VERSION 5.8 ;
BUSBITCHARS "[]" ;
DIVIDERCHAR "/" ;
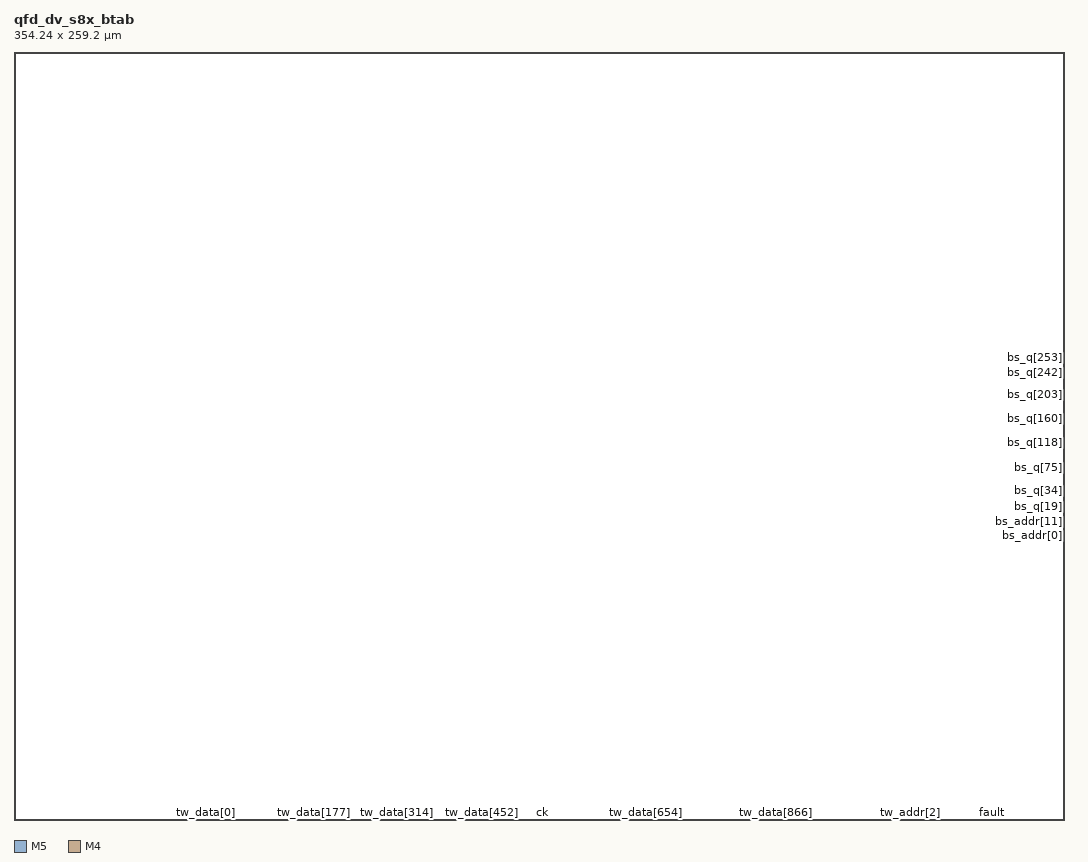
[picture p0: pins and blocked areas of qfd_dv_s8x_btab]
MACRO qfd_dv_s8x_btab
 CLASS BLOCK ;
 ORIGIN 0 0 ;
 SIZE 354.24 BY 259.2 ;
 SYMMETRY X Y ;
 PIN tw_data[0]
  DIRECTION INPUT ;
  USE SIGNAL ;
  PORT
   LAYER M5 ;
   RECT 64.800000 0.000000 64.824000 0.084000 ;
  END
 END tw_data[0]
 PIN tw_data[1]
  DIRECTION INPUT ;
  USE SIGNAL ;
  PORT
   LAYER M5 ;
   RECT 64.992000 0.000000 65.016000 0.084000 ;
  END
 END tw_data[1]
 PIN tw_data[2]
  DIRECTION INPUT ;
  USE SIGNAL ;
  PORT
   LAYER M5 ;
   RECT 65.184000 0.000000 65.208000 0.084000 ;
  END
 END tw_data[2]
 PIN tw_data[3]
  DIRECTION INPUT ;
  USE SIGNAL ;
  PORT
   LAYER M5 ;
   RECT 65.376000 0.000000 65.400000 0.084000 ;
  END
 END tw_data[3]
 PIN tw_data[4]
  DIRECTION INPUT ;
  USE SIGNAL ;
  PORT
   LAYER M5 ;
   RECT 65.568000 0.000000 65.592000 0.084000 ;
  END
 END tw_data[4]
 PIN tw_data[5]
  DIRECTION INPUT ;
  USE SIGNAL ;
  PORT
   LAYER M5 ;
   RECT 65.760000 0.000000 65.784000 0.084000 ;
  END
 END tw_data[5]
 PIN tw_data[6]
  DIRECTION INPUT ;
  USE SIGNAL ;
  PORT
   LAYER M5 ;
   RECT 65.952000 0.000000 65.976000 0.084000 ;
  END
 END tw_data[6]
 PIN tw_data[7]
  DIRECTION INPUT ;
  USE SIGNAL ;
  PORT
   LAYER M5 ;
   RECT 66.144000 0.000000 66.168000 0.084000 ;
  END
 END tw_data[7]
 PIN tw_data[8]
  DIRECTION INPUT ;
  USE SIGNAL ;
  PORT
   LAYER M5 ;
   RECT 66.336000 0.000000 66.360000 0.084000 ;
  END
 END tw_data[8]
 PIN tw_data[9]
  DIRECTION INPUT ;
  USE SIGNAL ;
  PORT
   LAYER M5 ;
   RECT 66.528000 0.000000 66.552000 0.084000 ;
  END
 END tw_data[9]
 PIN tw_data[10]
  DIRECTION INPUT ;
  USE SIGNAL ;
  PORT
   LAYER M5 ;
   RECT 66.720000 0.000000 66.744000 0.084000 ;
  END
 END tw_data[10]
 PIN tw_data[11]
  DIRECTION INPUT ;
  USE SIGNAL ;
  PORT
   LAYER M5 ;
   RECT 67.152000 0.000000 67.176000 0.084000 ;
  END
 END tw_data[11]
 PIN tw_data[12]
  DIRECTION INPUT ;
  USE SIGNAL ;
  PORT
   LAYER M5 ;
   RECT 67.344000 0.000000 67.368000 0.084000 ;
  END
 END tw_data[12]
 PIN tw_data[13]
  DIRECTION INPUT ;
  USE SIGNAL ;
  PORT
   LAYER M5 ;
   RECT 67.536000 0.000000 67.560000 0.084000 ;
  END
 END tw_data[13]
 PIN tw_data[14]
  DIRECTION INPUT ;
  USE SIGNAL ;
  PORT
   LAYER M5 ;
   RECT 67.728000 0.000000 67.752000 0.084000 ;
  END
 END tw_data[14]
 PIN tw_data[15]
  DIRECTION INPUT ;
  USE SIGNAL ;
  PORT
   LAYER M5 ;
   RECT 67.920000 0.000000 67.944000 0.084000 ;
  END
 END tw_data[15]
 PIN tw_data[16]
  DIRECTION INPUT ;
  USE SIGNAL ;
  PORT
   LAYER M5 ;
   RECT 68.112000 0.000000 68.136000 0.084000 ;
  END
 END tw_data[16]
 PIN tw_data[17]
  DIRECTION INPUT ;
  USE SIGNAL ;
  PORT
   LAYER M5 ;
   RECT 68.304000 0.000000 68.328000 0.084000 ;
  END
 END tw_data[17]
 PIN tw_data[18]
  DIRECTION INPUT ;
  USE SIGNAL ;
  PORT
   LAYER M5 ;
   RECT 68.496000 0.000000 68.520000 0.084000 ;
  END
 END tw_data[18]
 PIN tw_data[19]
  DIRECTION INPUT ;
  USE SIGNAL ;
  PORT
   LAYER M5 ;
   RECT 68.688000 0.000000 68.712000 0.084000 ;
  END
 END tw_data[19]
 PIN tw_data[20]
  DIRECTION INPUT ;
  USE SIGNAL ;
  PORT
   LAYER M5 ;
   RECT 68.880000 0.000000 68.904000 0.084000 ;
  END
 END tw_data[20]
 PIN tw_data[21]
  DIRECTION INPUT ;
  USE SIGNAL ;
  PORT
   LAYER M5 ;
   RECT 69.072000 0.000000 69.096000 0.084000 ;
  END
 END tw_data[21]
 PIN tw_data[22]
  DIRECTION INPUT ;
  USE SIGNAL ;
  PORT
   LAYER M5 ;
   RECT 69.264000 0.000000 69.288000 0.084000 ;
  END
 END tw_data[22]
 PIN tw_data[23]
  DIRECTION INPUT ;
  USE SIGNAL ;
  PORT
   LAYER M5 ;
   RECT 69.456000 0.000000 69.480000 0.084000 ;
  END
 END tw_data[23]
 PIN tw_data[24]
  DIRECTION INPUT ;
  USE SIGNAL ;
  PORT
   LAYER M5 ;
   RECT 69.648000 0.000000 69.672000 0.084000 ;
  END
 END tw_data[24]
 PIN tw_data[25]
  DIRECTION INPUT ;
  USE SIGNAL ;
  PORT
   LAYER M5 ;
   RECT 69.840000 0.000000 69.864000 0.084000 ;
  END
 END tw_data[25]
 PIN tw_data[26]
  DIRECTION INPUT ;
  USE SIGNAL ;
  PORT
   LAYER M5 ;
   RECT 70.032000 0.000000 70.056000 0.084000 ;
  END
 END tw_data[26]
 PIN tw_data[27]
  DIRECTION INPUT ;
  USE SIGNAL ;
  PORT
   LAYER M5 ;
   RECT 70.224000 0.000000 70.248000 0.084000 ;
  END
 END tw_data[27]
 PIN tw_data[28]
  DIRECTION INPUT ;
  USE SIGNAL ;
  PORT
   LAYER M5 ;
   RECT 70.416000 0.000000 70.440000 0.084000 ;
  END
 END tw_data[28]
 PIN tw_data[29]
  DIRECTION INPUT ;
  USE SIGNAL ;
  PORT
   LAYER M5 ;
   RECT 70.608000 0.000000 70.632000 0.084000 ;
  END
 END tw_data[29]
 PIN tw_data[30]
  DIRECTION INPUT ;
  USE SIGNAL ;
  PORT
   LAYER M5 ;
   RECT 70.800000 0.000000 70.824000 0.084000 ;
  END
 END tw_data[30]
 PIN tw_data[31]
  DIRECTION INPUT ;
  USE SIGNAL ;
  PORT
   LAYER M5 ;
   RECT 70.992000 0.000000 71.016000 0.084000 ;
  END
 END tw_data[31]
 PIN tw_data[32]
  DIRECTION INPUT ;
  USE SIGNAL ;
  PORT
   LAYER M5 ;
   RECT 71.472000 0.000000 71.496000 0.084000 ;
  END
 END tw_data[32]
 PIN tw_data[33]
  DIRECTION INPUT ;
  USE SIGNAL ;
  PORT
   LAYER M5 ;
   RECT 71.664000 0.000000 71.688000 0.084000 ;
  END
 END tw_data[33]
 PIN tw_data[34]
  DIRECTION INPUT ;
  USE SIGNAL ;
  PORT
   LAYER M5 ;
   RECT 71.856000 0.000000 71.880000 0.084000 ;
  END
 END tw_data[34]
 PIN tw_data[35]
  DIRECTION INPUT ;
  USE SIGNAL ;
  PORT
   LAYER M5 ;
   RECT 72.048000 0.000000 72.072000 0.084000 ;
  END
 END tw_data[35]
 PIN tw_data[36]
  DIRECTION INPUT ;
  USE SIGNAL ;
  PORT
   LAYER M5 ;
   RECT 72.240000 0.000000 72.264000 0.084000 ;
  END
 END tw_data[36]
 PIN tw_data[37]
  DIRECTION INPUT ;
  USE SIGNAL ;
  PORT
   LAYER M5 ;
   RECT 72.432000 0.000000 72.456000 0.084000 ;
  END
 END tw_data[37]
 PIN tw_data[38]
  DIRECTION INPUT ;
  USE SIGNAL ;
  PORT
   LAYER M5 ;
   RECT 72.624000 0.000000 72.648000 0.084000 ;
  END
 END tw_data[38]
 PIN tw_data[39]
  DIRECTION INPUT ;
  USE SIGNAL ;
  PORT
   LAYER M5 ;
   RECT 72.816000 0.000000 72.840000 0.084000 ;
  END
 END tw_data[39]
 PIN tw_data[40]
  DIRECTION INPUT ;
  USE SIGNAL ;
  PORT
   LAYER M5 ;
   RECT 73.008000 0.000000 73.032000 0.084000 ;
  END
 END tw_data[40]
 PIN tw_data[41]
  DIRECTION INPUT ;
  USE SIGNAL ;
  PORT
   LAYER M5 ;
   RECT 73.200000 0.000000 73.224000 0.084000 ;
  END
 END tw_data[41]
 PIN tw_data[42]
  DIRECTION INPUT ;
  USE SIGNAL ;
  PORT
   LAYER M5 ;
   RECT 73.392000 0.000000 73.416000 0.084000 ;
  END
 END tw_data[42]
 PIN tw_data[43]
  DIRECTION INPUT ;
  USE SIGNAL ;
  PORT
   LAYER M5 ;
   RECT 73.584000 0.000000 73.608000 0.084000 ;
  END
 END tw_data[43]
 PIN tw_data[44]
  DIRECTION INPUT ;
  USE SIGNAL ;
  PORT
   LAYER M5 ;
   RECT 73.776000 0.000000 73.800000 0.084000 ;
  END
 END tw_data[44]
 PIN tw_data[45]
  DIRECTION INPUT ;
  USE SIGNAL ;
  PORT
   LAYER M5 ;
   RECT 73.968000 0.000000 73.992000 0.084000 ;
  END
 END tw_data[45]
 PIN tw_data[46]
  DIRECTION INPUT ;
  USE SIGNAL ;
  PORT
   LAYER M5 ;
   RECT 74.160000 0.000000 74.184000 0.084000 ;
  END
 END tw_data[46]
 PIN tw_data[47]
  DIRECTION INPUT ;
  USE SIGNAL ;
  PORT
   LAYER M5 ;
   RECT 74.352000 0.000000 74.376000 0.084000 ;
  END
 END tw_data[47]
 PIN tw_data[48]
  DIRECTION INPUT ;
  USE SIGNAL ;
  PORT
   LAYER M5 ;
   RECT 74.544000 0.000000 74.568000 0.084000 ;
  END
 END tw_data[48]
 PIN tw_data[49]
  DIRECTION INPUT ;
  USE SIGNAL ;
  PORT
   LAYER M5 ;
   RECT 74.736000 0.000000 74.760000 0.084000 ;
  END
 END tw_data[49]
 PIN tw_data[50]
  DIRECTION INPUT ;
  USE SIGNAL ;
  PORT
   LAYER M5 ;
   RECT 74.928000 0.000000 74.952000 0.084000 ;
  END
 END tw_data[50]
 PIN tw_data[51]
  DIRECTION INPUT ;
  USE SIGNAL ;
  PORT
   LAYER M5 ;
   RECT 75.120000 0.000000 75.144000 0.084000 ;
  END
 END tw_data[51]
 PIN tw_data[52]
  DIRECTION INPUT ;
  USE SIGNAL ;
  PORT
   LAYER M5 ;
   RECT 75.312000 0.000000 75.336000 0.084000 ;
  END
 END tw_data[52]
 PIN tw_data[53]
  DIRECTION INPUT ;
  USE SIGNAL ;
  PORT
   LAYER M5 ;
   RECT 75.792000 0.000000 75.816000 0.084000 ;
  END
 END tw_data[53]
 PIN tw_data[54]
  DIRECTION INPUT ;
  USE SIGNAL ;
  PORT
   LAYER M5 ;
   RECT 75.984000 0.000000 76.008000 0.084000 ;
  END
 END tw_data[54]
 PIN tw_data[55]
  DIRECTION INPUT ;
  USE SIGNAL ;
  PORT
   LAYER M5 ;
   RECT 76.176000 0.000000 76.200000 0.084000 ;
  END
 END tw_data[55]
 PIN tw_data[56]
  DIRECTION INPUT ;
  USE SIGNAL ;
  PORT
   LAYER M5 ;
   RECT 76.368000 0.000000 76.392000 0.084000 ;
  END
 END tw_data[56]
 PIN tw_data[57]
  DIRECTION INPUT ;
  USE SIGNAL ;
  PORT
   LAYER M5 ;
   RECT 76.560000 0.000000 76.584000 0.084000 ;
  END
 END tw_data[57]
 PIN tw_data[58]
  DIRECTION INPUT ;
  USE SIGNAL ;
  PORT
   LAYER M5 ;
   RECT 76.752000 0.000000 76.776000 0.084000 ;
  END
 END tw_data[58]
 PIN tw_data[59]
  DIRECTION INPUT ;
  USE SIGNAL ;
  PORT
   LAYER M5 ;
   RECT 76.944000 0.000000 76.968000 0.084000 ;
  END
 END tw_data[59]
 PIN tw_data[60]
  DIRECTION INPUT ;
  USE SIGNAL ;
  PORT
   LAYER M5 ;
   RECT 77.136000 0.000000 77.160000 0.084000 ;
  END
 END tw_data[60]
 PIN tw_data[61]
  DIRECTION INPUT ;
  USE SIGNAL ;
  PORT
   LAYER M5 ;
   RECT 77.328000 0.000000 77.352000 0.084000 ;
  END
 END tw_data[61]
 PIN tw_data[62]
  DIRECTION INPUT ;
  USE SIGNAL ;
  PORT
   LAYER M5 ;
   RECT 77.520000 0.000000 77.544000 0.084000 ;
  END
 END tw_data[62]
 PIN tw_data[63]
  DIRECTION INPUT ;
  USE SIGNAL ;
  PORT
   LAYER M5 ;
   RECT 77.712000 0.000000 77.736000 0.084000 ;
  END
 END tw_data[63]
 PIN tw_data[64]
  DIRECTION INPUT ;
  USE SIGNAL ;
  PORT
   LAYER M5 ;
   RECT 77.904000 0.000000 77.928000 0.084000 ;
  END
 END tw_data[64]
 PIN tw_data[65]
  DIRECTION INPUT ;
  USE SIGNAL ;
  PORT
   LAYER M5 ;
   RECT 78.096000 0.000000 78.120000 0.084000 ;
  END
 END tw_data[65]
 PIN tw_data[66]
  DIRECTION INPUT ;
  USE SIGNAL ;
  PORT
   LAYER M5 ;
   RECT 78.288000 0.000000 78.312000 0.084000 ;
  END
 END tw_data[66]
 PIN tw_data[67]
  DIRECTION INPUT ;
  USE SIGNAL ;
  PORT
   LAYER M5 ;
   RECT 78.480000 0.000000 78.504000 0.084000 ;
  END
 END tw_data[67]
 PIN tw_data[68]
  DIRECTION INPUT ;
  USE SIGNAL ;
  PORT
   LAYER M5 ;
   RECT 78.672000 0.000000 78.696000 0.084000 ;
  END
 END tw_data[68]
 PIN tw_data[69]
  DIRECTION INPUT ;
  USE SIGNAL ;
  PORT
   LAYER M5 ;
   RECT 78.864000 0.000000 78.888000 0.084000 ;
  END
 END tw_data[69]
 PIN tw_data[70]
  DIRECTION INPUT ;
  USE SIGNAL ;
  PORT
   LAYER M5 ;
   RECT 79.056000 0.000000 79.080000 0.084000 ;
  END
 END tw_data[70]
 PIN tw_data[71]
  DIRECTION INPUT ;
  USE SIGNAL ;
  PORT
   LAYER M5 ;
   RECT 79.248000 0.000000 79.272000 0.084000 ;
  END
 END tw_data[71]
 PIN tw_data[72]
  DIRECTION INPUT ;
  USE SIGNAL ;
  PORT
   LAYER M5 ;
   RECT 79.440000 0.000000 79.464000 0.084000 ;
  END
 END tw_data[72]
 PIN tw_data[73]
  DIRECTION INPUT ;
  USE SIGNAL ;
  PORT
   LAYER M5 ;
   RECT 79.632000 0.000000 79.656000 0.084000 ;
  END
 END tw_data[73]
 PIN tw_data[74]
  DIRECTION INPUT ;
  USE SIGNAL ;
  PORT
   LAYER M5 ;
   RECT 80.112000 0.000000 80.136000 0.084000 ;
  END
 END tw_data[74]
 PIN tw_data[75]
  DIRECTION INPUT ;
  USE SIGNAL ;
  PORT
   LAYER M5 ;
   RECT 80.304000 0.000000 80.328000 0.084000 ;
  END
 END tw_data[75]
 PIN tw_data[76]
  DIRECTION INPUT ;
  USE SIGNAL ;
  PORT
   LAYER M5 ;
   RECT 80.496000 0.000000 80.520000 0.084000 ;
  END
 END tw_data[76]
 PIN tw_data[77]
  DIRECTION INPUT ;
  USE SIGNAL ;
  PORT
   LAYER M5 ;
   RECT 80.688000 0.000000 80.712000 0.084000 ;
  END
 END tw_data[77]
 PIN tw_data[78]
  DIRECTION INPUT ;
  USE SIGNAL ;
  PORT
   LAYER M5 ;
   RECT 80.880000 0.000000 80.904000 0.084000 ;
  END
 END tw_data[78]
 PIN tw_data[79]
  DIRECTION INPUT ;
  USE SIGNAL ;
  PORT
   LAYER M5 ;
   RECT 81.072000 0.000000 81.096000 0.084000 ;
  END
 END tw_data[79]
 PIN tw_data[80]
  DIRECTION INPUT ;
  USE SIGNAL ;
  PORT
   LAYER M5 ;
   RECT 81.264000 0.000000 81.288000 0.084000 ;
  END
 END tw_data[80]
 PIN tw_data[81]
  DIRECTION INPUT ;
  USE SIGNAL ;
  PORT
   LAYER M5 ;
   RECT 81.456000 0.000000 81.480000 0.084000 ;
  END
 END tw_data[81]
 PIN tw_data[82]
  DIRECTION INPUT ;
  USE SIGNAL ;
  PORT
   LAYER M5 ;
   RECT 81.648000 0.000000 81.672000 0.084000 ;
  END
 END tw_data[82]
 PIN tw_data[83]
  DIRECTION INPUT ;
  USE SIGNAL ;
  PORT
   LAYER M5 ;
   RECT 81.840000 0.000000 81.864000 0.084000 ;
  END
 END tw_data[83]
 PIN tw_data[84]
  DIRECTION INPUT ;
  USE SIGNAL ;
  PORT
   LAYER M5 ;
   RECT 82.032000 0.000000 82.056000 0.084000 ;
  END
 END tw_data[84]
 PIN tw_data[85]
  DIRECTION INPUT ;
  USE SIGNAL ;
  PORT
   LAYER M5 ;
   RECT 82.224000 0.000000 82.248000 0.084000 ;
  END
 END tw_data[85]
 PIN tw_data[86]
  DIRECTION INPUT ;
  USE SIGNAL ;
  PORT
   LAYER M5 ;
   RECT 82.416000 0.000000 82.440000 0.084000 ;
  END
 END tw_data[86]
 PIN tw_data[87]
  DIRECTION INPUT ;
  USE SIGNAL ;
  PORT
   LAYER M5 ;
   RECT 82.608000 0.000000 82.632000 0.084000 ;
  END
 END tw_data[87]
 PIN tw_data[88]
  DIRECTION INPUT ;
  USE SIGNAL ;
  PORT
   LAYER M5 ;
   RECT 82.800000 0.000000 82.824000 0.084000 ;
  END
 END tw_data[88]
 PIN tw_data[89]
  DIRECTION INPUT ;
  USE SIGNAL ;
  PORT
   LAYER M5 ;
   RECT 82.992000 0.000000 83.016000 0.084000 ;
  END
 END tw_data[89]
 PIN tw_data[90]
  DIRECTION INPUT ;
  USE SIGNAL ;
  PORT
   LAYER M5 ;
   RECT 83.184000 0.000000 83.208000 0.084000 ;
  END
 END tw_data[90]
 PIN tw_data[91]
  DIRECTION INPUT ;
  USE SIGNAL ;
  PORT
   LAYER M5 ;
   RECT 83.376000 0.000000 83.400000 0.084000 ;
  END
 END tw_data[91]
 PIN tw_data[92]
  DIRECTION INPUT ;
  USE SIGNAL ;
  PORT
   LAYER M5 ;
   RECT 83.568000 0.000000 83.592000 0.084000 ;
  END
 END tw_data[92]
 PIN tw_data[93]
  DIRECTION INPUT ;
  USE SIGNAL ;
  PORT
   LAYER M5 ;
   RECT 83.760000 0.000000 83.784000 0.084000 ;
  END
 END tw_data[93]
 PIN tw_data[94]
  DIRECTION INPUT ;
  USE SIGNAL ;
  PORT
   LAYER M5 ;
   RECT 83.952000 0.000000 83.976000 0.084000 ;
  END
 END tw_data[94]
 PIN tw_data[95]
  DIRECTION INPUT ;
  USE SIGNAL ;
  PORT
   LAYER M5 ;
   RECT 84.432000 0.000000 84.456000 0.084000 ;
  END
 END tw_data[95]
 PIN tw_data[96]
  DIRECTION INPUT ;
  USE SIGNAL ;
  PORT
   LAYER M5 ;
   RECT 84.624000 0.000000 84.648000 0.084000 ;
  END
 END tw_data[96]
 PIN tw_data[97]
  DIRECTION INPUT ;
  USE SIGNAL ;
  PORT
   LAYER M5 ;
   RECT 84.816000 0.000000 84.840000 0.084000 ;
  END
 END tw_data[97]
 PIN tw_data[98]
  DIRECTION INPUT ;
  USE SIGNAL ;
  PORT
   LAYER M5 ;
   RECT 85.008000 0.000000 85.032000 0.084000 ;
  END
 END tw_data[98]
 PIN tw_data[99]
  DIRECTION INPUT ;
  USE SIGNAL ;
  PORT
   LAYER M5 ;
   RECT 85.200000 0.000000 85.224000 0.084000 ;
  END
 END tw_data[99]
 PIN tw_data[100]
  DIRECTION INPUT ;
  USE SIGNAL ;
  PORT
   LAYER M5 ;
   RECT 85.392000 0.000000 85.416000 0.084000 ;
  END
 END tw_data[100]
 PIN tw_data[101]
  DIRECTION INPUT ;
  USE SIGNAL ;
  PORT
   LAYER M5 ;
   RECT 85.584000 0.000000 85.608000 0.084000 ;
  END
 END tw_data[101]
 PIN tw_data[102]
  DIRECTION INPUT ;
  USE SIGNAL ;
  PORT
   LAYER M5 ;
   RECT 85.776000 0.000000 85.800000 0.084000 ;
  END
 END tw_data[102]
 PIN tw_data[103]
  DIRECTION INPUT ;
  USE SIGNAL ;
  PORT
   LAYER M5 ;
   RECT 85.968000 0.000000 85.992000 0.084000 ;
  END
 END tw_data[103]
 PIN tw_data[104]
  DIRECTION INPUT ;
  USE SIGNAL ;
  PORT
   LAYER M5 ;
   RECT 86.160000 0.000000 86.184000 0.084000 ;
  END
 END tw_data[104]
 PIN tw_data[105]
  DIRECTION INPUT ;
  USE SIGNAL ;
  PORT
   LAYER M5 ;
   RECT 86.352000 0.000000 86.376000 0.084000 ;
  END
 END tw_data[105]
 PIN tw_data[106]
  DIRECTION INPUT ;
  USE SIGNAL ;
  PORT
   LAYER M5 ;
   RECT 86.544000 0.000000 86.568000 0.084000 ;
  END
 END tw_data[106]
 PIN tw_data[107]
  DIRECTION INPUT ;
  USE SIGNAL ;
  PORT
   LAYER M5 ;
   RECT 86.736000 0.000000 86.760000 0.084000 ;
  END
 END tw_data[107]
 PIN tw_data[108]
  DIRECTION INPUT ;
  USE SIGNAL ;
  PORT
   LAYER M5 ;
   RECT 86.928000 0.000000 86.952000 0.084000 ;
  END
 END tw_data[108]
 PIN tw_data[109]
  DIRECTION INPUT ;
  USE SIGNAL ;
  PORT
   LAYER M5 ;
   RECT 87.120000 0.000000 87.144000 0.084000 ;
  END
 END tw_data[109]
 PIN tw_data[110]
  DIRECTION INPUT ;
  USE SIGNAL ;
  PORT
   LAYER M5 ;
   RECT 87.312000 0.000000 87.336000 0.084000 ;
  END
 END tw_data[110]
 PIN tw_data[111]
  DIRECTION INPUT ;
  USE SIGNAL ;
  PORT
   LAYER M5 ;
   RECT 87.504000 0.000000 87.528000 0.084000 ;
  END
 END tw_data[111]
 PIN tw_data[112]
  DIRECTION INPUT ;
  USE SIGNAL ;
  PORT
   LAYER M5 ;
   RECT 87.696000 0.000000 87.720000 0.084000 ;
  END
 END tw_data[112]
 PIN tw_data[113]
  DIRECTION INPUT ;
  USE SIGNAL ;
  PORT
   LAYER M5 ;
   RECT 87.888000 0.000000 87.912000 0.084000 ;
  END
 END tw_data[113]
 PIN tw_data[114]
  DIRECTION INPUT ;
  USE SIGNAL ;
  PORT
   LAYER M5 ;
   RECT 88.080000 0.000000 88.104000 0.084000 ;
  END
 END tw_data[114]
 PIN tw_data[115]
  DIRECTION INPUT ;
  USE SIGNAL ;
  PORT
   LAYER M5 ;
   RECT 88.272000 0.000000 88.296000 0.084000 ;
  END
 END tw_data[115]
 PIN tw_data[116]
  DIRECTION INPUT ;
  USE SIGNAL ;
  PORT
   LAYER M5 ;
   RECT 88.752000 0.000000 88.776000 0.084000 ;
  END
 END tw_data[116]
 PIN tw_data[117]
  DIRECTION INPUT ;
  USE SIGNAL ;
  PORT
   LAYER M5 ;
   RECT 88.944000 0.000000 88.968000 0.084000 ;
  END
 END tw_data[117]
 PIN tw_data[118]
  DIRECTION INPUT ;
  USE SIGNAL ;
  PORT
   LAYER M5 ;
   RECT 89.136000 0.000000 89.160000 0.084000 ;
  END
 END tw_data[118]
 PIN tw_data[119]
  DIRECTION INPUT ;
  USE SIGNAL ;
  PORT
   LAYER M5 ;
   RECT 89.328000 0.000000 89.352000 0.084000 ;
  END
 END tw_data[119]
 PIN tw_data[120]
  DIRECTION INPUT ;
  USE SIGNAL ;
  PORT
   LAYER M5 ;
   RECT 89.520000 0.000000 89.544000 0.084000 ;
  END
 END tw_data[120]
 PIN tw_data[121]
  DIRECTION INPUT ;
  USE SIGNAL ;
  PORT
   LAYER M5 ;
   RECT 89.712000 0.000000 89.736000 0.084000 ;
  END
 END tw_data[121]
 PIN tw_data[122]
  DIRECTION INPUT ;
  USE SIGNAL ;
  PORT
   LAYER M5 ;
   RECT 89.904000 0.000000 89.928000 0.084000 ;
  END
 END tw_data[122]
 PIN tw_data[123]
  DIRECTION INPUT ;
  USE SIGNAL ;
  PORT
   LAYER M5 ;
   RECT 90.096000 0.000000 90.120000 0.084000 ;
  END
 END tw_data[123]
 PIN tw_data[124]
  DIRECTION INPUT ;
  USE SIGNAL ;
  PORT
   LAYER M5 ;
   RECT 90.288000 0.000000 90.312000 0.084000 ;
  END
 END tw_data[124]
 PIN tw_data[125]
  DIRECTION INPUT ;
  USE SIGNAL ;
  PORT
   LAYER M5 ;
   RECT 90.480000 0.000000 90.504000 0.084000 ;
  END
 END tw_data[125]
 PIN tw_data[126]
  DIRECTION INPUT ;
  USE SIGNAL ;
  PORT
   LAYER M5 ;
   RECT 90.672000 0.000000 90.696000 0.084000 ;
  END
 END tw_data[126]
 PIN tw_data[127]
  DIRECTION INPUT ;
  USE SIGNAL ;
  PORT
   LAYER M5 ;
   RECT 90.864000 0.000000 90.888000 0.084000 ;
  END
 END tw_data[127]
 PIN tw_data[128]
  DIRECTION INPUT ;
  USE SIGNAL ;
  PORT
   LAYER M5 ;
   RECT 91.056000 0.000000 91.080000 0.084000 ;
  END
 END tw_data[128]
 PIN tw_data[129]
  DIRECTION INPUT ;
  USE SIGNAL ;
  PORT
   LAYER M5 ;
   RECT 91.248000 0.000000 91.272000 0.084000 ;
  END
 END tw_data[129]
 PIN tw_data[130]
  DIRECTION INPUT ;
  USE SIGNAL ;
  PORT
   LAYER M5 ;
   RECT 91.440000 0.000000 91.464000 0.084000 ;
  END
 END tw_data[130]
 PIN tw_data[131]
  DIRECTION INPUT ;
  USE SIGNAL ;
  PORT
   LAYER M5 ;
   RECT 91.632000 0.000000 91.656000 0.084000 ;
  END
 END tw_data[131]
 PIN tw_data[132]
  DIRECTION INPUT ;
  USE SIGNAL ;
  PORT
   LAYER M5 ;
   RECT 91.824000 0.000000 91.848000 0.084000 ;
  END
 END tw_data[132]
 PIN tw_data[133]
  DIRECTION INPUT ;
  USE SIGNAL ;
  PORT
   LAYER M5 ;
   RECT 92.016000 0.000000 92.040000 0.084000 ;
  END
 END tw_data[133]
 PIN tw_data[134]
  DIRECTION INPUT ;
  USE SIGNAL ;
  PORT
   LAYER M5 ;
   RECT 92.208000 0.000000 92.232000 0.084000 ;
  END
 END tw_data[134]
 PIN tw_data[135]
  DIRECTION INPUT ;
  USE SIGNAL ;
  PORT
   LAYER M5 ;
   RECT 92.400000 0.000000 92.424000 0.084000 ;
  END
 END tw_data[135]
 PIN tw_data[136]
  DIRECTION INPUT ;
  USE SIGNAL ;
  PORT
   LAYER M5 ;
   RECT 92.592000 0.000000 92.616000 0.084000 ;
  END
 END tw_data[136]
 PIN tw_data[137]
  DIRECTION INPUT ;
  USE SIGNAL ;
  PORT
   LAYER M5 ;
   RECT 93.072000 0.000000 93.096000 0.084000 ;
  END
 END tw_data[137]
 PIN tw_data[138]
  DIRECTION INPUT ;
  USE SIGNAL ;
  PORT
   LAYER M5 ;
   RECT 93.264000 0.000000 93.288000 0.084000 ;
  END
 END tw_data[138]
 PIN tw_data[139]
  DIRECTION INPUT ;
  USE SIGNAL ;
  PORT
   LAYER M5 ;
   RECT 93.456000 0.000000 93.480000 0.084000 ;
  END
 END tw_data[139]
 PIN tw_data[140]
  DIRECTION INPUT ;
  USE SIGNAL ;
  PORT
   LAYER M5 ;
   RECT 93.648000 0.000000 93.672000 0.084000 ;
  END
 END tw_data[140]
 PIN tw_data[141]
  DIRECTION INPUT ;
  USE SIGNAL ;
  PORT
   LAYER M5 ;
   RECT 93.840000 0.000000 93.864000 0.084000 ;
  END
 END tw_data[141]
 PIN tw_data[142]
  DIRECTION INPUT ;
  USE SIGNAL ;
  PORT
   LAYER M5 ;
   RECT 94.032000 0.000000 94.056000 0.084000 ;
  END
 END tw_data[142]
 PIN tw_data[143]
  DIRECTION INPUT ;
  USE SIGNAL ;
  PORT
   LAYER M5 ;
   RECT 94.224000 0.000000 94.248000 0.084000 ;
  END
 END tw_data[143]
 PIN tw_data[144]
  DIRECTION INPUT ;
  USE SIGNAL ;
  PORT
   LAYER M5 ;
   RECT 94.416000 0.000000 94.440000 0.084000 ;
  END
 END tw_data[144]
 PIN tw_data[145]
  DIRECTION INPUT ;
  USE SIGNAL ;
  PORT
   LAYER M5 ;
   RECT 94.608000 0.000000 94.632000 0.084000 ;
  END
 END tw_data[145]
 PIN tw_data[146]
  DIRECTION INPUT ;
  USE SIGNAL ;
  PORT
   LAYER M5 ;
   RECT 94.800000 0.000000 94.824000 0.084000 ;
  END
 END tw_data[146]
 PIN tw_data[147]
  DIRECTION INPUT ;
  USE SIGNAL ;
  PORT
   LAYER M5 ;
   RECT 94.992000 0.000000 95.016000 0.084000 ;
  END
 END tw_data[147]
 PIN tw_data[148]
  DIRECTION INPUT ;
  USE SIGNAL ;
  PORT
   LAYER M5 ;
   RECT 95.184000 0.000000 95.208000 0.084000 ;
  END
 END tw_data[148]
 PIN tw_data[149]
  DIRECTION INPUT ;
  USE SIGNAL ;
  PORT
   LAYER M5 ;
   RECT 95.376000 0.000000 95.400000 0.084000 ;
  END
 END tw_data[149]
 PIN tw_data[150]
  DIRECTION INPUT ;
  USE SIGNAL ;
  PORT
   LAYER M5 ;
   RECT 95.568000 0.000000 95.592000 0.084000 ;
  END
 END tw_data[150]
 PIN tw_data[151]
  DIRECTION INPUT ;
  USE SIGNAL ;
  PORT
   LAYER M5 ;
   RECT 95.760000 0.000000 95.784000 0.084000 ;
  END
 END tw_data[151]
 PIN tw_data[152]
  DIRECTION INPUT ;
  USE SIGNAL ;
  PORT
   LAYER M5 ;
   RECT 95.952000 0.000000 95.976000 0.084000 ;
  END
 END tw_data[152]
 PIN tw_data[153]
  DIRECTION INPUT ;
  USE SIGNAL ;
  PORT
   LAYER M5 ;
   RECT 96.144000 0.000000 96.168000 0.084000 ;
  END
 END tw_data[153]
 PIN tw_data[154]
  DIRECTION INPUT ;
  USE SIGNAL ;
  PORT
   LAYER M5 ;
   RECT 96.336000 0.000000 96.360000 0.084000 ;
  END
 END tw_data[154]
 PIN tw_data[155]
  DIRECTION INPUT ;
  USE SIGNAL ;
  PORT
   LAYER M5 ;
   RECT 96.528000 0.000000 96.552000 0.084000 ;
  END
 END tw_data[155]
 PIN tw_data[156]
  DIRECTION INPUT ;
  USE SIGNAL ;
  PORT
   LAYER M5 ;
   RECT 96.720000 0.000000 96.744000 0.084000 ;
  END
 END tw_data[156]
 PIN tw_data[157]
  DIRECTION INPUT ;
  USE SIGNAL ;
  PORT
   LAYER M5 ;
   RECT 96.912000 0.000000 96.936000 0.084000 ;
  END
 END tw_data[157]
 PIN tw_data[158]
  DIRECTION INPUT ;
  USE SIGNAL ;
  PORT
   LAYER M5 ;
   RECT 97.392000 0.000000 97.416000 0.084000 ;
  END
 END tw_data[158]
 PIN tw_data[159]
  DIRECTION INPUT ;
  USE SIGNAL ;
  PORT
   LAYER M5 ;
   RECT 97.584000 0.000000 97.608000 0.084000 ;
  END
 END tw_data[159]
 PIN tw_data[160]
  DIRECTION INPUT ;
  USE SIGNAL ;
  PORT
   LAYER M5 ;
   RECT 97.776000 0.000000 97.800000 0.084000 ;
  END
 END tw_data[160]
 PIN tw_data[161]
  DIRECTION INPUT ;
  USE SIGNAL ;
  PORT
   LAYER M5 ;
   RECT 97.968000 0.000000 97.992000 0.084000 ;
  END
 END tw_data[161]
 PIN tw_data[162]
  DIRECTION INPUT ;
  USE SIGNAL ;
  PORT
   LAYER M5 ;
   RECT 98.160000 0.000000 98.184000 0.084000 ;
  END
 END tw_data[162]
 PIN tw_data[163]
  DIRECTION INPUT ;
  USE SIGNAL ;
  PORT
   LAYER M5 ;
   RECT 98.352000 0.000000 98.376000 0.084000 ;
  END
 END tw_data[163]
 PIN tw_data[164]
  DIRECTION INPUT ;
  USE SIGNAL ;
  PORT
   LAYER M5 ;
   RECT 98.544000 0.000000 98.568000 0.084000 ;
  END
 END tw_data[164]
 PIN tw_data[165]
  DIRECTION INPUT ;
  USE SIGNAL ;
  PORT
   LAYER M5 ;
   RECT 98.736000 0.000000 98.760000 0.084000 ;
  END
 END tw_data[165]
 PIN tw_data[166]
  DIRECTION INPUT ;
  USE SIGNAL ;
  PORT
   LAYER M5 ;
   RECT 98.928000 0.000000 98.952000 0.084000 ;
  END
 END tw_data[166]
 PIN tw_data[167]
  DIRECTION INPUT ;
  USE SIGNAL ;
  PORT
   LAYER M5 ;
   RECT 99.120000 0.000000 99.144000 0.084000 ;
  END
 END tw_data[167]
 PIN tw_data[168]
  DIRECTION INPUT ;
  USE SIGNAL ;
  PORT
   LAYER M5 ;
   RECT 99.312000 0.000000 99.336000 0.084000 ;
  END
 END tw_data[168]
 PIN tw_data[169]
  DIRECTION INPUT ;
  USE SIGNAL ;
  PORT
   LAYER M5 ;
   RECT 99.504000 0.000000 99.528000 0.084000 ;
  END
 END tw_data[169]
 PIN tw_data[170]
  DIRECTION INPUT ;
  USE SIGNAL ;
  PORT
   LAYER M5 ;
   RECT 99.696000 0.000000 99.720000 0.084000 ;
  END
 END tw_data[170]
 PIN tw_data[171]
  DIRECTION INPUT ;
  USE SIGNAL ;
  PORT
   LAYER M5 ;
   RECT 99.888000 0.000000 99.912000 0.084000 ;
  END
 END tw_data[171]
 PIN tw_data[172]
  DIRECTION INPUT ;
  USE SIGNAL ;
  PORT
   LAYER M5 ;
   RECT 100.080000 0.000000 100.104000 0.084000 ;
  END
 END tw_data[172]
 PIN tw_data[173]
  DIRECTION INPUT ;
  USE SIGNAL ;
  PORT
   LAYER M5 ;
   RECT 100.272000 0.000000 100.296000 0.084000 ;
  END
 END tw_data[173]
 PIN tw_data[174]
  DIRECTION INPUT ;
  USE SIGNAL ;
  PORT
   LAYER M5 ;
   RECT 100.464000 0.000000 100.488000 0.084000 ;
  END
 END tw_data[174]
 PIN tw_data[175]
  DIRECTION INPUT ;
  USE SIGNAL ;
  PORT
   LAYER M5 ;
   RECT 100.656000 0.000000 100.680000 0.084000 ;
  END
 END tw_data[175]
 PIN tw_data[176]
  DIRECTION INPUT ;
  USE SIGNAL ;
  PORT
   LAYER M5 ;
   RECT 100.848000 0.000000 100.872000 0.084000 ;
  END
 END tw_data[176]
 PIN tw_data[177]
  DIRECTION INPUT ;
  USE SIGNAL ;
  PORT
   LAYER M5 ;
   RECT 101.040000 0.000000 101.064000 0.084000 ;
  END
 END tw_data[177]
 PIN tw_data[178]
  DIRECTION INPUT ;
  USE SIGNAL ;
  PORT
   LAYER M5 ;
   RECT 101.232000 0.000000 101.256000 0.084000 ;
  END
 END tw_data[178]
 PIN tw_data[179]
  DIRECTION INPUT ;
  USE SIGNAL ;
  PORT
   LAYER M5 ;
   RECT 101.712000 0.000000 101.736000 0.084000 ;
  END
 END tw_data[179]
 PIN tw_data[180]
  DIRECTION INPUT ;
  USE SIGNAL ;
  PORT
   LAYER M5 ;
   RECT 101.904000 0.000000 101.928000 0.084000 ;
  END
 END tw_data[180]
 PIN tw_data[181]
  DIRECTION INPUT ;
  USE SIGNAL ;
  PORT
   LAYER M5 ;
   RECT 102.096000 0.000000 102.120000 0.084000 ;
  END
 END tw_data[181]
 PIN tw_data[182]
  DIRECTION INPUT ;
  USE SIGNAL ;
  PORT
   LAYER M5 ;
   RECT 102.288000 0.000000 102.312000 0.084000 ;
  END
 END tw_data[182]
 PIN tw_data[183]
  DIRECTION INPUT ;
  USE SIGNAL ;
  PORT
   LAYER M5 ;
   RECT 102.480000 0.000000 102.504000 0.084000 ;
  END
 END tw_data[183]
 PIN tw_data[184]
  DIRECTION INPUT ;
  USE SIGNAL ;
  PORT
   LAYER M5 ;
   RECT 102.672000 0.000000 102.696000 0.084000 ;
  END
 END tw_data[184]
 PIN tw_data[185]
  DIRECTION INPUT ;
  USE SIGNAL ;
  PORT
   LAYER M5 ;
   RECT 102.864000 0.000000 102.888000 0.084000 ;
  END
 END tw_data[185]
 PIN tw_data[186]
  DIRECTION INPUT ;
  USE SIGNAL ;
  PORT
   LAYER M5 ;
   RECT 103.056000 0.000000 103.080000 0.084000 ;
  END
 END tw_data[186]
 PIN tw_data[187]
  DIRECTION INPUT ;
  USE SIGNAL ;
  PORT
   LAYER M5 ;
   RECT 103.248000 0.000000 103.272000 0.084000 ;
  END
 END tw_data[187]
 PIN tw_data[188]
  DIRECTION INPUT ;
  USE SIGNAL ;
  PORT
   LAYER M5 ;
   RECT 103.440000 0.000000 103.464000 0.084000 ;
  END
 END tw_data[188]
 PIN tw_data[189]
  DIRECTION INPUT ;
  USE SIGNAL ;
  PORT
   LAYER M5 ;
   RECT 103.632000 0.000000 103.656000 0.084000 ;
  END
 END tw_data[189]
 PIN tw_data[190]
  DIRECTION INPUT ;
  USE SIGNAL ;
  PORT
   LAYER M5 ;
   RECT 103.824000 0.000000 103.848000 0.084000 ;
  END
 END tw_data[190]
 PIN tw_data[191]
  DIRECTION INPUT ;
  USE SIGNAL ;
  PORT
   LAYER M5 ;
   RECT 104.016000 0.000000 104.040000 0.084000 ;
  END
 END tw_data[191]
 PIN tw_data[192]
  DIRECTION INPUT ;
  USE SIGNAL ;
  PORT
   LAYER M5 ;
   RECT 104.208000 0.000000 104.232000 0.084000 ;
  END
 END tw_data[192]
 PIN tw_data[193]
  DIRECTION INPUT ;
  USE SIGNAL ;
  PORT
   LAYER M5 ;
   RECT 104.400000 0.000000 104.424000 0.084000 ;
  END
 END tw_data[193]
 PIN tw_data[194]
  DIRECTION INPUT ;
  USE SIGNAL ;
  PORT
   LAYER M5 ;
   RECT 104.592000 0.000000 104.616000 0.084000 ;
  END
 END tw_data[194]
 PIN tw_data[195]
  DIRECTION INPUT ;
  USE SIGNAL ;
  PORT
   LAYER M5 ;
   RECT 104.784000 0.000000 104.808000 0.084000 ;
  END
 END tw_data[195]
 PIN tw_data[196]
  DIRECTION INPUT ;
  USE SIGNAL ;
  PORT
   LAYER M5 ;
   RECT 104.976000 0.000000 105.000000 0.084000 ;
  END
 END tw_data[196]
 PIN tw_data[197]
  DIRECTION INPUT ;
  USE SIGNAL ;
  PORT
   LAYER M5 ;
   RECT 105.168000 0.000000 105.192000 0.084000 ;
  END
 END tw_data[197]
 PIN tw_data[198]
  DIRECTION INPUT ;
  USE SIGNAL ;
  PORT
   LAYER M5 ;
   RECT 105.360000 0.000000 105.384000 0.084000 ;
  END
 END tw_data[198]
 PIN tw_data[199]
  DIRECTION INPUT ;
  USE SIGNAL ;
  PORT
   LAYER M5 ;
   RECT 105.552000 0.000000 105.576000 0.084000 ;
  END
 END tw_data[199]
 PIN tw_data[200]
  DIRECTION INPUT ;
  USE SIGNAL ;
  PORT
   LAYER M5 ;
   RECT 106.032000 0.000000 106.056000 0.084000 ;
  END
 END tw_data[200]
 PIN tw_data[201]
  DIRECTION INPUT ;
  USE SIGNAL ;
  PORT
   LAYER M5 ;
   RECT 106.224000 0.000000 106.248000 0.084000 ;
  END
 END tw_data[201]
 PIN tw_data[202]
  DIRECTION INPUT ;
  USE SIGNAL ;
  PORT
   LAYER M5 ;
   RECT 106.416000 0.000000 106.440000 0.084000 ;
  END
 END tw_data[202]
 PIN tw_data[203]
  DIRECTION INPUT ;
  USE SIGNAL ;
  PORT
   LAYER M5 ;
   RECT 106.608000 0.000000 106.632000 0.084000 ;
  END
 END tw_data[203]
 PIN tw_data[204]
  DIRECTION INPUT ;
  USE SIGNAL ;
  PORT
   LAYER M5 ;
   RECT 106.800000 0.000000 106.824000 0.084000 ;
  END
 END tw_data[204]
 PIN tw_data[205]
  DIRECTION INPUT ;
  USE SIGNAL ;
  PORT
   LAYER M5 ;
   RECT 106.992000 0.000000 107.016000 0.084000 ;
  END
 END tw_data[205]
 PIN tw_data[206]
  DIRECTION INPUT ;
  USE SIGNAL ;
  PORT
   LAYER M5 ;
   RECT 107.184000 0.000000 107.208000 0.084000 ;
  END
 END tw_data[206]
 PIN tw_data[207]
  DIRECTION INPUT ;
  USE SIGNAL ;
  PORT
   LAYER M5 ;
   RECT 107.376000 0.000000 107.400000 0.084000 ;
  END
 END tw_data[207]
 PIN tw_data[208]
  DIRECTION INPUT ;
  USE SIGNAL ;
  PORT
   LAYER M5 ;
   RECT 107.568000 0.000000 107.592000 0.084000 ;
  END
 END tw_data[208]
 PIN tw_data[209]
  DIRECTION INPUT ;
  USE SIGNAL ;
  PORT
   LAYER M5 ;
   RECT 107.760000 0.000000 107.784000 0.084000 ;
  END
 END tw_data[209]
 PIN tw_data[210]
  DIRECTION INPUT ;
  USE SIGNAL ;
  PORT
   LAYER M5 ;
   RECT 107.952000 0.000000 107.976000 0.084000 ;
  END
 END tw_data[210]
 PIN tw_data[211]
  DIRECTION INPUT ;
  USE SIGNAL ;
  PORT
   LAYER M5 ;
   RECT 108.144000 0.000000 108.168000 0.084000 ;
  END
 END tw_data[211]
 PIN tw_data[212]
  DIRECTION INPUT ;
  USE SIGNAL ;
  PORT
   LAYER M5 ;
   RECT 108.336000 0.000000 108.360000 0.084000 ;
  END
 END tw_data[212]
 PIN tw_data[213]
  DIRECTION INPUT ;
  USE SIGNAL ;
  PORT
   LAYER M5 ;
   RECT 108.528000 0.000000 108.552000 0.084000 ;
  END
 END tw_data[213]
 PIN tw_data[214]
  DIRECTION INPUT ;
  USE SIGNAL ;
  PORT
   LAYER M5 ;
   RECT 108.720000 0.000000 108.744000 0.084000 ;
  END
 END tw_data[214]
 PIN tw_data[215]
  DIRECTION INPUT ;
  USE SIGNAL ;
  PORT
   LAYER M5 ;
   RECT 108.912000 0.000000 108.936000 0.084000 ;
  END
 END tw_data[215]
 PIN tw_data[216]
  DIRECTION INPUT ;
  USE SIGNAL ;
  PORT
   LAYER M5 ;
   RECT 109.104000 0.000000 109.128000 0.084000 ;
  END
 END tw_data[216]
 PIN tw_data[217]
  DIRECTION INPUT ;
  USE SIGNAL ;
  PORT
   LAYER M5 ;
   RECT 109.296000 0.000000 109.320000 0.084000 ;
  END
 END tw_data[217]
 PIN tw_data[218]
  DIRECTION INPUT ;
  USE SIGNAL ;
  PORT
   LAYER M5 ;
   RECT 109.488000 0.000000 109.512000 0.084000 ;
  END
 END tw_data[218]
 PIN tw_data[219]
  DIRECTION INPUT ;
  USE SIGNAL ;
  PORT
   LAYER M5 ;
   RECT 109.680000 0.000000 109.704000 0.084000 ;
  END
 END tw_data[219]
 PIN tw_data[220]
  DIRECTION INPUT ;
  USE SIGNAL ;
  PORT
   LAYER M5 ;
   RECT 109.872000 0.000000 109.896000 0.084000 ;
  END
 END tw_data[220]
 PIN tw_data[221]
  DIRECTION INPUT ;
  USE SIGNAL ;
  PORT
   LAYER M5 ;
   RECT 110.352000 0.000000 110.376000 0.084000 ;
  END
 END tw_data[221]
 PIN tw_data[222]
  DIRECTION INPUT ;
  USE SIGNAL ;
  PORT
   LAYER M5 ;
   RECT 110.544000 0.000000 110.568000 0.084000 ;
  END
 END tw_data[222]
 PIN tw_data[223]
  DIRECTION INPUT ;
  USE SIGNAL ;
  PORT
   LAYER M5 ;
   RECT 110.736000 0.000000 110.760000 0.084000 ;
  END
 END tw_data[223]
 PIN tw_data[224]
  DIRECTION INPUT ;
  USE SIGNAL ;
  PORT
   LAYER M5 ;
   RECT 110.928000 0.000000 110.952000 0.084000 ;
  END
 END tw_data[224]
 PIN tw_data[225]
  DIRECTION INPUT ;
  USE SIGNAL ;
  PORT
   LAYER M5 ;
   RECT 111.120000 0.000000 111.144000 0.084000 ;
  END
 END tw_data[225]
 PIN tw_data[226]
  DIRECTION INPUT ;
  USE SIGNAL ;
  PORT
   LAYER M5 ;
   RECT 111.312000 0.000000 111.336000 0.084000 ;
  END
 END tw_data[226]
 PIN tw_data[227]
  DIRECTION INPUT ;
  USE SIGNAL ;
  PORT
   LAYER M5 ;
   RECT 111.504000 0.000000 111.528000 0.084000 ;
  END
 END tw_data[227]
 PIN tw_data[228]
  DIRECTION INPUT ;
  USE SIGNAL ;
  PORT
   LAYER M5 ;
   RECT 111.696000 0.000000 111.720000 0.084000 ;
  END
 END tw_data[228]
 PIN tw_data[229]
  DIRECTION INPUT ;
  USE SIGNAL ;
  PORT
   LAYER M5 ;
   RECT 111.888000 0.000000 111.912000 0.084000 ;
  END
 END tw_data[229]
 PIN tw_data[230]
  DIRECTION INPUT ;
  USE SIGNAL ;
  PORT
   LAYER M5 ;
   RECT 112.080000 0.000000 112.104000 0.084000 ;
  END
 END tw_data[230]
 PIN tw_data[231]
  DIRECTION INPUT ;
  USE SIGNAL ;
  PORT
   LAYER M5 ;
   RECT 112.272000 0.000000 112.296000 0.084000 ;
  END
 END tw_data[231]
 PIN tw_data[232]
  DIRECTION INPUT ;
  USE SIGNAL ;
  PORT
   LAYER M5 ;
   RECT 112.464000 0.000000 112.488000 0.084000 ;
  END
 END tw_data[232]
 PIN tw_data[233]
  DIRECTION INPUT ;
  USE SIGNAL ;
  PORT
   LAYER M5 ;
   RECT 112.656000 0.000000 112.680000 0.084000 ;
  END
 END tw_data[233]
 PIN tw_data[234]
  DIRECTION INPUT ;
  USE SIGNAL ;
  PORT
   LAYER M5 ;
   RECT 112.848000 0.000000 112.872000 0.084000 ;
  END
 END tw_data[234]
 PIN tw_data[235]
  DIRECTION INPUT ;
  USE SIGNAL ;
  PORT
   LAYER M5 ;
   RECT 113.040000 0.000000 113.064000 0.084000 ;
  END
 END tw_data[235]
 PIN tw_data[236]
  DIRECTION INPUT ;
  USE SIGNAL ;
  PORT
   LAYER M5 ;
   RECT 113.232000 0.000000 113.256000 0.084000 ;
  END
 END tw_data[236]
 PIN tw_data[237]
  DIRECTION INPUT ;
  USE SIGNAL ;
  PORT
   LAYER M5 ;
   RECT 113.424000 0.000000 113.448000 0.084000 ;
  END
 END tw_data[237]
 PIN tw_data[238]
  DIRECTION INPUT ;
  USE SIGNAL ;
  PORT
   LAYER M5 ;
   RECT 113.616000 0.000000 113.640000 0.084000 ;
  END
 END tw_data[238]
 PIN tw_data[239]
  DIRECTION INPUT ;
  USE SIGNAL ;
  PORT
   LAYER M5 ;
   RECT 113.808000 0.000000 113.832000 0.084000 ;
  END
 END tw_data[239]
 PIN tw_data[240]
  DIRECTION INPUT ;
  USE SIGNAL ;
  PORT
   LAYER M5 ;
   RECT 114.000000 0.000000 114.024000 0.084000 ;
  END
 END tw_data[240]
 PIN tw_data[241]
  DIRECTION INPUT ;
  USE SIGNAL ;
  PORT
   LAYER M5 ;
   RECT 114.192000 0.000000 114.216000 0.084000 ;
  END
 END tw_data[241]
 PIN tw_data[242]
  DIRECTION INPUT ;
  USE SIGNAL ;
  PORT
   LAYER M5 ;
   RECT 114.672000 0.000000 114.696000 0.084000 ;
  END
 END tw_data[242]
 PIN tw_data[243]
  DIRECTION INPUT ;
  USE SIGNAL ;
  PORT
   LAYER M5 ;
   RECT 114.864000 0.000000 114.888000 0.084000 ;
  END
 END tw_data[243]
 PIN tw_data[244]
  DIRECTION INPUT ;
  USE SIGNAL ;
  PORT
   LAYER M5 ;
   RECT 115.056000 0.000000 115.080000 0.084000 ;
  END
 END tw_data[244]
 PIN tw_data[245]
  DIRECTION INPUT ;
  USE SIGNAL ;
  PORT
   LAYER M5 ;
   RECT 115.248000 0.000000 115.272000 0.084000 ;
  END
 END tw_data[245]
 PIN tw_data[246]
  DIRECTION INPUT ;
  USE SIGNAL ;
  PORT
   LAYER M5 ;
   RECT 115.440000 0.000000 115.464000 0.084000 ;
  END
 END tw_data[246]
 PIN tw_data[247]
  DIRECTION INPUT ;
  USE SIGNAL ;
  PORT
   LAYER M5 ;
   RECT 115.632000 0.000000 115.656000 0.084000 ;
  END
 END tw_data[247]
 PIN tw_data[248]
  DIRECTION INPUT ;
  USE SIGNAL ;
  PORT
   LAYER M5 ;
   RECT 115.824000 0.000000 115.848000 0.084000 ;
  END
 END tw_data[248]
 PIN tw_data[249]
  DIRECTION INPUT ;
  USE SIGNAL ;
  PORT
   LAYER M5 ;
   RECT 116.016000 0.000000 116.040000 0.084000 ;
  END
 END tw_data[249]
 PIN tw_data[250]
  DIRECTION INPUT ;
  USE SIGNAL ;
  PORT
   LAYER M5 ;
   RECT 116.208000 0.000000 116.232000 0.084000 ;
  END
 END tw_data[250]
 PIN tw_data[251]
  DIRECTION INPUT ;
  USE SIGNAL ;
  PORT
   LAYER M5 ;
   RECT 116.400000 0.000000 116.424000 0.084000 ;
  END
 END tw_data[251]
 PIN tw_data[252]
  DIRECTION INPUT ;
  USE SIGNAL ;
  PORT
   LAYER M5 ;
   RECT 116.592000 0.000000 116.616000 0.084000 ;
  END
 END tw_data[252]
 PIN tw_data[253]
  DIRECTION INPUT ;
  USE SIGNAL ;
  PORT
   LAYER M5 ;
   RECT 116.784000 0.000000 116.808000 0.084000 ;
  END
 END tw_data[253]
 PIN tw_data[254]
  DIRECTION INPUT ;
  USE SIGNAL ;
  PORT
   LAYER M5 ;
   RECT 116.976000 0.000000 117.000000 0.084000 ;
  END
 END tw_data[254]
 PIN tw_data[255]
  DIRECTION INPUT ;
  USE SIGNAL ;
  PORT
   LAYER M5 ;
   RECT 117.168000 0.000000 117.192000 0.084000 ;
  END
 END tw_data[255]
 PIN tw_data[256]
  DIRECTION INPUT ;
  USE SIGNAL ;
  PORT
   LAYER M5 ;
   RECT 117.360000 0.000000 117.384000 0.084000 ;
  END
 END tw_data[256]
 PIN tw_data[257]
  DIRECTION INPUT ;
  USE SIGNAL ;
  PORT
   LAYER M5 ;
   RECT 117.552000 0.000000 117.576000 0.084000 ;
  END
 END tw_data[257]
 PIN tw_data[258]
  DIRECTION INPUT ;
  USE SIGNAL ;
  PORT
   LAYER M5 ;
   RECT 117.744000 0.000000 117.768000 0.084000 ;
  END
 END tw_data[258]
 PIN tw_data[259]
  DIRECTION INPUT ;
  USE SIGNAL ;
  PORT
   LAYER M5 ;
   RECT 117.936000 0.000000 117.960000 0.084000 ;
  END
 END tw_data[259]
 PIN tw_data[260]
  DIRECTION INPUT ;
  USE SIGNAL ;
  PORT
   LAYER M5 ;
   RECT 118.128000 0.000000 118.152000 0.084000 ;
  END
 END tw_data[260]
 PIN tw_data[261]
  DIRECTION INPUT ;
  USE SIGNAL ;
  PORT
   LAYER M5 ;
   RECT 118.320000 0.000000 118.344000 0.084000 ;
  END
 END tw_data[261]
 PIN tw_data[262]
  DIRECTION INPUT ;
  USE SIGNAL ;
  PORT
   LAYER M5 ;
   RECT 118.512000 0.000000 118.536000 0.084000 ;
  END
 END tw_data[262]
 PIN tw_data[263]
  DIRECTION INPUT ;
  USE SIGNAL ;
  PORT
   LAYER M5 ;
   RECT 118.992000 0.000000 119.016000 0.084000 ;
  END
 END tw_data[263]
 PIN tw_data[264]
  DIRECTION INPUT ;
  USE SIGNAL ;
  PORT
   LAYER M5 ;
   RECT 119.184000 0.000000 119.208000 0.084000 ;
  END
 END tw_data[264]
 PIN tw_data[265]
  DIRECTION INPUT ;
  USE SIGNAL ;
  PORT
   LAYER M5 ;
   RECT 119.376000 0.000000 119.400000 0.084000 ;
  END
 END tw_data[265]
 PIN tw_data[266]
  DIRECTION INPUT ;
  USE SIGNAL ;
  PORT
   LAYER M5 ;
   RECT 119.568000 0.000000 119.592000 0.084000 ;
  END
 END tw_data[266]
 PIN tw_data[267]
  DIRECTION INPUT ;
  USE SIGNAL ;
  PORT
   LAYER M5 ;
   RECT 119.760000 0.000000 119.784000 0.084000 ;
  END
 END tw_data[267]
 PIN tw_data[268]
  DIRECTION INPUT ;
  USE SIGNAL ;
  PORT
   LAYER M5 ;
   RECT 119.952000 0.000000 119.976000 0.084000 ;
  END
 END tw_data[268]
 PIN tw_data[269]
  DIRECTION INPUT ;
  USE SIGNAL ;
  PORT
   LAYER M5 ;
   RECT 120.144000 0.000000 120.168000 0.084000 ;
  END
 END tw_data[269]
 PIN tw_data[270]
  DIRECTION INPUT ;
  USE SIGNAL ;
  PORT
   LAYER M5 ;
   RECT 120.336000 0.000000 120.360000 0.084000 ;
  END
 END tw_data[270]
 PIN tw_data[271]
  DIRECTION INPUT ;
  USE SIGNAL ;
  PORT
   LAYER M5 ;
   RECT 120.528000 0.000000 120.552000 0.084000 ;
  END
 END tw_data[271]
 PIN tw_data[272]
  DIRECTION INPUT ;
  USE SIGNAL ;
  PORT
   LAYER M5 ;
   RECT 120.720000 0.000000 120.744000 0.084000 ;
  END
 END tw_data[272]
 PIN tw_data[273]
  DIRECTION INPUT ;
  USE SIGNAL ;
  PORT
   LAYER M5 ;
   RECT 120.912000 0.000000 120.936000 0.084000 ;
  END
 END tw_data[273]
 PIN tw_data[274]
  DIRECTION INPUT ;
  USE SIGNAL ;
  PORT
   LAYER M5 ;
   RECT 121.104000 0.000000 121.128000 0.084000 ;
  END
 END tw_data[274]
 PIN tw_data[275]
  DIRECTION INPUT ;
  USE SIGNAL ;
  PORT
   LAYER M5 ;
   RECT 121.296000 0.000000 121.320000 0.084000 ;
  END
 END tw_data[275]
 PIN tw_data[276]
  DIRECTION INPUT ;
  USE SIGNAL ;
  PORT
   LAYER M5 ;
   RECT 121.488000 0.000000 121.512000 0.084000 ;
  END
 END tw_data[276]
 PIN tw_data[277]
  DIRECTION INPUT ;
  USE SIGNAL ;
  PORT
   LAYER M5 ;
   RECT 121.680000 0.000000 121.704000 0.084000 ;
  END
 END tw_data[277]
 PIN tw_data[278]
  DIRECTION INPUT ;
  USE SIGNAL ;
  PORT
   LAYER M5 ;
   RECT 121.872000 0.000000 121.896000 0.084000 ;
  END
 END tw_data[278]
 PIN tw_data[279]
  DIRECTION INPUT ;
  USE SIGNAL ;
  PORT
   LAYER M5 ;
   RECT 122.064000 0.000000 122.088000 0.084000 ;
  END
 END tw_data[279]
 PIN tw_data[280]
  DIRECTION INPUT ;
  USE SIGNAL ;
  PORT
   LAYER M5 ;
   RECT 122.256000 0.000000 122.280000 0.084000 ;
  END
 END tw_data[280]
 PIN tw_data[281]
  DIRECTION INPUT ;
  USE SIGNAL ;
  PORT
   LAYER M5 ;
   RECT 122.448000 0.000000 122.472000 0.084000 ;
  END
 END tw_data[281]
 PIN tw_data[282]
  DIRECTION INPUT ;
  USE SIGNAL ;
  PORT
   LAYER M5 ;
   RECT 122.640000 0.000000 122.664000 0.084000 ;
  END
 END tw_data[282]
 PIN tw_data[283]
  DIRECTION INPUT ;
  USE SIGNAL ;
  PORT
   LAYER M5 ;
   RECT 122.832000 0.000000 122.856000 0.084000 ;
  END
 END tw_data[283]
 PIN tw_data[284]
  DIRECTION INPUT ;
  USE SIGNAL ;
  PORT
   LAYER M5 ;
   RECT 123.312000 0.000000 123.336000 0.084000 ;
  END
 END tw_data[284]
 PIN tw_data[285]
  DIRECTION INPUT ;
  USE SIGNAL ;
  PORT
   LAYER M5 ;
   RECT 123.504000 0.000000 123.528000 0.084000 ;
  END
 END tw_data[285]
 PIN tw_data[286]
  DIRECTION INPUT ;
  USE SIGNAL ;
  PORT
   LAYER M5 ;
   RECT 123.696000 0.000000 123.720000 0.084000 ;
  END
 END tw_data[286]
 PIN tw_data[287]
  DIRECTION INPUT ;
  USE SIGNAL ;
  PORT
   LAYER M5 ;
   RECT 123.888000 0.000000 123.912000 0.084000 ;
  END
 END tw_data[287]
 PIN tw_data[288]
  DIRECTION INPUT ;
  USE SIGNAL ;
  PORT
   LAYER M5 ;
   RECT 124.080000 0.000000 124.104000 0.084000 ;
  END
 END tw_data[288]
 PIN tw_data[289]
  DIRECTION INPUT ;
  USE SIGNAL ;
  PORT
   LAYER M5 ;
   RECT 124.272000 0.000000 124.296000 0.084000 ;
  END
 END tw_data[289]
 PIN tw_data[290]
  DIRECTION INPUT ;
  USE SIGNAL ;
  PORT
   LAYER M5 ;
   RECT 124.464000 0.000000 124.488000 0.084000 ;
  END
 END tw_data[290]
 PIN tw_data[291]
  DIRECTION INPUT ;
  USE SIGNAL ;
  PORT
   LAYER M5 ;
   RECT 124.656000 0.000000 124.680000 0.084000 ;
  END
 END tw_data[291]
 PIN tw_data[292]
  DIRECTION INPUT ;
  USE SIGNAL ;
  PORT
   LAYER M5 ;
   RECT 124.848000 0.000000 124.872000 0.084000 ;
  END
 END tw_data[292]
 PIN tw_data[293]
  DIRECTION INPUT ;
  USE SIGNAL ;
  PORT
   LAYER M5 ;
   RECT 125.040000 0.000000 125.064000 0.084000 ;
  END
 END tw_data[293]
 PIN tw_data[294]
  DIRECTION INPUT ;
  USE SIGNAL ;
  PORT
   LAYER M5 ;
   RECT 125.232000 0.000000 125.256000 0.084000 ;
  END
 END tw_data[294]
 PIN tw_data[295]
  DIRECTION INPUT ;
  USE SIGNAL ;
  PORT
   LAYER M5 ;
   RECT 125.424000 0.000000 125.448000 0.084000 ;
  END
 END tw_data[295]
 PIN tw_data[296]
  DIRECTION INPUT ;
  USE SIGNAL ;
  PORT
   LAYER M5 ;
   RECT 125.616000 0.000000 125.640000 0.084000 ;
  END
 END tw_data[296]
 PIN tw_data[297]
  DIRECTION INPUT ;
  USE SIGNAL ;
  PORT
   LAYER M5 ;
   RECT 125.808000 0.000000 125.832000 0.084000 ;
  END
 END tw_data[297]
 PIN tw_data[298]
  DIRECTION INPUT ;
  USE SIGNAL ;
  PORT
   LAYER M5 ;
   RECT 126.000000 0.000000 126.024000 0.084000 ;
  END
 END tw_data[298]
 PIN tw_data[299]
  DIRECTION INPUT ;
  USE SIGNAL ;
  PORT
   LAYER M5 ;
   RECT 126.192000 0.000000 126.216000 0.084000 ;
  END
 END tw_data[299]
 PIN tw_data[300]
  DIRECTION INPUT ;
  USE SIGNAL ;
  PORT
   LAYER M5 ;
   RECT 126.384000 0.000000 126.408000 0.084000 ;
  END
 END tw_data[300]
 PIN tw_data[301]
  DIRECTION INPUT ;
  USE SIGNAL ;
  PORT
   LAYER M5 ;
   RECT 126.576000 0.000000 126.600000 0.084000 ;
  END
 END tw_data[301]
 PIN tw_data[302]
  DIRECTION INPUT ;
  USE SIGNAL ;
  PORT
   LAYER M5 ;
   RECT 126.768000 0.000000 126.792000 0.084000 ;
  END
 END tw_data[302]
 PIN tw_data[303]
  DIRECTION INPUT ;
  USE SIGNAL ;
  PORT
   LAYER M5 ;
   RECT 126.960000 0.000000 126.984000 0.084000 ;
  END
 END tw_data[303]
 PIN tw_data[304]
  DIRECTION INPUT ;
  USE SIGNAL ;
  PORT
   LAYER M5 ;
   RECT 127.152000 0.000000 127.176000 0.084000 ;
  END
 END tw_data[304]
 PIN tw_data[305]
  DIRECTION INPUT ;
  USE SIGNAL ;
  PORT
   LAYER M5 ;
   RECT 127.632000 0.000000 127.656000 0.084000 ;
  END
 END tw_data[305]
 PIN tw_data[306]
  DIRECTION INPUT ;
  USE SIGNAL ;
  PORT
   LAYER M5 ;
   RECT 127.824000 0.000000 127.848000 0.084000 ;
  END
 END tw_data[306]
 PIN tw_data[307]
  DIRECTION INPUT ;
  USE SIGNAL ;
  PORT
   LAYER M5 ;
   RECT 128.016000 0.000000 128.040000 0.084000 ;
  END
 END tw_data[307]
 PIN tw_data[308]
  DIRECTION INPUT ;
  USE SIGNAL ;
  PORT
   LAYER M5 ;
   RECT 128.208000 0.000000 128.232000 0.084000 ;
  END
 END tw_data[308]
 PIN tw_data[309]
  DIRECTION INPUT ;
  USE SIGNAL ;
  PORT
   LAYER M5 ;
   RECT 128.400000 0.000000 128.424000 0.084000 ;
  END
 END tw_data[309]
 PIN tw_data[310]
  DIRECTION INPUT ;
  USE SIGNAL ;
  PORT
   LAYER M5 ;
   RECT 128.592000 0.000000 128.616000 0.084000 ;
  END
 END tw_data[310]
 PIN tw_data[311]
  DIRECTION INPUT ;
  USE SIGNAL ;
  PORT
   LAYER M5 ;
   RECT 128.784000 0.000000 128.808000 0.084000 ;
  END
 END tw_data[311]
 PIN tw_data[312]
  DIRECTION INPUT ;
  USE SIGNAL ;
  PORT
   LAYER M5 ;
   RECT 128.976000 0.000000 129.000000 0.084000 ;
  END
 END tw_data[312]
 PIN tw_data[313]
  DIRECTION INPUT ;
  USE SIGNAL ;
  PORT
   LAYER M5 ;
   RECT 129.168000 0.000000 129.192000 0.084000 ;
  END
 END tw_data[313]
 PIN tw_data[314]
  DIRECTION INPUT ;
  USE SIGNAL ;
  PORT
   LAYER M5 ;
   RECT 129.360000 0.000000 129.384000 0.084000 ;
  END
 END tw_data[314]
 PIN tw_data[315]
  DIRECTION INPUT ;
  USE SIGNAL ;
  PORT
   LAYER M5 ;
   RECT 129.552000 0.000000 129.576000 0.084000 ;
  END
 END tw_data[315]
 PIN tw_data[316]
  DIRECTION INPUT ;
  USE SIGNAL ;
  PORT
   LAYER M5 ;
   RECT 129.744000 0.000000 129.768000 0.084000 ;
  END
 END tw_data[316]
 PIN tw_data[317]
  DIRECTION INPUT ;
  USE SIGNAL ;
  PORT
   LAYER M5 ;
   RECT 129.936000 0.000000 129.960000 0.084000 ;
  END
 END tw_data[317]
 PIN tw_data[318]
  DIRECTION INPUT ;
  USE SIGNAL ;
  PORT
   LAYER M5 ;
   RECT 130.128000 0.000000 130.152000 0.084000 ;
  END
 END tw_data[318]
 PIN tw_data[319]
  DIRECTION INPUT ;
  USE SIGNAL ;
  PORT
   LAYER M5 ;
   RECT 130.320000 0.000000 130.344000 0.084000 ;
  END
 END tw_data[319]
 PIN tw_data[320]
  DIRECTION INPUT ;
  USE SIGNAL ;
  PORT
   LAYER M5 ;
   RECT 130.512000 0.000000 130.536000 0.084000 ;
  END
 END tw_data[320]
 PIN tw_data[321]
  DIRECTION INPUT ;
  USE SIGNAL ;
  PORT
   LAYER M5 ;
   RECT 130.704000 0.000000 130.728000 0.084000 ;
  END
 END tw_data[321]
 PIN tw_data[322]
  DIRECTION INPUT ;
  USE SIGNAL ;
  PORT
   LAYER M5 ;
   RECT 130.896000 0.000000 130.920000 0.084000 ;
  END
 END tw_data[322]
 PIN tw_data[323]
  DIRECTION INPUT ;
  USE SIGNAL ;
  PORT
   LAYER M5 ;
   RECT 131.088000 0.000000 131.112000 0.084000 ;
  END
 END tw_data[323]
 PIN tw_data[324]
  DIRECTION INPUT ;
  USE SIGNAL ;
  PORT
   LAYER M5 ;
   RECT 131.280000 0.000000 131.304000 0.084000 ;
  END
 END tw_data[324]
 PIN tw_data[325]
  DIRECTION INPUT ;
  USE SIGNAL ;
  PORT
   LAYER M5 ;
   RECT 131.472000 0.000000 131.496000 0.084000 ;
  END
 END tw_data[325]
 PIN tw_data[326]
  DIRECTION INPUT ;
  USE SIGNAL ;
  PORT
   LAYER M5 ;
   RECT 131.952000 0.000000 131.976000 0.084000 ;
  END
 END tw_data[326]
 PIN tw_data[327]
  DIRECTION INPUT ;
  USE SIGNAL ;
  PORT
   LAYER M5 ;
   RECT 132.144000 0.000000 132.168000 0.084000 ;
  END
 END tw_data[327]
 PIN tw_data[328]
  DIRECTION INPUT ;
  USE SIGNAL ;
  PORT
   LAYER M5 ;
   RECT 132.336000 0.000000 132.360000 0.084000 ;
  END
 END tw_data[328]
 PIN tw_data[329]
  DIRECTION INPUT ;
  USE SIGNAL ;
  PORT
   LAYER M5 ;
   RECT 132.528000 0.000000 132.552000 0.084000 ;
  END
 END tw_data[329]
 PIN tw_data[330]
  DIRECTION INPUT ;
  USE SIGNAL ;
  PORT
   LAYER M5 ;
   RECT 132.720000 0.000000 132.744000 0.084000 ;
  END
 END tw_data[330]
 PIN tw_data[331]
  DIRECTION INPUT ;
  USE SIGNAL ;
  PORT
   LAYER M5 ;
   RECT 132.912000 0.000000 132.936000 0.084000 ;
  END
 END tw_data[331]
 PIN tw_data[332]
  DIRECTION INPUT ;
  USE SIGNAL ;
  PORT
   LAYER M5 ;
   RECT 133.104000 0.000000 133.128000 0.084000 ;
  END
 END tw_data[332]
 PIN tw_data[333]
  DIRECTION INPUT ;
  USE SIGNAL ;
  PORT
   LAYER M5 ;
   RECT 133.296000 0.000000 133.320000 0.084000 ;
  END
 END tw_data[333]
 PIN tw_data[334]
  DIRECTION INPUT ;
  USE SIGNAL ;
  PORT
   LAYER M5 ;
   RECT 133.488000 0.000000 133.512000 0.084000 ;
  END
 END tw_data[334]
 PIN tw_data[335]
  DIRECTION INPUT ;
  USE SIGNAL ;
  PORT
   LAYER M5 ;
   RECT 133.680000 0.000000 133.704000 0.084000 ;
  END
 END tw_data[335]
 PIN tw_data[336]
  DIRECTION INPUT ;
  USE SIGNAL ;
  PORT
   LAYER M5 ;
   RECT 133.872000 0.000000 133.896000 0.084000 ;
  END
 END tw_data[336]
 PIN tw_data[337]
  DIRECTION INPUT ;
  USE SIGNAL ;
  PORT
   LAYER M5 ;
   RECT 134.064000 0.000000 134.088000 0.084000 ;
  END
 END tw_data[337]
 PIN tw_data[338]
  DIRECTION INPUT ;
  USE SIGNAL ;
  PORT
   LAYER M5 ;
   RECT 134.256000 0.000000 134.280000 0.084000 ;
  END
 END tw_data[338]
 PIN tw_data[339]
  DIRECTION INPUT ;
  USE SIGNAL ;
  PORT
   LAYER M5 ;
   RECT 134.448000 0.000000 134.472000 0.084000 ;
  END
 END tw_data[339]
 PIN tw_data[340]
  DIRECTION INPUT ;
  USE SIGNAL ;
  PORT
   LAYER M5 ;
   RECT 134.640000 0.000000 134.664000 0.084000 ;
  END
 END tw_data[340]
 PIN tw_data[341]
  DIRECTION INPUT ;
  USE SIGNAL ;
  PORT
   LAYER M5 ;
   RECT 134.832000 0.000000 134.856000 0.084000 ;
  END
 END tw_data[341]
 PIN tw_data[342]
  DIRECTION INPUT ;
  USE SIGNAL ;
  PORT
   LAYER M5 ;
   RECT 135.024000 0.000000 135.048000 0.084000 ;
  END
 END tw_data[342]
 PIN tw_data[343]
  DIRECTION INPUT ;
  USE SIGNAL ;
  PORT
   LAYER M5 ;
   RECT 135.216000 0.000000 135.240000 0.084000 ;
  END
 END tw_data[343]
 PIN tw_data[344]
  DIRECTION INPUT ;
  USE SIGNAL ;
  PORT
   LAYER M5 ;
   RECT 135.408000 0.000000 135.432000 0.084000 ;
  END
 END tw_data[344]
 PIN tw_data[345]
  DIRECTION INPUT ;
  USE SIGNAL ;
  PORT
   LAYER M5 ;
   RECT 135.600000 0.000000 135.624000 0.084000 ;
  END
 END tw_data[345]
 PIN tw_data[346]
  DIRECTION INPUT ;
  USE SIGNAL ;
  PORT
   LAYER M5 ;
   RECT 135.792000 0.000000 135.816000 0.084000 ;
  END
 END tw_data[346]
 PIN tw_data[347]
  DIRECTION INPUT ;
  USE SIGNAL ;
  PORT
   LAYER M5 ;
   RECT 136.272000 0.000000 136.296000 0.084000 ;
  END
 END tw_data[347]
 PIN tw_data[348]
  DIRECTION INPUT ;
  USE SIGNAL ;
  PORT
   LAYER M5 ;
   RECT 136.464000 0.000000 136.488000 0.084000 ;
  END
 END tw_data[348]
 PIN tw_data[349]
  DIRECTION INPUT ;
  USE SIGNAL ;
  PORT
   LAYER M5 ;
   RECT 136.656000 0.000000 136.680000 0.084000 ;
  END
 END tw_data[349]
 PIN tw_data[350]
  DIRECTION INPUT ;
  USE SIGNAL ;
  PORT
   LAYER M5 ;
   RECT 136.848000 0.000000 136.872000 0.084000 ;
  END
 END tw_data[350]
 PIN tw_data[351]
  DIRECTION INPUT ;
  USE SIGNAL ;
  PORT
   LAYER M5 ;
   RECT 137.040000 0.000000 137.064000 0.084000 ;
  END
 END tw_data[351]
 PIN tw_data[352]
  DIRECTION INPUT ;
  USE SIGNAL ;
  PORT
   LAYER M5 ;
   RECT 137.232000 0.000000 137.256000 0.084000 ;
  END
 END tw_data[352]
 PIN tw_data[353]
  DIRECTION INPUT ;
  USE SIGNAL ;
  PORT
   LAYER M5 ;
   RECT 137.424000 0.000000 137.448000 0.084000 ;
  END
 END tw_data[353]
 PIN tw_data[354]
  DIRECTION INPUT ;
  USE SIGNAL ;
  PORT
   LAYER M5 ;
   RECT 137.616000 0.000000 137.640000 0.084000 ;
  END
 END tw_data[354]
 PIN tw_data[355]
  DIRECTION INPUT ;
  USE SIGNAL ;
  PORT
   LAYER M5 ;
   RECT 137.808000 0.000000 137.832000 0.084000 ;
  END
 END tw_data[355]
 PIN tw_data[356]
  DIRECTION INPUT ;
  USE SIGNAL ;
  PORT
   LAYER M5 ;
   RECT 138.000000 0.000000 138.024000 0.084000 ;
  END
 END tw_data[356]
 PIN tw_data[357]
  DIRECTION INPUT ;
  USE SIGNAL ;
  PORT
   LAYER M5 ;
   RECT 138.192000 0.000000 138.216000 0.084000 ;
  END
 END tw_data[357]
 PIN tw_data[358]
  DIRECTION INPUT ;
  USE SIGNAL ;
  PORT
   LAYER M5 ;
   RECT 138.384000 0.000000 138.408000 0.084000 ;
  END
 END tw_data[358]
 PIN tw_data[359]
  DIRECTION INPUT ;
  USE SIGNAL ;
  PORT
   LAYER M5 ;
   RECT 138.576000 0.000000 138.600000 0.084000 ;
  END
 END tw_data[359]
 PIN tw_data[360]
  DIRECTION INPUT ;
  USE SIGNAL ;
  PORT
   LAYER M5 ;
   RECT 138.768000 0.000000 138.792000 0.084000 ;
  END
 END tw_data[360]
 PIN tw_data[361]
  DIRECTION INPUT ;
  USE SIGNAL ;
  PORT
   LAYER M5 ;
   RECT 138.960000 0.000000 138.984000 0.084000 ;
  END
 END tw_data[361]
 PIN tw_data[362]
  DIRECTION INPUT ;
  USE SIGNAL ;
  PORT
   LAYER M5 ;
   RECT 139.152000 0.000000 139.176000 0.084000 ;
  END
 END tw_data[362]
 PIN tw_data[363]
  DIRECTION INPUT ;
  USE SIGNAL ;
  PORT
   LAYER M5 ;
   RECT 139.344000 0.000000 139.368000 0.084000 ;
  END
 END tw_data[363]
 PIN tw_data[364]
  DIRECTION INPUT ;
  USE SIGNAL ;
  PORT
   LAYER M5 ;
   RECT 139.536000 0.000000 139.560000 0.084000 ;
  END
 END tw_data[364]
 PIN tw_data[365]
  DIRECTION INPUT ;
  USE SIGNAL ;
  PORT
   LAYER M5 ;
   RECT 139.728000 0.000000 139.752000 0.084000 ;
  END
 END tw_data[365]
 PIN tw_data[366]
  DIRECTION INPUT ;
  USE SIGNAL ;
  PORT
   LAYER M5 ;
   RECT 139.920000 0.000000 139.944000 0.084000 ;
  END
 END tw_data[366]
 PIN tw_data[367]
  DIRECTION INPUT ;
  USE SIGNAL ;
  PORT
   LAYER M5 ;
   RECT 140.112000 0.000000 140.136000 0.084000 ;
  END
 END tw_data[367]
 PIN tw_data[368]
  DIRECTION INPUT ;
  USE SIGNAL ;
  PORT
   LAYER M5 ;
   RECT 140.592000 0.000000 140.616000 0.084000 ;
  END
 END tw_data[368]
 PIN tw_data[369]
  DIRECTION INPUT ;
  USE SIGNAL ;
  PORT
   LAYER M5 ;
   RECT 140.784000 0.000000 140.808000 0.084000 ;
  END
 END tw_data[369]
 PIN tw_data[370]
  DIRECTION INPUT ;
  USE SIGNAL ;
  PORT
   LAYER M5 ;
   RECT 140.976000 0.000000 141.000000 0.084000 ;
  END
 END tw_data[370]
 PIN tw_data[371]
  DIRECTION INPUT ;
  USE SIGNAL ;
  PORT
   LAYER M5 ;
   RECT 141.168000 0.000000 141.192000 0.084000 ;
  END
 END tw_data[371]
 PIN tw_data[372]
  DIRECTION INPUT ;
  USE SIGNAL ;
  PORT
   LAYER M5 ;
   RECT 141.360000 0.000000 141.384000 0.084000 ;
  END
 END tw_data[372]
 PIN tw_data[373]
  DIRECTION INPUT ;
  USE SIGNAL ;
  PORT
   LAYER M5 ;
   RECT 141.552000 0.000000 141.576000 0.084000 ;
  END
 END tw_data[373]
 PIN tw_data[374]
  DIRECTION INPUT ;
  USE SIGNAL ;
  PORT
   LAYER M5 ;
   RECT 141.744000 0.000000 141.768000 0.084000 ;
  END
 END tw_data[374]
 PIN tw_data[375]
  DIRECTION INPUT ;
  USE SIGNAL ;
  PORT
   LAYER M5 ;
   RECT 141.936000 0.000000 141.960000 0.084000 ;
  END
 END tw_data[375]
 PIN tw_data[376]
  DIRECTION INPUT ;
  USE SIGNAL ;
  PORT
   LAYER M5 ;
   RECT 142.128000 0.000000 142.152000 0.084000 ;
  END
 END tw_data[376]
 PIN tw_data[377]
  DIRECTION INPUT ;
  USE SIGNAL ;
  PORT
   LAYER M5 ;
   RECT 142.320000 0.000000 142.344000 0.084000 ;
  END
 END tw_data[377]
 PIN tw_data[378]
  DIRECTION INPUT ;
  USE SIGNAL ;
  PORT
   LAYER M5 ;
   RECT 142.512000 0.000000 142.536000 0.084000 ;
  END
 END tw_data[378]
 PIN tw_data[379]
  DIRECTION INPUT ;
  USE SIGNAL ;
  PORT
   LAYER M5 ;
   RECT 142.704000 0.000000 142.728000 0.084000 ;
  END
 END tw_data[379]
 PIN tw_data[380]
  DIRECTION INPUT ;
  USE SIGNAL ;
  PORT
   LAYER M5 ;
   RECT 142.896000 0.000000 142.920000 0.084000 ;
  END
 END tw_data[380]
 PIN tw_data[381]
  DIRECTION INPUT ;
  USE SIGNAL ;
  PORT
   LAYER M5 ;
   RECT 143.088000 0.000000 143.112000 0.084000 ;
  END
 END tw_data[381]
 PIN tw_data[382]
  DIRECTION INPUT ;
  USE SIGNAL ;
  PORT
   LAYER M5 ;
   RECT 143.280000 0.000000 143.304000 0.084000 ;
  END
 END tw_data[382]
 PIN tw_data[383]
  DIRECTION INPUT ;
  USE SIGNAL ;
  PORT
   LAYER M5 ;
   RECT 143.472000 0.000000 143.496000 0.084000 ;
  END
 END tw_data[383]
 PIN tw_data[384]
  DIRECTION INPUT ;
  USE SIGNAL ;
  PORT
   LAYER M5 ;
   RECT 143.664000 0.000000 143.688000 0.084000 ;
  END
 END tw_data[384]
 PIN tw_data[385]
  DIRECTION INPUT ;
  USE SIGNAL ;
  PORT
   LAYER M5 ;
   RECT 143.856000 0.000000 143.880000 0.084000 ;
  END
 END tw_data[385]
 PIN tw_data[386]
  DIRECTION INPUT ;
  USE SIGNAL ;
  PORT
   LAYER M5 ;
   RECT 144.048000 0.000000 144.072000 0.084000 ;
  END
 END tw_data[386]
 PIN tw_data[387]
  DIRECTION INPUT ;
  USE SIGNAL ;
  PORT
   LAYER M5 ;
   RECT 144.240000 0.000000 144.264000 0.084000 ;
  END
 END tw_data[387]
 PIN tw_data[388]
  DIRECTION INPUT ;
  USE SIGNAL ;
  PORT
   LAYER M5 ;
   RECT 144.432000 0.000000 144.456000 0.084000 ;
  END
 END tw_data[388]
 PIN tw_data[389]
  DIRECTION INPUT ;
  USE SIGNAL ;
  PORT
   LAYER M5 ;
   RECT 144.912000 0.000000 144.936000 0.084000 ;
  END
 END tw_data[389]
 PIN tw_data[390]
  DIRECTION INPUT ;
  USE SIGNAL ;
  PORT
   LAYER M5 ;
   RECT 145.104000 0.000000 145.128000 0.084000 ;
  END
 END tw_data[390]
 PIN tw_data[391]
  DIRECTION INPUT ;
  USE SIGNAL ;
  PORT
   LAYER M5 ;
   RECT 145.296000 0.000000 145.320000 0.084000 ;
  END
 END tw_data[391]
 PIN tw_data[392]
  DIRECTION INPUT ;
  USE SIGNAL ;
  PORT
   LAYER M5 ;
   RECT 145.488000 0.000000 145.512000 0.084000 ;
  END
 END tw_data[392]
 PIN tw_data[393]
  DIRECTION INPUT ;
  USE SIGNAL ;
  PORT
   LAYER M5 ;
   RECT 145.680000 0.000000 145.704000 0.084000 ;
  END
 END tw_data[393]
 PIN tw_data[394]
  DIRECTION INPUT ;
  USE SIGNAL ;
  PORT
   LAYER M5 ;
   RECT 145.872000 0.000000 145.896000 0.084000 ;
  END
 END tw_data[394]
 PIN tw_data[395]
  DIRECTION INPUT ;
  USE SIGNAL ;
  PORT
   LAYER M5 ;
   RECT 146.064000 0.000000 146.088000 0.084000 ;
  END
 END tw_data[395]
 PIN tw_data[396]
  DIRECTION INPUT ;
  USE SIGNAL ;
  PORT
   LAYER M5 ;
   RECT 146.256000 0.000000 146.280000 0.084000 ;
  END
 END tw_data[396]
 PIN tw_data[397]
  DIRECTION INPUT ;
  USE SIGNAL ;
  PORT
   LAYER M5 ;
   RECT 146.448000 0.000000 146.472000 0.084000 ;
  END
 END tw_data[397]
 PIN tw_data[398]
  DIRECTION INPUT ;
  USE SIGNAL ;
  PORT
   LAYER M5 ;
   RECT 146.640000 0.000000 146.664000 0.084000 ;
  END
 END tw_data[398]
 PIN tw_data[399]
  DIRECTION INPUT ;
  USE SIGNAL ;
  PORT
   LAYER M5 ;
   RECT 146.832000 0.000000 146.856000 0.084000 ;
  END
 END tw_data[399]
 PIN tw_data[400]
  DIRECTION INPUT ;
  USE SIGNAL ;
  PORT
   LAYER M5 ;
   RECT 147.024000 0.000000 147.048000 0.084000 ;
  END
 END tw_data[400]
 PIN tw_data[401]
  DIRECTION INPUT ;
  USE SIGNAL ;
  PORT
   LAYER M5 ;
   RECT 147.216000 0.000000 147.240000 0.084000 ;
  END
 END tw_data[401]
 PIN tw_data[402]
  DIRECTION INPUT ;
  USE SIGNAL ;
  PORT
   LAYER M5 ;
   RECT 147.408000 0.000000 147.432000 0.084000 ;
  END
 END tw_data[402]
 PIN tw_data[403]
  DIRECTION INPUT ;
  USE SIGNAL ;
  PORT
   LAYER M5 ;
   RECT 147.600000 0.000000 147.624000 0.084000 ;
  END
 END tw_data[403]
 PIN tw_data[404]
  DIRECTION INPUT ;
  USE SIGNAL ;
  PORT
   LAYER M5 ;
   RECT 147.792000 0.000000 147.816000 0.084000 ;
  END
 END tw_data[404]
 PIN tw_data[405]
  DIRECTION INPUT ;
  USE SIGNAL ;
  PORT
   LAYER M5 ;
   RECT 147.984000 0.000000 148.008000 0.084000 ;
  END
 END tw_data[405]
 PIN tw_data[406]
  DIRECTION INPUT ;
  USE SIGNAL ;
  PORT
   LAYER M5 ;
   RECT 148.176000 0.000000 148.200000 0.084000 ;
  END
 END tw_data[406]
 PIN tw_data[407]
  DIRECTION INPUT ;
  USE SIGNAL ;
  PORT
   LAYER M5 ;
   RECT 148.368000 0.000000 148.392000 0.084000 ;
  END
 END tw_data[407]
 PIN tw_data[408]
  DIRECTION INPUT ;
  USE SIGNAL ;
  PORT
   LAYER M5 ;
   RECT 148.560000 0.000000 148.584000 0.084000 ;
  END
 END tw_data[408]
 PIN tw_data[409]
  DIRECTION INPUT ;
  USE SIGNAL ;
  PORT
   LAYER M5 ;
   RECT 148.752000 0.000000 148.776000 0.084000 ;
  END
 END tw_data[409]
 PIN tw_data[410]
  DIRECTION INPUT ;
  USE SIGNAL ;
  PORT
   LAYER M5 ;
   RECT 149.232000 0.000000 149.256000 0.084000 ;
  END
 END tw_data[410]
 PIN tw_data[411]
  DIRECTION INPUT ;
  USE SIGNAL ;
  PORT
   LAYER M5 ;
   RECT 149.424000 0.000000 149.448000 0.084000 ;
  END
 END tw_data[411]
 PIN tw_data[412]
  DIRECTION INPUT ;
  USE SIGNAL ;
  PORT
   LAYER M5 ;
   RECT 149.616000 0.000000 149.640000 0.084000 ;
  END
 END tw_data[412]
 PIN tw_data[413]
  DIRECTION INPUT ;
  USE SIGNAL ;
  PORT
   LAYER M5 ;
   RECT 149.808000 0.000000 149.832000 0.084000 ;
  END
 END tw_data[413]
 PIN tw_data[414]
  DIRECTION INPUT ;
  USE SIGNAL ;
  PORT
   LAYER M5 ;
   RECT 150.000000 0.000000 150.024000 0.084000 ;
  END
 END tw_data[414]
 PIN tw_data[415]
  DIRECTION INPUT ;
  USE SIGNAL ;
  PORT
   LAYER M5 ;
   RECT 150.192000 0.000000 150.216000 0.084000 ;
  END
 END tw_data[415]
 PIN tw_data[416]
  DIRECTION INPUT ;
  USE SIGNAL ;
  PORT
   LAYER M5 ;
   RECT 150.384000 0.000000 150.408000 0.084000 ;
  END
 END tw_data[416]
 PIN tw_data[417]
  DIRECTION INPUT ;
  USE SIGNAL ;
  PORT
   LAYER M5 ;
   RECT 150.576000 0.000000 150.600000 0.084000 ;
  END
 END tw_data[417]
 PIN tw_data[418]
  DIRECTION INPUT ;
  USE SIGNAL ;
  PORT
   LAYER M5 ;
   RECT 150.768000 0.000000 150.792000 0.084000 ;
  END
 END tw_data[418]
 PIN tw_data[419]
  DIRECTION INPUT ;
  USE SIGNAL ;
  PORT
   LAYER M5 ;
   RECT 150.960000 0.000000 150.984000 0.084000 ;
  END
 END tw_data[419]
 PIN tw_data[420]
  DIRECTION INPUT ;
  USE SIGNAL ;
  PORT
   LAYER M5 ;
   RECT 151.152000 0.000000 151.176000 0.084000 ;
  END
 END tw_data[420]
 PIN tw_data[421]
  DIRECTION INPUT ;
  USE SIGNAL ;
  PORT
   LAYER M5 ;
   RECT 151.344000 0.000000 151.368000 0.084000 ;
  END
 END tw_data[421]
 PIN tw_data[422]
  DIRECTION INPUT ;
  USE SIGNAL ;
  PORT
   LAYER M5 ;
   RECT 151.536000 0.000000 151.560000 0.084000 ;
  END
 END tw_data[422]
 PIN tw_data[423]
  DIRECTION INPUT ;
  USE SIGNAL ;
  PORT
   LAYER M5 ;
   RECT 151.728000 0.000000 151.752000 0.084000 ;
  END
 END tw_data[423]
 PIN tw_data[424]
  DIRECTION INPUT ;
  USE SIGNAL ;
  PORT
   LAYER M5 ;
   RECT 151.920000 0.000000 151.944000 0.084000 ;
  END
 END tw_data[424]
 PIN tw_data[425]
  DIRECTION INPUT ;
  USE SIGNAL ;
  PORT
   LAYER M5 ;
   RECT 152.112000 0.000000 152.136000 0.084000 ;
  END
 END tw_data[425]
 PIN tw_data[426]
  DIRECTION INPUT ;
  USE SIGNAL ;
  PORT
   LAYER M5 ;
   RECT 152.304000 0.000000 152.328000 0.084000 ;
  END
 END tw_data[426]
 PIN tw_data[427]
  DIRECTION INPUT ;
  USE SIGNAL ;
  PORT
   LAYER M5 ;
   RECT 152.496000 0.000000 152.520000 0.084000 ;
  END
 END tw_data[427]
 PIN tw_data[428]
  DIRECTION INPUT ;
  USE SIGNAL ;
  PORT
   LAYER M5 ;
   RECT 152.688000 0.000000 152.712000 0.084000 ;
  END
 END tw_data[428]
 PIN tw_data[429]
  DIRECTION INPUT ;
  USE SIGNAL ;
  PORT
   LAYER M5 ;
   RECT 152.880000 0.000000 152.904000 0.084000 ;
  END
 END tw_data[429]
 PIN tw_data[430]
  DIRECTION INPUT ;
  USE SIGNAL ;
  PORT
   LAYER M5 ;
   RECT 153.072000 0.000000 153.096000 0.084000 ;
  END
 END tw_data[430]
 PIN tw_data[431]
  DIRECTION INPUT ;
  USE SIGNAL ;
  PORT
   LAYER M5 ;
   RECT 153.552000 0.000000 153.576000 0.084000 ;
  END
 END tw_data[431]
 PIN tw_data[432]
  DIRECTION INPUT ;
  USE SIGNAL ;
  PORT
   LAYER M5 ;
   RECT 153.744000 0.000000 153.768000 0.084000 ;
  END
 END tw_data[432]
 PIN tw_data[433]
  DIRECTION INPUT ;
  USE SIGNAL ;
  PORT
   LAYER M5 ;
   RECT 153.936000 0.000000 153.960000 0.084000 ;
  END
 END tw_data[433]
 PIN tw_data[434]
  DIRECTION INPUT ;
  USE SIGNAL ;
  PORT
   LAYER M5 ;
   RECT 154.128000 0.000000 154.152000 0.084000 ;
  END
 END tw_data[434]
 PIN tw_data[435]
  DIRECTION INPUT ;
  USE SIGNAL ;
  PORT
   LAYER M5 ;
   RECT 154.320000 0.000000 154.344000 0.084000 ;
  END
 END tw_data[435]
 PIN tw_data[436]
  DIRECTION INPUT ;
  USE SIGNAL ;
  PORT
   LAYER M5 ;
   RECT 154.512000 0.000000 154.536000 0.084000 ;
  END
 END tw_data[436]
 PIN tw_data[437]
  DIRECTION INPUT ;
  USE SIGNAL ;
  PORT
   LAYER M5 ;
   RECT 154.704000 0.000000 154.728000 0.084000 ;
  END
 END tw_data[437]
 PIN tw_data[438]
  DIRECTION INPUT ;
  USE SIGNAL ;
  PORT
   LAYER M5 ;
   RECT 154.896000 0.000000 154.920000 0.084000 ;
  END
 END tw_data[438]
 PIN tw_data[439]
  DIRECTION INPUT ;
  USE SIGNAL ;
  PORT
   LAYER M5 ;
   RECT 155.088000 0.000000 155.112000 0.084000 ;
  END
 END tw_data[439]
 PIN tw_data[440]
  DIRECTION INPUT ;
  USE SIGNAL ;
  PORT
   LAYER M5 ;
   RECT 155.280000 0.000000 155.304000 0.084000 ;
  END
 END tw_data[440]
 PIN tw_data[441]
  DIRECTION INPUT ;
  USE SIGNAL ;
  PORT
   LAYER M5 ;
   RECT 155.472000 0.000000 155.496000 0.084000 ;
  END
 END tw_data[441]
 PIN tw_data[442]
  DIRECTION INPUT ;
  USE SIGNAL ;
  PORT
   LAYER M5 ;
   RECT 155.664000 0.000000 155.688000 0.084000 ;
  END
 END tw_data[442]
 PIN tw_data[443]
  DIRECTION INPUT ;
  USE SIGNAL ;
  PORT
   LAYER M5 ;
   RECT 155.856000 0.000000 155.880000 0.084000 ;
  END
 END tw_data[443]
 PIN tw_data[444]
  DIRECTION INPUT ;
  USE SIGNAL ;
  PORT
   LAYER M5 ;
   RECT 156.048000 0.000000 156.072000 0.084000 ;
  END
 END tw_data[444]
 PIN tw_data[445]
  DIRECTION INPUT ;
  USE SIGNAL ;
  PORT
   LAYER M5 ;
   RECT 156.240000 0.000000 156.264000 0.084000 ;
  END
 END tw_data[445]
 PIN tw_data[446]
  DIRECTION INPUT ;
  USE SIGNAL ;
  PORT
   LAYER M5 ;
   RECT 156.432000 0.000000 156.456000 0.084000 ;
  END
 END tw_data[446]
 PIN tw_data[447]
  DIRECTION INPUT ;
  USE SIGNAL ;
  PORT
   LAYER M5 ;
   RECT 156.624000 0.000000 156.648000 0.084000 ;
  END
 END tw_data[447]
 PIN tw_data[448]
  DIRECTION INPUT ;
  USE SIGNAL ;
  PORT
   LAYER M5 ;
   RECT 156.816000 0.000000 156.840000 0.084000 ;
  END
 END tw_data[448]
 PIN tw_data[449]
  DIRECTION INPUT ;
  USE SIGNAL ;
  PORT
   LAYER M5 ;
   RECT 157.008000 0.000000 157.032000 0.084000 ;
  END
 END tw_data[449]
 PIN tw_data[450]
  DIRECTION INPUT ;
  USE SIGNAL ;
  PORT
   LAYER M5 ;
   RECT 157.200000 0.000000 157.224000 0.084000 ;
  END
 END tw_data[450]
 PIN tw_data[451]
  DIRECTION INPUT ;
  USE SIGNAL ;
  PORT
   LAYER M5 ;
   RECT 157.392000 0.000000 157.416000 0.084000 ;
  END
 END tw_data[451]
 PIN tw_data[452]
  DIRECTION INPUT ;
  USE SIGNAL ;
  PORT
   LAYER M5 ;
   RECT 157.872000 0.000000 157.896000 0.084000 ;
  END
 END tw_data[452]
 PIN tw_data[453]
  DIRECTION INPUT ;
  USE SIGNAL ;
  PORT
   LAYER M5 ;
   RECT 158.064000 0.000000 158.088000 0.084000 ;
  END
 END tw_data[453]
 PIN tw_data[454]
  DIRECTION INPUT ;
  USE SIGNAL ;
  PORT
   LAYER M5 ;
   RECT 158.256000 0.000000 158.280000 0.084000 ;
  END
 END tw_data[454]
 PIN tw_data[455]
  DIRECTION INPUT ;
  USE SIGNAL ;
  PORT
   LAYER M5 ;
   RECT 158.448000 0.000000 158.472000 0.084000 ;
  END
 END tw_data[455]
 PIN tw_data[456]
  DIRECTION INPUT ;
  USE SIGNAL ;
  PORT
   LAYER M5 ;
   RECT 158.640000 0.000000 158.664000 0.084000 ;
  END
 END tw_data[456]
 PIN tw_data[457]
  DIRECTION INPUT ;
  USE SIGNAL ;
  PORT
   LAYER M5 ;
   RECT 158.832000 0.000000 158.856000 0.084000 ;
  END
 END tw_data[457]
 PIN tw_data[458]
  DIRECTION INPUT ;
  USE SIGNAL ;
  PORT
   LAYER M5 ;
   RECT 159.024000 0.000000 159.048000 0.084000 ;
  END
 END tw_data[458]
 PIN tw_data[459]
  DIRECTION INPUT ;
  USE SIGNAL ;
  PORT
   LAYER M5 ;
   RECT 159.216000 0.000000 159.240000 0.084000 ;
  END
 END tw_data[459]
 PIN tw_data[460]
  DIRECTION INPUT ;
  USE SIGNAL ;
  PORT
   LAYER M5 ;
   RECT 159.408000 0.000000 159.432000 0.084000 ;
  END
 END tw_data[460]
 PIN tw_data[461]
  DIRECTION INPUT ;
  USE SIGNAL ;
  PORT
   LAYER M5 ;
   RECT 159.600000 0.000000 159.624000 0.084000 ;
  END
 END tw_data[461]
 PIN tw_data[462]
  DIRECTION INPUT ;
  USE SIGNAL ;
  PORT
   LAYER M5 ;
   RECT 159.792000 0.000000 159.816000 0.084000 ;
  END
 END tw_data[462]
 PIN tw_data[463]
  DIRECTION INPUT ;
  USE SIGNAL ;
  PORT
   LAYER M5 ;
   RECT 159.984000 0.000000 160.008000 0.084000 ;
  END
 END tw_data[463]
 PIN tw_data[464]
  DIRECTION INPUT ;
  USE SIGNAL ;
  PORT
   LAYER M5 ;
   RECT 160.176000 0.000000 160.200000 0.084000 ;
  END
 END tw_data[464]
 PIN tw_data[465]
  DIRECTION INPUT ;
  USE SIGNAL ;
  PORT
   LAYER M5 ;
   RECT 160.368000 0.000000 160.392000 0.084000 ;
  END
 END tw_data[465]
 PIN tw_data[466]
  DIRECTION INPUT ;
  USE SIGNAL ;
  PORT
   LAYER M5 ;
   RECT 160.560000 0.000000 160.584000 0.084000 ;
  END
 END tw_data[466]
 PIN tw_data[467]
  DIRECTION INPUT ;
  USE SIGNAL ;
  PORT
   LAYER M5 ;
   RECT 160.752000 0.000000 160.776000 0.084000 ;
  END
 END tw_data[467]
 PIN tw_data[468]
  DIRECTION INPUT ;
  USE SIGNAL ;
  PORT
   LAYER M5 ;
   RECT 160.944000 0.000000 160.968000 0.084000 ;
  END
 END tw_data[468]
 PIN tw_data[469]
  DIRECTION INPUT ;
  USE SIGNAL ;
  PORT
   LAYER M5 ;
   RECT 161.136000 0.000000 161.160000 0.084000 ;
  END
 END tw_data[469]
 PIN tw_data[470]
  DIRECTION INPUT ;
  USE SIGNAL ;
  PORT
   LAYER M5 ;
   RECT 161.328000 0.000000 161.352000 0.084000 ;
  END
 END tw_data[470]
 PIN tw_data[471]
  DIRECTION INPUT ;
  USE SIGNAL ;
  PORT
   LAYER M5 ;
   RECT 161.520000 0.000000 161.544000 0.084000 ;
  END
 END tw_data[471]
 PIN tw_data[472]
  DIRECTION INPUT ;
  USE SIGNAL ;
  PORT
   LAYER M5 ;
   RECT 161.712000 0.000000 161.736000 0.084000 ;
  END
 END tw_data[472]
 PIN tw_data[473]
  DIRECTION INPUT ;
  USE SIGNAL ;
  PORT
   LAYER M5 ;
   RECT 162.192000 0.000000 162.216000 0.084000 ;
  END
 END tw_data[473]
 PIN tw_data[474]
  DIRECTION INPUT ;
  USE SIGNAL ;
  PORT
   LAYER M5 ;
   RECT 162.384000 0.000000 162.408000 0.084000 ;
  END
 END tw_data[474]
 PIN tw_data[475]
  DIRECTION INPUT ;
  USE SIGNAL ;
  PORT
   LAYER M5 ;
   RECT 162.576000 0.000000 162.600000 0.084000 ;
  END
 END tw_data[475]
 PIN tw_data[476]
  DIRECTION INPUT ;
  USE SIGNAL ;
  PORT
   LAYER M5 ;
   RECT 162.768000 0.000000 162.792000 0.084000 ;
  END
 END tw_data[476]
 PIN tw_data[477]
  DIRECTION INPUT ;
  USE SIGNAL ;
  PORT
   LAYER M5 ;
   RECT 162.960000 0.000000 162.984000 0.084000 ;
  END
 END tw_data[477]
 PIN tw_data[478]
  DIRECTION INPUT ;
  USE SIGNAL ;
  PORT
   LAYER M5 ;
   RECT 163.152000 0.000000 163.176000 0.084000 ;
  END
 END tw_data[478]
 PIN tw_data[479]
  DIRECTION INPUT ;
  USE SIGNAL ;
  PORT
   LAYER M5 ;
   RECT 163.344000 0.000000 163.368000 0.084000 ;
  END
 END tw_data[479]
 PIN tw_data[480]
  DIRECTION INPUT ;
  USE SIGNAL ;
  PORT
   LAYER M5 ;
   RECT 163.536000 0.000000 163.560000 0.084000 ;
  END
 END tw_data[480]
 PIN tw_data[481]
  DIRECTION INPUT ;
  USE SIGNAL ;
  PORT
   LAYER M5 ;
   RECT 163.728000 0.000000 163.752000 0.084000 ;
  END
 END tw_data[481]
 PIN tw_data[482]
  DIRECTION INPUT ;
  USE SIGNAL ;
  PORT
   LAYER M5 ;
   RECT 163.920000 0.000000 163.944000 0.084000 ;
  END
 END tw_data[482]
 PIN tw_data[483]
  DIRECTION INPUT ;
  USE SIGNAL ;
  PORT
   LAYER M5 ;
   RECT 164.112000 0.000000 164.136000 0.084000 ;
  END
 END tw_data[483]
 PIN tw_data[484]
  DIRECTION INPUT ;
  USE SIGNAL ;
  PORT
   LAYER M5 ;
   RECT 164.304000 0.000000 164.328000 0.084000 ;
  END
 END tw_data[484]
 PIN tw_data[485]
  DIRECTION INPUT ;
  USE SIGNAL ;
  PORT
   LAYER M5 ;
   RECT 164.496000 0.000000 164.520000 0.084000 ;
  END
 END tw_data[485]
 PIN tw_data[486]
  DIRECTION INPUT ;
  USE SIGNAL ;
  PORT
   LAYER M5 ;
   RECT 164.688000 0.000000 164.712000 0.084000 ;
  END
 END tw_data[486]
 PIN tw_data[487]
  DIRECTION INPUT ;
  USE SIGNAL ;
  PORT
   LAYER M5 ;
   RECT 164.880000 0.000000 164.904000 0.084000 ;
  END
 END tw_data[487]
 PIN tw_data[488]
  DIRECTION INPUT ;
  USE SIGNAL ;
  PORT
   LAYER M5 ;
   RECT 165.072000 0.000000 165.096000 0.084000 ;
  END
 END tw_data[488]
 PIN tw_data[489]
  DIRECTION INPUT ;
  USE SIGNAL ;
  PORT
   LAYER M5 ;
   RECT 165.264000 0.000000 165.288000 0.084000 ;
  END
 END tw_data[489]
 PIN tw_data[490]
  DIRECTION INPUT ;
  USE SIGNAL ;
  PORT
   LAYER M5 ;
   RECT 165.456000 0.000000 165.480000 0.084000 ;
  END
 END tw_data[490]
 PIN tw_data[491]
  DIRECTION INPUT ;
  USE SIGNAL ;
  PORT
   LAYER M5 ;
   RECT 165.648000 0.000000 165.672000 0.084000 ;
  END
 END tw_data[491]
 PIN tw_data[492]
  DIRECTION INPUT ;
  USE SIGNAL ;
  PORT
   LAYER M5 ;
   RECT 165.840000 0.000000 165.864000 0.084000 ;
  END
 END tw_data[492]
 PIN tw_data[493]
  DIRECTION INPUT ;
  USE SIGNAL ;
  PORT
   LAYER M5 ;
   RECT 166.032000 0.000000 166.056000 0.084000 ;
  END
 END tw_data[493]
 PIN tw_data[494]
  DIRECTION INPUT ;
  USE SIGNAL ;
  PORT
   LAYER M5 ;
   RECT 166.512000 0.000000 166.536000 0.084000 ;
  END
 END tw_data[494]
 PIN tw_data[495]
  DIRECTION INPUT ;
  USE SIGNAL ;
  PORT
   LAYER M5 ;
   RECT 166.704000 0.000000 166.728000 0.084000 ;
  END
 END tw_data[495]
 PIN tw_data[496]
  DIRECTION INPUT ;
  USE SIGNAL ;
  PORT
   LAYER M5 ;
   RECT 166.896000 0.000000 166.920000 0.084000 ;
  END
 END tw_data[496]
 PIN tw_data[497]
  DIRECTION INPUT ;
  USE SIGNAL ;
  PORT
   LAYER M5 ;
   RECT 167.088000 0.000000 167.112000 0.084000 ;
  END
 END tw_data[497]
 PIN tw_data[498]
  DIRECTION INPUT ;
  USE SIGNAL ;
  PORT
   LAYER M5 ;
   RECT 167.280000 0.000000 167.304000 0.084000 ;
  END
 END tw_data[498]
 PIN tw_data[499]
  DIRECTION INPUT ;
  USE SIGNAL ;
  PORT
   LAYER M5 ;
   RECT 167.472000 0.000000 167.496000 0.084000 ;
  END
 END tw_data[499]
 PIN tw_data[500]
  DIRECTION INPUT ;
  USE SIGNAL ;
  PORT
   LAYER M5 ;
   RECT 167.664000 0.000000 167.688000 0.084000 ;
  END
 END tw_data[500]
 PIN tw_data[501]
  DIRECTION INPUT ;
  USE SIGNAL ;
  PORT
   LAYER M5 ;
   RECT 167.856000 0.000000 167.880000 0.084000 ;
  END
 END tw_data[501]
 PIN tw_data[502]
  DIRECTION INPUT ;
  USE SIGNAL ;
  PORT
   LAYER M5 ;
   RECT 168.048000 0.000000 168.072000 0.084000 ;
  END
 END tw_data[502]
 PIN tw_data[503]
  DIRECTION INPUT ;
  USE SIGNAL ;
  PORT
   LAYER M5 ;
   RECT 168.240000 0.000000 168.264000 0.084000 ;
  END
 END tw_data[503]
 PIN tw_data[504]
  DIRECTION INPUT ;
  USE SIGNAL ;
  PORT
   LAYER M5 ;
   RECT 168.432000 0.000000 168.456000 0.084000 ;
  END
 END tw_data[504]
 PIN tw_data[505]
  DIRECTION INPUT ;
  USE SIGNAL ;
  PORT
   LAYER M5 ;
   RECT 168.624000 0.000000 168.648000 0.084000 ;
  END
 END tw_data[505]
 PIN tw_data[506]
  DIRECTION INPUT ;
  USE SIGNAL ;
  PORT
   LAYER M5 ;
   RECT 168.816000 0.000000 168.840000 0.084000 ;
  END
 END tw_data[506]
 PIN tw_data[507]
  DIRECTION INPUT ;
  USE SIGNAL ;
  PORT
   LAYER M5 ;
   RECT 169.008000 0.000000 169.032000 0.084000 ;
  END
 END tw_data[507]
 PIN tw_data[508]
  DIRECTION INPUT ;
  USE SIGNAL ;
  PORT
   LAYER M5 ;
   RECT 169.200000 0.000000 169.224000 0.084000 ;
  END
 END tw_data[508]
 PIN tw_data[509]
  DIRECTION INPUT ;
  USE SIGNAL ;
  PORT
   LAYER M5 ;
   RECT 169.392000 0.000000 169.416000 0.084000 ;
  END
 END tw_data[509]
 PIN tw_data[510]
  DIRECTION INPUT ;
  USE SIGNAL ;
  PORT
   LAYER M5 ;
   RECT 169.584000 0.000000 169.608000 0.084000 ;
  END
 END tw_data[510]
 PIN tw_data[511]
  DIRECTION INPUT ;
  USE SIGNAL ;
  PORT
   LAYER M5 ;
   RECT 169.776000 0.000000 169.800000 0.084000 ;
  END
 END tw_data[511]
 PIN tw_data[512]
  DIRECTION INPUT ;
  USE SIGNAL ;
  PORT
   LAYER M5 ;
   RECT 184.320000 0.000000 184.344000 0.084000 ;
  END
 END tw_data[512]
 PIN tw_data[513]
  DIRECTION INPUT ;
  USE SIGNAL ;
  PORT
   LAYER M5 ;
   RECT 184.512000 0.000000 184.536000 0.084000 ;
  END
 END tw_data[513]
 PIN tw_data[514]
  DIRECTION INPUT ;
  USE SIGNAL ;
  PORT
   LAYER M5 ;
   RECT 184.704000 0.000000 184.728000 0.084000 ;
  END
 END tw_data[514]
 PIN tw_data[515]
  DIRECTION INPUT ;
  USE SIGNAL ;
  PORT
   LAYER M5 ;
   RECT 184.896000 0.000000 184.920000 0.084000 ;
  END
 END tw_data[515]
 PIN tw_data[516]
  DIRECTION INPUT ;
  USE SIGNAL ;
  PORT
   LAYER M5 ;
   RECT 185.088000 0.000000 185.112000 0.084000 ;
  END
 END tw_data[516]
 PIN tw_data[517]
  DIRECTION INPUT ;
  USE SIGNAL ;
  PORT
   LAYER M5 ;
   RECT 185.280000 0.000000 185.304000 0.084000 ;
  END
 END tw_data[517]
 PIN tw_data[518]
  DIRECTION INPUT ;
  USE SIGNAL ;
  PORT
   LAYER M5 ;
   RECT 185.472000 0.000000 185.496000 0.084000 ;
  END
 END tw_data[518]
 PIN tw_data[519]
  DIRECTION INPUT ;
  USE SIGNAL ;
  PORT
   LAYER M5 ;
   RECT 185.664000 0.000000 185.688000 0.084000 ;
  END
 END tw_data[519]
 PIN tw_data[520]
  DIRECTION INPUT ;
  USE SIGNAL ;
  PORT
   LAYER M5 ;
   RECT 185.856000 0.000000 185.880000 0.084000 ;
  END
 END tw_data[520]
 PIN tw_data[521]
  DIRECTION INPUT ;
  USE SIGNAL ;
  PORT
   LAYER M5 ;
   RECT 186.048000 0.000000 186.072000 0.084000 ;
  END
 END tw_data[521]
 PIN tw_data[522]
  DIRECTION INPUT ;
  USE SIGNAL ;
  PORT
   LAYER M5 ;
   RECT 186.240000 0.000000 186.264000 0.084000 ;
  END
 END tw_data[522]
 PIN tw_data[523]
  DIRECTION INPUT ;
  USE SIGNAL ;
  PORT
   LAYER M5 ;
   RECT 186.432000 0.000000 186.456000 0.084000 ;
  END
 END tw_data[523]
 PIN tw_data[524]
  DIRECTION INPUT ;
  USE SIGNAL ;
  PORT
   LAYER M5 ;
   RECT 186.624000 0.000000 186.648000 0.084000 ;
  END
 END tw_data[524]
 PIN tw_data[525]
  DIRECTION INPUT ;
  USE SIGNAL ;
  PORT
   LAYER M5 ;
   RECT 186.816000 0.000000 186.840000 0.084000 ;
  END
 END tw_data[525]
 PIN tw_data[526]
  DIRECTION INPUT ;
  USE SIGNAL ;
  PORT
   LAYER M5 ;
   RECT 187.008000 0.000000 187.032000 0.084000 ;
  END
 END tw_data[526]
 PIN tw_data[527]
  DIRECTION INPUT ;
  USE SIGNAL ;
  PORT
   LAYER M5 ;
   RECT 187.200000 0.000000 187.224000 0.084000 ;
  END
 END tw_data[527]
 PIN tw_data[528]
  DIRECTION INPUT ;
  USE SIGNAL ;
  PORT
   LAYER M5 ;
   RECT 187.392000 0.000000 187.416000 0.084000 ;
  END
 END tw_data[528]
 PIN tw_data[529]
  DIRECTION INPUT ;
  USE SIGNAL ;
  PORT
   LAYER M5 ;
   RECT 187.584000 0.000000 187.608000 0.084000 ;
  END
 END tw_data[529]
 PIN tw_data[530]
  DIRECTION INPUT ;
  USE SIGNAL ;
  PORT
   LAYER M5 ;
   RECT 188.112000 0.000000 188.136000 0.084000 ;
  END
 END tw_data[530]
 PIN tw_data[531]
  DIRECTION INPUT ;
  USE SIGNAL ;
  PORT
   LAYER M5 ;
   RECT 188.304000 0.000000 188.328000 0.084000 ;
  END
 END tw_data[531]
 PIN tw_data[532]
  DIRECTION INPUT ;
  USE SIGNAL ;
  PORT
   LAYER M5 ;
   RECT 188.496000 0.000000 188.520000 0.084000 ;
  END
 END tw_data[532]
 PIN tw_data[533]
  DIRECTION INPUT ;
  USE SIGNAL ;
  PORT
   LAYER M5 ;
   RECT 188.688000 0.000000 188.712000 0.084000 ;
  END
 END tw_data[533]
 PIN tw_data[534]
  DIRECTION INPUT ;
  USE SIGNAL ;
  PORT
   LAYER M5 ;
   RECT 188.880000 0.000000 188.904000 0.084000 ;
  END
 END tw_data[534]
 PIN tw_data[535]
  DIRECTION INPUT ;
  USE SIGNAL ;
  PORT
   LAYER M5 ;
   RECT 189.072000 0.000000 189.096000 0.084000 ;
  END
 END tw_data[535]
 PIN tw_data[536]
  DIRECTION INPUT ;
  USE SIGNAL ;
  PORT
   LAYER M5 ;
   RECT 189.264000 0.000000 189.288000 0.084000 ;
  END
 END tw_data[536]
 PIN tw_data[537]
  DIRECTION INPUT ;
  USE SIGNAL ;
  PORT
   LAYER M5 ;
   RECT 189.456000 0.000000 189.480000 0.084000 ;
  END
 END tw_data[537]
 PIN tw_data[538]
  DIRECTION INPUT ;
  USE SIGNAL ;
  PORT
   LAYER M5 ;
   RECT 189.648000 0.000000 189.672000 0.084000 ;
  END
 END tw_data[538]
 PIN tw_data[539]
  DIRECTION INPUT ;
  USE SIGNAL ;
  PORT
   LAYER M5 ;
   RECT 189.840000 0.000000 189.864000 0.084000 ;
  END
 END tw_data[539]
 PIN tw_data[540]
  DIRECTION INPUT ;
  USE SIGNAL ;
  PORT
   LAYER M5 ;
   RECT 190.032000 0.000000 190.056000 0.084000 ;
  END
 END tw_data[540]
 PIN tw_data[541]
  DIRECTION INPUT ;
  USE SIGNAL ;
  PORT
   LAYER M5 ;
   RECT 190.224000 0.000000 190.248000 0.084000 ;
  END
 END tw_data[541]
 PIN tw_data[542]
  DIRECTION INPUT ;
  USE SIGNAL ;
  PORT
   LAYER M5 ;
   RECT 190.416000 0.000000 190.440000 0.084000 ;
  END
 END tw_data[542]
 PIN tw_data[543]
  DIRECTION INPUT ;
  USE SIGNAL ;
  PORT
   LAYER M5 ;
   RECT 190.608000 0.000000 190.632000 0.084000 ;
  END
 END tw_data[543]
 PIN tw_data[544]
  DIRECTION INPUT ;
  USE SIGNAL ;
  PORT
   LAYER M5 ;
   RECT 190.800000 0.000000 190.824000 0.084000 ;
  END
 END tw_data[544]
 PIN tw_data[545]
  DIRECTION INPUT ;
  USE SIGNAL ;
  PORT
   LAYER M5 ;
   RECT 190.992000 0.000000 191.016000 0.084000 ;
  END
 END tw_data[545]
 PIN tw_data[546]
  DIRECTION INPUT ;
  USE SIGNAL ;
  PORT
   LAYER M5 ;
   RECT 191.184000 0.000000 191.208000 0.084000 ;
  END
 END tw_data[546]
 PIN tw_data[547]
  DIRECTION INPUT ;
  USE SIGNAL ;
  PORT
   LAYER M5 ;
   RECT 191.376000 0.000000 191.400000 0.084000 ;
  END
 END tw_data[547]
 PIN tw_data[548]
  DIRECTION INPUT ;
  USE SIGNAL ;
  PORT
   LAYER M5 ;
   RECT 191.568000 0.000000 191.592000 0.084000 ;
  END
 END tw_data[548]
 PIN tw_data[549]
  DIRECTION INPUT ;
  USE SIGNAL ;
  PORT
   LAYER M5 ;
   RECT 191.760000 0.000000 191.784000 0.084000 ;
  END
 END tw_data[549]
 PIN tw_data[550]
  DIRECTION INPUT ;
  USE SIGNAL ;
  PORT
   LAYER M5 ;
   RECT 191.952000 0.000000 191.976000 0.084000 ;
  END
 END tw_data[550]
 PIN tw_data[551]
  DIRECTION INPUT ;
  USE SIGNAL ;
  PORT
   LAYER M5 ;
   RECT 192.432000 0.000000 192.456000 0.084000 ;
  END
 END tw_data[551]
 PIN tw_data[552]
  DIRECTION INPUT ;
  USE SIGNAL ;
  PORT
   LAYER M5 ;
   RECT 192.624000 0.000000 192.648000 0.084000 ;
  END
 END tw_data[552]
 PIN tw_data[553]
  DIRECTION INPUT ;
  USE SIGNAL ;
  PORT
   LAYER M5 ;
   RECT 192.816000 0.000000 192.840000 0.084000 ;
  END
 END tw_data[553]
 PIN tw_data[554]
  DIRECTION INPUT ;
  USE SIGNAL ;
  PORT
   LAYER M5 ;
   RECT 193.008000 0.000000 193.032000 0.084000 ;
  END
 END tw_data[554]
 PIN tw_data[555]
  DIRECTION INPUT ;
  USE SIGNAL ;
  PORT
   LAYER M5 ;
   RECT 193.200000 0.000000 193.224000 0.084000 ;
  END
 END tw_data[555]
 PIN tw_data[556]
  DIRECTION INPUT ;
  USE SIGNAL ;
  PORT
   LAYER M5 ;
   RECT 193.392000 0.000000 193.416000 0.084000 ;
  END
 END tw_data[556]
 PIN tw_data[557]
  DIRECTION INPUT ;
  USE SIGNAL ;
  PORT
   LAYER M5 ;
   RECT 193.584000 0.000000 193.608000 0.084000 ;
  END
 END tw_data[557]
 PIN tw_data[558]
  DIRECTION INPUT ;
  USE SIGNAL ;
  PORT
   LAYER M5 ;
   RECT 193.776000 0.000000 193.800000 0.084000 ;
  END
 END tw_data[558]
 PIN tw_data[559]
  DIRECTION INPUT ;
  USE SIGNAL ;
  PORT
   LAYER M5 ;
   RECT 193.968000 0.000000 193.992000 0.084000 ;
  END
 END tw_data[559]
 PIN tw_data[560]
  DIRECTION INPUT ;
  USE SIGNAL ;
  PORT
   LAYER M5 ;
   RECT 194.160000 0.000000 194.184000 0.084000 ;
  END
 END tw_data[560]
 PIN tw_data[561]
  DIRECTION INPUT ;
  USE SIGNAL ;
  PORT
   LAYER M5 ;
   RECT 194.352000 0.000000 194.376000 0.084000 ;
  END
 END tw_data[561]
 PIN tw_data[562]
  DIRECTION INPUT ;
  USE SIGNAL ;
  PORT
   LAYER M5 ;
   RECT 194.544000 0.000000 194.568000 0.084000 ;
  END
 END tw_data[562]
 PIN tw_data[563]
  DIRECTION INPUT ;
  USE SIGNAL ;
  PORT
   LAYER M5 ;
   RECT 194.736000 0.000000 194.760000 0.084000 ;
  END
 END tw_data[563]
 PIN tw_data[564]
  DIRECTION INPUT ;
  USE SIGNAL ;
  PORT
   LAYER M5 ;
   RECT 194.928000 0.000000 194.952000 0.084000 ;
  END
 END tw_data[564]
 PIN tw_data[565]
  DIRECTION INPUT ;
  USE SIGNAL ;
  PORT
   LAYER M5 ;
   RECT 195.120000 0.000000 195.144000 0.084000 ;
  END
 END tw_data[565]
 PIN tw_data[566]
  DIRECTION INPUT ;
  USE SIGNAL ;
  PORT
   LAYER M5 ;
   RECT 195.312000 0.000000 195.336000 0.084000 ;
  END
 END tw_data[566]
 PIN tw_data[567]
  DIRECTION INPUT ;
  USE SIGNAL ;
  PORT
   LAYER M5 ;
   RECT 195.504000 0.000000 195.528000 0.084000 ;
  END
 END tw_data[567]
 PIN tw_data[568]
  DIRECTION INPUT ;
  USE SIGNAL ;
  PORT
   LAYER M5 ;
   RECT 195.696000 0.000000 195.720000 0.084000 ;
  END
 END tw_data[568]
 PIN tw_data[569]
  DIRECTION INPUT ;
  USE SIGNAL ;
  PORT
   LAYER M5 ;
   RECT 195.888000 0.000000 195.912000 0.084000 ;
  END
 END tw_data[569]
 PIN tw_data[570]
  DIRECTION INPUT ;
  USE SIGNAL ;
  PORT
   LAYER M5 ;
   RECT 196.080000 0.000000 196.104000 0.084000 ;
  END
 END tw_data[570]
 PIN tw_data[571]
  DIRECTION INPUT ;
  USE SIGNAL ;
  PORT
   LAYER M5 ;
   RECT 196.272000 0.000000 196.296000 0.084000 ;
  END
 END tw_data[571]
 PIN tw_data[572]
  DIRECTION INPUT ;
  USE SIGNAL ;
  PORT
   LAYER M5 ;
   RECT 196.752000 0.000000 196.776000 0.084000 ;
  END
 END tw_data[572]
 PIN tw_data[573]
  DIRECTION INPUT ;
  USE SIGNAL ;
  PORT
   LAYER M5 ;
   RECT 196.944000 0.000000 196.968000 0.084000 ;
  END
 END tw_data[573]
 PIN tw_data[574]
  DIRECTION INPUT ;
  USE SIGNAL ;
  PORT
   LAYER M5 ;
   RECT 197.136000 0.000000 197.160000 0.084000 ;
  END
 END tw_data[574]
 PIN tw_data[575]
  DIRECTION INPUT ;
  USE SIGNAL ;
  PORT
   LAYER M5 ;
   RECT 197.328000 0.000000 197.352000 0.084000 ;
  END
 END tw_data[575]
 PIN tw_data[576]
  DIRECTION INPUT ;
  USE SIGNAL ;
  PORT
   LAYER M5 ;
   RECT 197.520000 0.000000 197.544000 0.084000 ;
  END
 END tw_data[576]
 PIN tw_data[577]
  DIRECTION INPUT ;
  USE SIGNAL ;
  PORT
   LAYER M5 ;
   RECT 197.712000 0.000000 197.736000 0.084000 ;
  END
 END tw_data[577]
 PIN tw_data[578]
  DIRECTION INPUT ;
  USE SIGNAL ;
  PORT
   LAYER M5 ;
   RECT 197.904000 0.000000 197.928000 0.084000 ;
  END
 END tw_data[578]
 PIN tw_data[579]
  DIRECTION INPUT ;
  USE SIGNAL ;
  PORT
   LAYER M5 ;
   RECT 198.096000 0.000000 198.120000 0.084000 ;
  END
 END tw_data[579]
 PIN tw_data[580]
  DIRECTION INPUT ;
  USE SIGNAL ;
  PORT
   LAYER M5 ;
   RECT 198.288000 0.000000 198.312000 0.084000 ;
  END
 END tw_data[580]
 PIN tw_data[581]
  DIRECTION INPUT ;
  USE SIGNAL ;
  PORT
   LAYER M5 ;
   RECT 198.480000 0.000000 198.504000 0.084000 ;
  END
 END tw_data[581]
 PIN tw_data[582]
  DIRECTION INPUT ;
  USE SIGNAL ;
  PORT
   LAYER M5 ;
   RECT 198.672000 0.000000 198.696000 0.084000 ;
  END
 END tw_data[582]
 PIN tw_data[583]
  DIRECTION INPUT ;
  USE SIGNAL ;
  PORT
   LAYER M5 ;
   RECT 198.864000 0.000000 198.888000 0.084000 ;
  END
 END tw_data[583]
 PIN tw_data[584]
  DIRECTION INPUT ;
  USE SIGNAL ;
  PORT
   LAYER M5 ;
   RECT 199.056000 0.000000 199.080000 0.084000 ;
  END
 END tw_data[584]
 PIN tw_data[585]
  DIRECTION INPUT ;
  USE SIGNAL ;
  PORT
   LAYER M5 ;
   RECT 199.248000 0.000000 199.272000 0.084000 ;
  END
 END tw_data[585]
 PIN tw_data[586]
  DIRECTION INPUT ;
  USE SIGNAL ;
  PORT
   LAYER M5 ;
   RECT 199.440000 0.000000 199.464000 0.084000 ;
  END
 END tw_data[586]
 PIN tw_data[587]
  DIRECTION INPUT ;
  USE SIGNAL ;
  PORT
   LAYER M5 ;
   RECT 199.632000 0.000000 199.656000 0.084000 ;
  END
 END tw_data[587]
 PIN tw_data[588]
  DIRECTION INPUT ;
  USE SIGNAL ;
  PORT
   LAYER M5 ;
   RECT 199.824000 0.000000 199.848000 0.084000 ;
  END
 END tw_data[588]
 PIN tw_data[589]
  DIRECTION INPUT ;
  USE SIGNAL ;
  PORT
   LAYER M5 ;
   RECT 200.016000 0.000000 200.040000 0.084000 ;
  END
 END tw_data[589]
 PIN tw_data[590]
  DIRECTION INPUT ;
  USE SIGNAL ;
  PORT
   LAYER M5 ;
   RECT 200.208000 0.000000 200.232000 0.084000 ;
  END
 END tw_data[590]
 PIN tw_data[591]
  DIRECTION INPUT ;
  USE SIGNAL ;
  PORT
   LAYER M5 ;
   RECT 200.400000 0.000000 200.424000 0.084000 ;
  END
 END tw_data[591]
 PIN tw_data[592]
  DIRECTION INPUT ;
  USE SIGNAL ;
  PORT
   LAYER M5 ;
   RECT 200.592000 0.000000 200.616000 0.084000 ;
  END
 END tw_data[592]
 PIN tw_data[593]
  DIRECTION INPUT ;
  USE SIGNAL ;
  PORT
   LAYER M5 ;
   RECT 201.072000 0.000000 201.096000 0.084000 ;
  END
 END tw_data[593]
 PIN tw_data[594]
  DIRECTION INPUT ;
  USE SIGNAL ;
  PORT
   LAYER M5 ;
   RECT 201.264000 0.000000 201.288000 0.084000 ;
  END
 END tw_data[594]
 PIN tw_data[595]
  DIRECTION INPUT ;
  USE SIGNAL ;
  PORT
   LAYER M5 ;
   RECT 201.456000 0.000000 201.480000 0.084000 ;
  END
 END tw_data[595]
 PIN tw_data[596]
  DIRECTION INPUT ;
  USE SIGNAL ;
  PORT
   LAYER M5 ;
   RECT 201.648000 0.000000 201.672000 0.084000 ;
  END
 END tw_data[596]
 PIN tw_data[597]
  DIRECTION INPUT ;
  USE SIGNAL ;
  PORT
   LAYER M5 ;
   RECT 201.840000 0.000000 201.864000 0.084000 ;
  END
 END tw_data[597]
 PIN tw_data[598]
  DIRECTION INPUT ;
  USE SIGNAL ;
  PORT
   LAYER M5 ;
   RECT 202.032000 0.000000 202.056000 0.084000 ;
  END
 END tw_data[598]
 PIN tw_data[599]
  DIRECTION INPUT ;
  USE SIGNAL ;
  PORT
   LAYER M5 ;
   RECT 202.224000 0.000000 202.248000 0.084000 ;
  END
 END tw_data[599]
 PIN tw_data[600]
  DIRECTION INPUT ;
  USE SIGNAL ;
  PORT
   LAYER M5 ;
   RECT 202.416000 0.000000 202.440000 0.084000 ;
  END
 END tw_data[600]
 PIN tw_data[601]
  DIRECTION INPUT ;
  USE SIGNAL ;
  PORT
   LAYER M5 ;
   RECT 202.608000 0.000000 202.632000 0.084000 ;
  END
 END tw_data[601]
 PIN tw_data[602]
  DIRECTION INPUT ;
  USE SIGNAL ;
  PORT
   LAYER M5 ;
   RECT 202.800000 0.000000 202.824000 0.084000 ;
  END
 END tw_data[602]
 PIN tw_data[603]
  DIRECTION INPUT ;
  USE SIGNAL ;
  PORT
   LAYER M5 ;
   RECT 202.992000 0.000000 203.016000 0.084000 ;
  END
 END tw_data[603]
 PIN tw_data[604]
  DIRECTION INPUT ;
  USE SIGNAL ;
  PORT
   LAYER M5 ;
   RECT 203.184000 0.000000 203.208000 0.084000 ;
  END
 END tw_data[604]
 PIN tw_data[605]
  DIRECTION INPUT ;
  USE SIGNAL ;
  PORT
   LAYER M5 ;
   RECT 203.376000 0.000000 203.400000 0.084000 ;
  END
 END tw_data[605]
 PIN tw_data[606]
  DIRECTION INPUT ;
  USE SIGNAL ;
  PORT
   LAYER M5 ;
   RECT 203.568000 0.000000 203.592000 0.084000 ;
  END
 END tw_data[606]
 PIN tw_data[607]
  DIRECTION INPUT ;
  USE SIGNAL ;
  PORT
   LAYER M5 ;
   RECT 203.760000 0.000000 203.784000 0.084000 ;
  END
 END tw_data[607]
 PIN tw_data[608]
  DIRECTION INPUT ;
  USE SIGNAL ;
  PORT
   LAYER M5 ;
   RECT 203.952000 0.000000 203.976000 0.084000 ;
  END
 END tw_data[608]
 PIN tw_data[609]
  DIRECTION INPUT ;
  USE SIGNAL ;
  PORT
   LAYER M5 ;
   RECT 204.144000 0.000000 204.168000 0.084000 ;
  END
 END tw_data[609]
 PIN tw_data[610]
  DIRECTION INPUT ;
  USE SIGNAL ;
  PORT
   LAYER M5 ;
   RECT 204.336000 0.000000 204.360000 0.084000 ;
  END
 END tw_data[610]
 PIN tw_data[611]
  DIRECTION INPUT ;
  USE SIGNAL ;
  PORT
   LAYER M5 ;
   RECT 204.528000 0.000000 204.552000 0.084000 ;
  END
 END tw_data[611]
 PIN tw_data[612]
  DIRECTION INPUT ;
  USE SIGNAL ;
  PORT
   LAYER M5 ;
   RECT 204.720000 0.000000 204.744000 0.084000 ;
  END
 END tw_data[612]
 PIN tw_data[613]
  DIRECTION INPUT ;
  USE SIGNAL ;
  PORT
   LAYER M5 ;
   RECT 204.912000 0.000000 204.936000 0.084000 ;
  END
 END tw_data[613]
 PIN tw_data[614]
  DIRECTION INPUT ;
  USE SIGNAL ;
  PORT
   LAYER M5 ;
   RECT 205.392000 0.000000 205.416000 0.084000 ;
  END
 END tw_data[614]
 PIN tw_data[615]
  DIRECTION INPUT ;
  USE SIGNAL ;
  PORT
   LAYER M5 ;
   RECT 205.584000 0.000000 205.608000 0.084000 ;
  END
 END tw_data[615]
 PIN tw_data[616]
  DIRECTION INPUT ;
  USE SIGNAL ;
  PORT
   LAYER M5 ;
   RECT 205.776000 0.000000 205.800000 0.084000 ;
  END
 END tw_data[616]
 PIN tw_data[617]
  DIRECTION INPUT ;
  USE SIGNAL ;
  PORT
   LAYER M5 ;
   RECT 205.968000 0.000000 205.992000 0.084000 ;
  END
 END tw_data[617]
 PIN tw_data[618]
  DIRECTION INPUT ;
  USE SIGNAL ;
  PORT
   LAYER M5 ;
   RECT 206.160000 0.000000 206.184000 0.084000 ;
  END
 END tw_data[618]
 PIN tw_data[619]
  DIRECTION INPUT ;
  USE SIGNAL ;
  PORT
   LAYER M5 ;
   RECT 206.352000 0.000000 206.376000 0.084000 ;
  END
 END tw_data[619]
 PIN tw_data[620]
  DIRECTION INPUT ;
  USE SIGNAL ;
  PORT
   LAYER M5 ;
   RECT 206.544000 0.000000 206.568000 0.084000 ;
  END
 END tw_data[620]
 PIN tw_data[621]
  DIRECTION INPUT ;
  USE SIGNAL ;
  PORT
   LAYER M5 ;
   RECT 206.736000 0.000000 206.760000 0.084000 ;
  END
 END tw_data[621]
 PIN tw_data[622]
  DIRECTION INPUT ;
  USE SIGNAL ;
  PORT
   LAYER M5 ;
   RECT 206.928000 0.000000 206.952000 0.084000 ;
  END
 END tw_data[622]
 PIN tw_data[623]
  DIRECTION INPUT ;
  USE SIGNAL ;
  PORT
   LAYER M5 ;
   RECT 207.120000 0.000000 207.144000 0.084000 ;
  END
 END tw_data[623]
 PIN tw_data[624]
  DIRECTION INPUT ;
  USE SIGNAL ;
  PORT
   LAYER M5 ;
   RECT 207.312000 0.000000 207.336000 0.084000 ;
  END
 END tw_data[624]
 PIN tw_data[625]
  DIRECTION INPUT ;
  USE SIGNAL ;
  PORT
   LAYER M5 ;
   RECT 207.504000 0.000000 207.528000 0.084000 ;
  END
 END tw_data[625]
 PIN tw_data[626]
  DIRECTION INPUT ;
  USE SIGNAL ;
  PORT
   LAYER M5 ;
   RECT 207.696000 0.000000 207.720000 0.084000 ;
  END
 END tw_data[626]
 PIN tw_data[627]
  DIRECTION INPUT ;
  USE SIGNAL ;
  PORT
   LAYER M5 ;
   RECT 207.888000 0.000000 207.912000 0.084000 ;
  END
 END tw_data[627]
 PIN tw_data[628]
  DIRECTION INPUT ;
  USE SIGNAL ;
  PORT
   LAYER M5 ;
   RECT 208.080000 0.000000 208.104000 0.084000 ;
  END
 END tw_data[628]
 PIN tw_data[629]
  DIRECTION INPUT ;
  USE SIGNAL ;
  PORT
   LAYER M5 ;
   RECT 208.272000 0.000000 208.296000 0.084000 ;
  END
 END tw_data[629]
 PIN tw_data[630]
  DIRECTION INPUT ;
  USE SIGNAL ;
  PORT
   LAYER M5 ;
   RECT 208.464000 0.000000 208.488000 0.084000 ;
  END
 END tw_data[630]
 PIN tw_data[631]
  DIRECTION INPUT ;
  USE SIGNAL ;
  PORT
   LAYER M5 ;
   RECT 208.656000 0.000000 208.680000 0.084000 ;
  END
 END tw_data[631]
 PIN tw_data[632]
  DIRECTION INPUT ;
  USE SIGNAL ;
  PORT
   LAYER M5 ;
   RECT 208.848000 0.000000 208.872000 0.084000 ;
  END
 END tw_data[632]
 PIN tw_data[633]
  DIRECTION INPUT ;
  USE SIGNAL ;
  PORT
   LAYER M5 ;
   RECT 209.040000 0.000000 209.064000 0.084000 ;
  END
 END tw_data[633]
 PIN tw_data[634]
  DIRECTION INPUT ;
  USE SIGNAL ;
  PORT
   LAYER M5 ;
   RECT 209.232000 0.000000 209.256000 0.084000 ;
  END
 END tw_data[634]
 PIN tw_data[635]
  DIRECTION INPUT ;
  USE SIGNAL ;
  PORT
   LAYER M5 ;
   RECT 209.712000 0.000000 209.736000 0.084000 ;
  END
 END tw_data[635]
 PIN tw_data[636]
  DIRECTION INPUT ;
  USE SIGNAL ;
  PORT
   LAYER M5 ;
   RECT 209.904000 0.000000 209.928000 0.084000 ;
  END
 END tw_data[636]
 PIN tw_data[637]
  DIRECTION INPUT ;
  USE SIGNAL ;
  PORT
   LAYER M5 ;
   RECT 210.096000 0.000000 210.120000 0.084000 ;
  END
 END tw_data[637]
 PIN tw_data[638]
  DIRECTION INPUT ;
  USE SIGNAL ;
  PORT
   LAYER M5 ;
   RECT 210.288000 0.000000 210.312000 0.084000 ;
  END
 END tw_data[638]
 PIN tw_data[639]
  DIRECTION INPUT ;
  USE SIGNAL ;
  PORT
   LAYER M5 ;
   RECT 210.480000 0.000000 210.504000 0.084000 ;
  END
 END tw_data[639]
 PIN tw_data[640]
  DIRECTION INPUT ;
  USE SIGNAL ;
  PORT
   LAYER M5 ;
   RECT 210.672000 0.000000 210.696000 0.084000 ;
  END
 END tw_data[640]
 PIN tw_data[641]
  DIRECTION INPUT ;
  USE SIGNAL ;
  PORT
   LAYER M5 ;
   RECT 210.864000 0.000000 210.888000 0.084000 ;
  END
 END tw_data[641]
 PIN tw_data[642]
  DIRECTION INPUT ;
  USE SIGNAL ;
  PORT
   LAYER M5 ;
   RECT 211.056000 0.000000 211.080000 0.084000 ;
  END
 END tw_data[642]
 PIN tw_data[643]
  DIRECTION INPUT ;
  USE SIGNAL ;
  PORT
   LAYER M5 ;
   RECT 211.248000 0.000000 211.272000 0.084000 ;
  END
 END tw_data[643]
 PIN tw_data[644]
  DIRECTION INPUT ;
  USE SIGNAL ;
  PORT
   LAYER M5 ;
   RECT 211.440000 0.000000 211.464000 0.084000 ;
  END
 END tw_data[644]
 PIN tw_data[645]
  DIRECTION INPUT ;
  USE SIGNAL ;
  PORT
   LAYER M5 ;
   RECT 211.632000 0.000000 211.656000 0.084000 ;
  END
 END tw_data[645]
 PIN tw_data[646]
  DIRECTION INPUT ;
  USE SIGNAL ;
  PORT
   LAYER M5 ;
   RECT 211.824000 0.000000 211.848000 0.084000 ;
  END
 END tw_data[646]
 PIN tw_data[647]
  DIRECTION INPUT ;
  USE SIGNAL ;
  PORT
   LAYER M5 ;
   RECT 212.016000 0.000000 212.040000 0.084000 ;
  END
 END tw_data[647]
 PIN tw_data[648]
  DIRECTION INPUT ;
  USE SIGNAL ;
  PORT
   LAYER M5 ;
   RECT 212.208000 0.000000 212.232000 0.084000 ;
  END
 END tw_data[648]
 PIN tw_data[649]
  DIRECTION INPUT ;
  USE SIGNAL ;
  PORT
   LAYER M5 ;
   RECT 212.400000 0.000000 212.424000 0.084000 ;
  END
 END tw_data[649]
 PIN tw_data[650]
  DIRECTION INPUT ;
  USE SIGNAL ;
  PORT
   LAYER M5 ;
   RECT 212.592000 0.000000 212.616000 0.084000 ;
  END
 END tw_data[650]
 PIN tw_data[651]
  DIRECTION INPUT ;
  USE SIGNAL ;
  PORT
   LAYER M5 ;
   RECT 212.784000 0.000000 212.808000 0.084000 ;
  END
 END tw_data[651]
 PIN tw_data[652]
  DIRECTION INPUT ;
  USE SIGNAL ;
  PORT
   LAYER M5 ;
   RECT 212.976000 0.000000 213.000000 0.084000 ;
  END
 END tw_data[652]
 PIN tw_data[653]
  DIRECTION INPUT ;
  USE SIGNAL ;
  PORT
   LAYER M5 ;
   RECT 213.168000 0.000000 213.192000 0.084000 ;
  END
 END tw_data[653]
 PIN tw_data[654]
  DIRECTION INPUT ;
  USE SIGNAL ;
  PORT
   LAYER M5 ;
   RECT 213.360000 0.000000 213.384000 0.084000 ;
  END
 END tw_data[654]
 PIN tw_data[655]
  DIRECTION INPUT ;
  USE SIGNAL ;
  PORT
   LAYER M5 ;
   RECT 213.552000 0.000000 213.576000 0.084000 ;
  END
 END tw_data[655]
 PIN tw_data[656]
  DIRECTION INPUT ;
  USE SIGNAL ;
  PORT
   LAYER M5 ;
   RECT 214.032000 0.000000 214.056000 0.084000 ;
  END
 END tw_data[656]
 PIN tw_data[657]
  DIRECTION INPUT ;
  USE SIGNAL ;
  PORT
   LAYER M5 ;
   RECT 214.224000 0.000000 214.248000 0.084000 ;
  END
 END tw_data[657]
 PIN tw_data[658]
  DIRECTION INPUT ;
  USE SIGNAL ;
  PORT
   LAYER M5 ;
   RECT 214.416000 0.000000 214.440000 0.084000 ;
  END
 END tw_data[658]
 PIN tw_data[659]
  DIRECTION INPUT ;
  USE SIGNAL ;
  PORT
   LAYER M5 ;
   RECT 214.608000 0.000000 214.632000 0.084000 ;
  END
 END tw_data[659]
 PIN tw_data[660]
  DIRECTION INPUT ;
  USE SIGNAL ;
  PORT
   LAYER M5 ;
   RECT 214.800000 0.000000 214.824000 0.084000 ;
  END
 END tw_data[660]
 PIN tw_data[661]
  DIRECTION INPUT ;
  USE SIGNAL ;
  PORT
   LAYER M5 ;
   RECT 214.992000 0.000000 215.016000 0.084000 ;
  END
 END tw_data[661]
 PIN tw_data[662]
  DIRECTION INPUT ;
  USE SIGNAL ;
  PORT
   LAYER M5 ;
   RECT 215.184000 0.000000 215.208000 0.084000 ;
  END
 END tw_data[662]
 PIN tw_data[663]
  DIRECTION INPUT ;
  USE SIGNAL ;
  PORT
   LAYER M5 ;
   RECT 215.376000 0.000000 215.400000 0.084000 ;
  END
 END tw_data[663]
 PIN tw_data[664]
  DIRECTION INPUT ;
  USE SIGNAL ;
  PORT
   LAYER M5 ;
   RECT 215.568000 0.000000 215.592000 0.084000 ;
  END
 END tw_data[664]
 PIN tw_data[665]
  DIRECTION INPUT ;
  USE SIGNAL ;
  PORT
   LAYER M5 ;
   RECT 215.760000 0.000000 215.784000 0.084000 ;
  END
 END tw_data[665]
 PIN tw_data[666]
  DIRECTION INPUT ;
  USE SIGNAL ;
  PORT
   LAYER M5 ;
   RECT 215.952000 0.000000 215.976000 0.084000 ;
  END
 END tw_data[666]
 PIN tw_data[667]
  DIRECTION INPUT ;
  USE SIGNAL ;
  PORT
   LAYER M5 ;
   RECT 216.144000 0.000000 216.168000 0.084000 ;
  END
 END tw_data[667]
 PIN tw_data[668]
  DIRECTION INPUT ;
  USE SIGNAL ;
  PORT
   LAYER M5 ;
   RECT 216.336000 0.000000 216.360000 0.084000 ;
  END
 END tw_data[668]
 PIN tw_data[669]
  DIRECTION INPUT ;
  USE SIGNAL ;
  PORT
   LAYER M5 ;
   RECT 216.528000 0.000000 216.552000 0.084000 ;
  END
 END tw_data[669]
 PIN tw_data[670]
  DIRECTION INPUT ;
  USE SIGNAL ;
  PORT
   LAYER M5 ;
   RECT 216.720000 0.000000 216.744000 0.084000 ;
  END
 END tw_data[670]
 PIN tw_data[671]
  DIRECTION INPUT ;
  USE SIGNAL ;
  PORT
   LAYER M5 ;
   RECT 216.912000 0.000000 216.936000 0.084000 ;
  END
 END tw_data[671]
 PIN tw_data[672]
  DIRECTION INPUT ;
  USE SIGNAL ;
  PORT
   LAYER M5 ;
   RECT 217.104000 0.000000 217.128000 0.084000 ;
  END
 END tw_data[672]
 PIN tw_data[673]
  DIRECTION INPUT ;
  USE SIGNAL ;
  PORT
   LAYER M5 ;
   RECT 217.296000 0.000000 217.320000 0.084000 ;
  END
 END tw_data[673]
 PIN tw_data[674]
  DIRECTION INPUT ;
  USE SIGNAL ;
  PORT
   LAYER M5 ;
   RECT 217.488000 0.000000 217.512000 0.084000 ;
  END
 END tw_data[674]
 PIN tw_data[675]
  DIRECTION INPUT ;
  USE SIGNAL ;
  PORT
   LAYER M5 ;
   RECT 217.680000 0.000000 217.704000 0.084000 ;
  END
 END tw_data[675]
 PIN tw_data[676]
  DIRECTION INPUT ;
  USE SIGNAL ;
  PORT
   LAYER M5 ;
   RECT 217.872000 0.000000 217.896000 0.084000 ;
  END
 END tw_data[676]
 PIN tw_data[677]
  DIRECTION INPUT ;
  USE SIGNAL ;
  PORT
   LAYER M5 ;
   RECT 218.352000 0.000000 218.376000 0.084000 ;
  END
 END tw_data[677]
 PIN tw_data[678]
  DIRECTION INPUT ;
  USE SIGNAL ;
  PORT
   LAYER M5 ;
   RECT 218.544000 0.000000 218.568000 0.084000 ;
  END
 END tw_data[678]
 PIN tw_data[679]
  DIRECTION INPUT ;
  USE SIGNAL ;
  PORT
   LAYER M5 ;
   RECT 218.736000 0.000000 218.760000 0.084000 ;
  END
 END tw_data[679]
 PIN tw_data[680]
  DIRECTION INPUT ;
  USE SIGNAL ;
  PORT
   LAYER M5 ;
   RECT 218.928000 0.000000 218.952000 0.084000 ;
  END
 END tw_data[680]
 PIN tw_data[681]
  DIRECTION INPUT ;
  USE SIGNAL ;
  PORT
   LAYER M5 ;
   RECT 219.120000 0.000000 219.144000 0.084000 ;
  END
 END tw_data[681]
 PIN tw_data[682]
  DIRECTION INPUT ;
  USE SIGNAL ;
  PORT
   LAYER M5 ;
   RECT 219.312000 0.000000 219.336000 0.084000 ;
  END
 END tw_data[682]
 PIN tw_data[683]
  DIRECTION INPUT ;
  USE SIGNAL ;
  PORT
   LAYER M5 ;
   RECT 219.504000 0.000000 219.528000 0.084000 ;
  END
 END tw_data[683]
 PIN tw_data[684]
  DIRECTION INPUT ;
  USE SIGNAL ;
  PORT
   LAYER M5 ;
   RECT 219.696000 0.000000 219.720000 0.084000 ;
  END
 END tw_data[684]
 PIN tw_data[685]
  DIRECTION INPUT ;
  USE SIGNAL ;
  PORT
   LAYER M5 ;
   RECT 219.888000 0.000000 219.912000 0.084000 ;
  END
 END tw_data[685]
 PIN tw_data[686]
  DIRECTION INPUT ;
  USE SIGNAL ;
  PORT
   LAYER M5 ;
   RECT 220.080000 0.000000 220.104000 0.084000 ;
  END
 END tw_data[686]
 PIN tw_data[687]
  DIRECTION INPUT ;
  USE SIGNAL ;
  PORT
   LAYER M5 ;
   RECT 220.272000 0.000000 220.296000 0.084000 ;
  END
 END tw_data[687]
 PIN tw_data[688]
  DIRECTION INPUT ;
  USE SIGNAL ;
  PORT
   LAYER M5 ;
   RECT 220.464000 0.000000 220.488000 0.084000 ;
  END
 END tw_data[688]
 PIN tw_data[689]
  DIRECTION INPUT ;
  USE SIGNAL ;
  PORT
   LAYER M5 ;
   RECT 220.656000 0.000000 220.680000 0.084000 ;
  END
 END tw_data[689]
 PIN tw_data[690]
  DIRECTION INPUT ;
  USE SIGNAL ;
  PORT
   LAYER M5 ;
   RECT 220.848000 0.000000 220.872000 0.084000 ;
  END
 END tw_data[690]
 PIN tw_data[691]
  DIRECTION INPUT ;
  USE SIGNAL ;
  PORT
   LAYER M5 ;
   RECT 221.040000 0.000000 221.064000 0.084000 ;
  END
 END tw_data[691]
 PIN tw_data[692]
  DIRECTION INPUT ;
  USE SIGNAL ;
  PORT
   LAYER M5 ;
   RECT 221.232000 0.000000 221.256000 0.084000 ;
  END
 END tw_data[692]
 PIN tw_data[693]
  DIRECTION INPUT ;
  USE SIGNAL ;
  PORT
   LAYER M5 ;
   RECT 221.424000 0.000000 221.448000 0.084000 ;
  END
 END tw_data[693]
 PIN tw_data[694]
  DIRECTION INPUT ;
  USE SIGNAL ;
  PORT
   LAYER M5 ;
   RECT 221.616000 0.000000 221.640000 0.084000 ;
  END
 END tw_data[694]
 PIN tw_data[695]
  DIRECTION INPUT ;
  USE SIGNAL ;
  PORT
   LAYER M5 ;
   RECT 221.808000 0.000000 221.832000 0.084000 ;
  END
 END tw_data[695]
 PIN tw_data[696]
  DIRECTION INPUT ;
  USE SIGNAL ;
  PORT
   LAYER M5 ;
   RECT 222.000000 0.000000 222.024000 0.084000 ;
  END
 END tw_data[696]
 PIN tw_data[697]
  DIRECTION INPUT ;
  USE SIGNAL ;
  PORT
   LAYER M5 ;
   RECT 222.192000 0.000000 222.216000 0.084000 ;
  END
 END tw_data[697]
 PIN tw_data[698]
  DIRECTION INPUT ;
  USE SIGNAL ;
  PORT
   LAYER M5 ;
   RECT 222.672000 0.000000 222.696000 0.084000 ;
  END
 END tw_data[698]
 PIN tw_data[699]
  DIRECTION INPUT ;
  USE SIGNAL ;
  PORT
   LAYER M5 ;
   RECT 222.864000 0.000000 222.888000 0.084000 ;
  END
 END tw_data[699]
 PIN tw_data[700]
  DIRECTION INPUT ;
  USE SIGNAL ;
  PORT
   LAYER M5 ;
   RECT 223.056000 0.000000 223.080000 0.084000 ;
  END
 END tw_data[700]
 PIN tw_data[701]
  DIRECTION INPUT ;
  USE SIGNAL ;
  PORT
   LAYER M5 ;
   RECT 223.248000 0.000000 223.272000 0.084000 ;
  END
 END tw_data[701]
 PIN tw_data[702]
  DIRECTION INPUT ;
  USE SIGNAL ;
  PORT
   LAYER M5 ;
   RECT 223.440000 0.000000 223.464000 0.084000 ;
  END
 END tw_data[702]
 PIN tw_data[703]
  DIRECTION INPUT ;
  USE SIGNAL ;
  PORT
   LAYER M5 ;
   RECT 223.632000 0.000000 223.656000 0.084000 ;
  END
 END tw_data[703]
 PIN tw_data[704]
  DIRECTION INPUT ;
  USE SIGNAL ;
  PORT
   LAYER M5 ;
   RECT 223.824000 0.000000 223.848000 0.084000 ;
  END
 END tw_data[704]
 PIN tw_data[705]
  DIRECTION INPUT ;
  USE SIGNAL ;
  PORT
   LAYER M5 ;
   RECT 224.016000 0.000000 224.040000 0.084000 ;
  END
 END tw_data[705]
 PIN tw_data[706]
  DIRECTION INPUT ;
  USE SIGNAL ;
  PORT
   LAYER M5 ;
   RECT 224.208000 0.000000 224.232000 0.084000 ;
  END
 END tw_data[706]
 PIN tw_data[707]
  DIRECTION INPUT ;
  USE SIGNAL ;
  PORT
   LAYER M5 ;
   RECT 224.400000 0.000000 224.424000 0.084000 ;
  END
 END tw_data[707]
 PIN tw_data[708]
  DIRECTION INPUT ;
  USE SIGNAL ;
  PORT
   LAYER M5 ;
   RECT 224.592000 0.000000 224.616000 0.084000 ;
  END
 END tw_data[708]
 PIN tw_data[709]
  DIRECTION INPUT ;
  USE SIGNAL ;
  PORT
   LAYER M5 ;
   RECT 224.784000 0.000000 224.808000 0.084000 ;
  END
 END tw_data[709]
 PIN tw_data[710]
  DIRECTION INPUT ;
  USE SIGNAL ;
  PORT
   LAYER M5 ;
   RECT 224.976000 0.000000 225.000000 0.084000 ;
  END
 END tw_data[710]
 PIN tw_data[711]
  DIRECTION INPUT ;
  USE SIGNAL ;
  PORT
   LAYER M5 ;
   RECT 225.168000 0.000000 225.192000 0.084000 ;
  END
 END tw_data[711]
 PIN tw_data[712]
  DIRECTION INPUT ;
  USE SIGNAL ;
  PORT
   LAYER M5 ;
   RECT 225.360000 0.000000 225.384000 0.084000 ;
  END
 END tw_data[712]
 PIN tw_data[713]
  DIRECTION INPUT ;
  USE SIGNAL ;
  PORT
   LAYER M5 ;
   RECT 225.552000 0.000000 225.576000 0.084000 ;
  END
 END tw_data[713]
 PIN tw_data[714]
  DIRECTION INPUT ;
  USE SIGNAL ;
  PORT
   LAYER M5 ;
   RECT 225.744000 0.000000 225.768000 0.084000 ;
  END
 END tw_data[714]
 PIN tw_data[715]
  DIRECTION INPUT ;
  USE SIGNAL ;
  PORT
   LAYER M5 ;
   RECT 225.936000 0.000000 225.960000 0.084000 ;
  END
 END tw_data[715]
 PIN tw_data[716]
  DIRECTION INPUT ;
  USE SIGNAL ;
  PORT
   LAYER M5 ;
   RECT 226.128000 0.000000 226.152000 0.084000 ;
  END
 END tw_data[716]
 PIN tw_data[717]
  DIRECTION INPUT ;
  USE SIGNAL ;
  PORT
   LAYER M5 ;
   RECT 226.320000 0.000000 226.344000 0.084000 ;
  END
 END tw_data[717]
 PIN tw_data[718]
  DIRECTION INPUT ;
  USE SIGNAL ;
  PORT
   LAYER M5 ;
   RECT 226.512000 0.000000 226.536000 0.084000 ;
  END
 END tw_data[718]
 PIN tw_data[719]
  DIRECTION INPUT ;
  USE SIGNAL ;
  PORT
   LAYER M5 ;
   RECT 226.992000 0.000000 227.016000 0.084000 ;
  END
 END tw_data[719]
 PIN tw_data[720]
  DIRECTION INPUT ;
  USE SIGNAL ;
  PORT
   LAYER M5 ;
   RECT 227.184000 0.000000 227.208000 0.084000 ;
  END
 END tw_data[720]
 PIN tw_data[721]
  DIRECTION INPUT ;
  USE SIGNAL ;
  PORT
   LAYER M5 ;
   RECT 227.376000 0.000000 227.400000 0.084000 ;
  END
 END tw_data[721]
 PIN tw_data[722]
  DIRECTION INPUT ;
  USE SIGNAL ;
  PORT
   LAYER M5 ;
   RECT 227.568000 0.000000 227.592000 0.084000 ;
  END
 END tw_data[722]
 PIN tw_data[723]
  DIRECTION INPUT ;
  USE SIGNAL ;
  PORT
   LAYER M5 ;
   RECT 227.760000 0.000000 227.784000 0.084000 ;
  END
 END tw_data[723]
 PIN tw_data[724]
  DIRECTION INPUT ;
  USE SIGNAL ;
  PORT
   LAYER M5 ;
   RECT 227.952000 0.000000 227.976000 0.084000 ;
  END
 END tw_data[724]
 PIN tw_data[725]
  DIRECTION INPUT ;
  USE SIGNAL ;
  PORT
   LAYER M5 ;
   RECT 228.144000 0.000000 228.168000 0.084000 ;
  END
 END tw_data[725]
 PIN tw_data[726]
  DIRECTION INPUT ;
  USE SIGNAL ;
  PORT
   LAYER M5 ;
   RECT 228.336000 0.000000 228.360000 0.084000 ;
  END
 END tw_data[726]
 PIN tw_data[727]
  DIRECTION INPUT ;
  USE SIGNAL ;
  PORT
   LAYER M5 ;
   RECT 228.528000 0.000000 228.552000 0.084000 ;
  END
 END tw_data[727]
 PIN tw_data[728]
  DIRECTION INPUT ;
  USE SIGNAL ;
  PORT
   LAYER M5 ;
   RECT 228.720000 0.000000 228.744000 0.084000 ;
  END
 END tw_data[728]
 PIN tw_data[729]
  DIRECTION INPUT ;
  USE SIGNAL ;
  PORT
   LAYER M5 ;
   RECT 228.912000 0.000000 228.936000 0.084000 ;
  END
 END tw_data[729]
 PIN tw_data[730]
  DIRECTION INPUT ;
  USE SIGNAL ;
  PORT
   LAYER M5 ;
   RECT 229.104000 0.000000 229.128000 0.084000 ;
  END
 END tw_data[730]
 PIN tw_data[731]
  DIRECTION INPUT ;
  USE SIGNAL ;
  PORT
   LAYER M5 ;
   RECT 229.296000 0.000000 229.320000 0.084000 ;
  END
 END tw_data[731]
 PIN tw_data[732]
  DIRECTION INPUT ;
  USE SIGNAL ;
  PORT
   LAYER M5 ;
   RECT 229.488000 0.000000 229.512000 0.084000 ;
  END
 END tw_data[732]
 PIN tw_data[733]
  DIRECTION INPUT ;
  USE SIGNAL ;
  PORT
   LAYER M5 ;
   RECT 229.680000 0.000000 229.704000 0.084000 ;
  END
 END tw_data[733]
 PIN tw_data[734]
  DIRECTION INPUT ;
  USE SIGNAL ;
  PORT
   LAYER M5 ;
   RECT 229.872000 0.000000 229.896000 0.084000 ;
  END
 END tw_data[734]
 PIN tw_data[735]
  DIRECTION INPUT ;
  USE SIGNAL ;
  PORT
   LAYER M5 ;
   RECT 230.064000 0.000000 230.088000 0.084000 ;
  END
 END tw_data[735]
 PIN tw_data[736]
  DIRECTION INPUT ;
  USE SIGNAL ;
  PORT
   LAYER M5 ;
   RECT 230.256000 0.000000 230.280000 0.084000 ;
  END
 END tw_data[736]
 PIN tw_data[737]
  DIRECTION INPUT ;
  USE SIGNAL ;
  PORT
   LAYER M5 ;
   RECT 230.448000 0.000000 230.472000 0.084000 ;
  END
 END tw_data[737]
 PIN tw_data[738]
  DIRECTION INPUT ;
  USE SIGNAL ;
  PORT
   LAYER M5 ;
   RECT 230.640000 0.000000 230.664000 0.084000 ;
  END
 END tw_data[738]
 PIN tw_data[739]
  DIRECTION INPUT ;
  USE SIGNAL ;
  PORT
   LAYER M5 ;
   RECT 230.832000 0.000000 230.856000 0.084000 ;
  END
 END tw_data[739]
 PIN tw_data[740]
  DIRECTION INPUT ;
  USE SIGNAL ;
  PORT
   LAYER M5 ;
   RECT 231.312000 0.000000 231.336000 0.084000 ;
  END
 END tw_data[740]
 PIN tw_data[741]
  DIRECTION INPUT ;
  USE SIGNAL ;
  PORT
   LAYER M5 ;
   RECT 231.504000 0.000000 231.528000 0.084000 ;
  END
 END tw_data[741]
 PIN tw_data[742]
  DIRECTION INPUT ;
  USE SIGNAL ;
  PORT
   LAYER M5 ;
   RECT 231.696000 0.000000 231.720000 0.084000 ;
  END
 END tw_data[742]
 PIN tw_data[743]
  DIRECTION INPUT ;
  USE SIGNAL ;
  PORT
   LAYER M5 ;
   RECT 231.888000 0.000000 231.912000 0.084000 ;
  END
 END tw_data[743]
 PIN tw_data[744]
  DIRECTION INPUT ;
  USE SIGNAL ;
  PORT
   LAYER M5 ;
   RECT 232.080000 0.000000 232.104000 0.084000 ;
  END
 END tw_data[744]
 PIN tw_data[745]
  DIRECTION INPUT ;
  USE SIGNAL ;
  PORT
   LAYER M5 ;
   RECT 232.272000 0.000000 232.296000 0.084000 ;
  END
 END tw_data[745]
 PIN tw_data[746]
  DIRECTION INPUT ;
  USE SIGNAL ;
  PORT
   LAYER M5 ;
   RECT 232.464000 0.000000 232.488000 0.084000 ;
  END
 END tw_data[746]
 PIN tw_data[747]
  DIRECTION INPUT ;
  USE SIGNAL ;
  PORT
   LAYER M5 ;
   RECT 232.656000 0.000000 232.680000 0.084000 ;
  END
 END tw_data[747]
 PIN tw_data[748]
  DIRECTION INPUT ;
  USE SIGNAL ;
  PORT
   LAYER M5 ;
   RECT 232.848000 0.000000 232.872000 0.084000 ;
  END
 END tw_data[748]
 PIN tw_data[749]
  DIRECTION INPUT ;
  USE SIGNAL ;
  PORT
   LAYER M5 ;
   RECT 233.040000 0.000000 233.064000 0.084000 ;
  END
 END tw_data[749]
 PIN tw_data[750]
  DIRECTION INPUT ;
  USE SIGNAL ;
  PORT
   LAYER M5 ;
   RECT 233.232000 0.000000 233.256000 0.084000 ;
  END
 END tw_data[750]
 PIN tw_data[751]
  DIRECTION INPUT ;
  USE SIGNAL ;
  PORT
   LAYER M5 ;
   RECT 233.424000 0.000000 233.448000 0.084000 ;
  END
 END tw_data[751]
 PIN tw_data[752]
  DIRECTION INPUT ;
  USE SIGNAL ;
  PORT
   LAYER M5 ;
   RECT 233.616000 0.000000 233.640000 0.084000 ;
  END
 END tw_data[752]
 PIN tw_data[753]
  DIRECTION INPUT ;
  USE SIGNAL ;
  PORT
   LAYER M5 ;
   RECT 233.808000 0.000000 233.832000 0.084000 ;
  END
 END tw_data[753]
 PIN tw_data[754]
  DIRECTION INPUT ;
  USE SIGNAL ;
  PORT
   LAYER M5 ;
   RECT 234.000000 0.000000 234.024000 0.084000 ;
  END
 END tw_data[754]
 PIN tw_data[755]
  DIRECTION INPUT ;
  USE SIGNAL ;
  PORT
   LAYER M5 ;
   RECT 234.192000 0.000000 234.216000 0.084000 ;
  END
 END tw_data[755]
 PIN tw_data[756]
  DIRECTION INPUT ;
  USE SIGNAL ;
  PORT
   LAYER M5 ;
   RECT 234.384000 0.000000 234.408000 0.084000 ;
  END
 END tw_data[756]
 PIN tw_data[757]
  DIRECTION INPUT ;
  USE SIGNAL ;
  PORT
   LAYER M5 ;
   RECT 234.576000 0.000000 234.600000 0.084000 ;
  END
 END tw_data[757]
 PIN tw_data[758]
  DIRECTION INPUT ;
  USE SIGNAL ;
  PORT
   LAYER M5 ;
   RECT 234.768000 0.000000 234.792000 0.084000 ;
  END
 END tw_data[758]
 PIN tw_data[759]
  DIRECTION INPUT ;
  USE SIGNAL ;
  PORT
   LAYER M5 ;
   RECT 234.960000 0.000000 234.984000 0.084000 ;
  END
 END tw_data[759]
 PIN tw_data[760]
  DIRECTION INPUT ;
  USE SIGNAL ;
  PORT
   LAYER M5 ;
   RECT 235.152000 0.000000 235.176000 0.084000 ;
  END
 END tw_data[760]
 PIN tw_data[761]
  DIRECTION INPUT ;
  USE SIGNAL ;
  PORT
   LAYER M5 ;
   RECT 235.632000 0.000000 235.656000 0.084000 ;
  END
 END tw_data[761]
 PIN tw_data[762]
  DIRECTION INPUT ;
  USE SIGNAL ;
  PORT
   LAYER M5 ;
   RECT 235.824000 0.000000 235.848000 0.084000 ;
  END
 END tw_data[762]
 PIN tw_data[763]
  DIRECTION INPUT ;
  USE SIGNAL ;
  PORT
   LAYER M5 ;
   RECT 236.016000 0.000000 236.040000 0.084000 ;
  END
 END tw_data[763]
 PIN tw_data[764]
  DIRECTION INPUT ;
  USE SIGNAL ;
  PORT
   LAYER M5 ;
   RECT 236.208000 0.000000 236.232000 0.084000 ;
  END
 END tw_data[764]
 PIN tw_data[765]
  DIRECTION INPUT ;
  USE SIGNAL ;
  PORT
   LAYER M5 ;
   RECT 236.400000 0.000000 236.424000 0.084000 ;
  END
 END tw_data[765]
 PIN tw_data[766]
  DIRECTION INPUT ;
  USE SIGNAL ;
  PORT
   LAYER M5 ;
   RECT 236.592000 0.000000 236.616000 0.084000 ;
  END
 END tw_data[766]
 PIN tw_data[767]
  DIRECTION INPUT ;
  USE SIGNAL ;
  PORT
   LAYER M5 ;
   RECT 236.784000 0.000000 236.808000 0.084000 ;
  END
 END tw_data[767]
 PIN tw_data[768]
  DIRECTION INPUT ;
  USE SIGNAL ;
  PORT
   LAYER M5 ;
   RECT 236.976000 0.000000 237.000000 0.084000 ;
  END
 END tw_data[768]
 PIN tw_data[769]
  DIRECTION INPUT ;
  USE SIGNAL ;
  PORT
   LAYER M5 ;
   RECT 237.168000 0.000000 237.192000 0.084000 ;
  END
 END tw_data[769]
 PIN tw_data[770]
  DIRECTION INPUT ;
  USE SIGNAL ;
  PORT
   LAYER M5 ;
   RECT 237.360000 0.000000 237.384000 0.084000 ;
  END
 END tw_data[770]
 PIN tw_data[771]
  DIRECTION INPUT ;
  USE SIGNAL ;
  PORT
   LAYER M5 ;
   RECT 237.552000 0.000000 237.576000 0.084000 ;
  END
 END tw_data[771]
 PIN tw_data[772]
  DIRECTION INPUT ;
  USE SIGNAL ;
  PORT
   LAYER M5 ;
   RECT 237.744000 0.000000 237.768000 0.084000 ;
  END
 END tw_data[772]
 PIN tw_data[773]
  DIRECTION INPUT ;
  USE SIGNAL ;
  PORT
   LAYER M5 ;
   RECT 237.936000 0.000000 237.960000 0.084000 ;
  END
 END tw_data[773]
 PIN tw_data[774]
  DIRECTION INPUT ;
  USE SIGNAL ;
  PORT
   LAYER M5 ;
   RECT 238.128000 0.000000 238.152000 0.084000 ;
  END
 END tw_data[774]
 PIN tw_data[775]
  DIRECTION INPUT ;
  USE SIGNAL ;
  PORT
   LAYER M5 ;
   RECT 238.320000 0.000000 238.344000 0.084000 ;
  END
 END tw_data[775]
 PIN tw_data[776]
  DIRECTION INPUT ;
  USE SIGNAL ;
  PORT
   LAYER M5 ;
   RECT 238.512000 0.000000 238.536000 0.084000 ;
  END
 END tw_data[776]
 PIN tw_data[777]
  DIRECTION INPUT ;
  USE SIGNAL ;
  PORT
   LAYER M5 ;
   RECT 238.704000 0.000000 238.728000 0.084000 ;
  END
 END tw_data[777]
 PIN tw_data[778]
  DIRECTION INPUT ;
  USE SIGNAL ;
  PORT
   LAYER M5 ;
   RECT 238.896000 0.000000 238.920000 0.084000 ;
  END
 END tw_data[778]
 PIN tw_data[779]
  DIRECTION INPUT ;
  USE SIGNAL ;
  PORT
   LAYER M5 ;
   RECT 239.088000 0.000000 239.112000 0.084000 ;
  END
 END tw_data[779]
 PIN tw_data[780]
  DIRECTION INPUT ;
  USE SIGNAL ;
  PORT
   LAYER M5 ;
   RECT 239.280000 0.000000 239.304000 0.084000 ;
  END
 END tw_data[780]
 PIN tw_data[781]
  DIRECTION INPUT ;
  USE SIGNAL ;
  PORT
   LAYER M5 ;
   RECT 239.472000 0.000000 239.496000 0.084000 ;
  END
 END tw_data[781]
 PIN tw_data[782]
  DIRECTION INPUT ;
  USE SIGNAL ;
  PORT
   LAYER M5 ;
   RECT 239.952000 0.000000 239.976000 0.084000 ;
  END
 END tw_data[782]
 PIN tw_data[783]
  DIRECTION INPUT ;
  USE SIGNAL ;
  PORT
   LAYER M5 ;
   RECT 240.144000 0.000000 240.168000 0.084000 ;
  END
 END tw_data[783]
 PIN tw_data[784]
  DIRECTION INPUT ;
  USE SIGNAL ;
  PORT
   LAYER M5 ;
   RECT 240.336000 0.000000 240.360000 0.084000 ;
  END
 END tw_data[784]
 PIN tw_data[785]
  DIRECTION INPUT ;
  USE SIGNAL ;
  PORT
   LAYER M5 ;
   RECT 240.528000 0.000000 240.552000 0.084000 ;
  END
 END tw_data[785]
 PIN tw_data[786]
  DIRECTION INPUT ;
  USE SIGNAL ;
  PORT
   LAYER M5 ;
   RECT 240.720000 0.000000 240.744000 0.084000 ;
  END
 END tw_data[786]
 PIN tw_data[787]
  DIRECTION INPUT ;
  USE SIGNAL ;
  PORT
   LAYER M5 ;
   RECT 240.912000 0.000000 240.936000 0.084000 ;
  END
 END tw_data[787]
 PIN tw_data[788]
  DIRECTION INPUT ;
  USE SIGNAL ;
  PORT
   LAYER M5 ;
   RECT 241.104000 0.000000 241.128000 0.084000 ;
  END
 END tw_data[788]
 PIN tw_data[789]
  DIRECTION INPUT ;
  USE SIGNAL ;
  PORT
   LAYER M5 ;
   RECT 241.296000 0.000000 241.320000 0.084000 ;
  END
 END tw_data[789]
 PIN tw_data[790]
  DIRECTION INPUT ;
  USE SIGNAL ;
  PORT
   LAYER M5 ;
   RECT 241.488000 0.000000 241.512000 0.084000 ;
  END
 END tw_data[790]
 PIN tw_data[791]
  DIRECTION INPUT ;
  USE SIGNAL ;
  PORT
   LAYER M5 ;
   RECT 241.680000 0.000000 241.704000 0.084000 ;
  END
 END tw_data[791]
 PIN tw_data[792]
  DIRECTION INPUT ;
  USE SIGNAL ;
  PORT
   LAYER M5 ;
   RECT 241.872000 0.000000 241.896000 0.084000 ;
  END
 END tw_data[792]
 PIN tw_data[793]
  DIRECTION INPUT ;
  USE SIGNAL ;
  PORT
   LAYER M5 ;
   RECT 242.064000 0.000000 242.088000 0.084000 ;
  END
 END tw_data[793]
 PIN tw_data[794]
  DIRECTION INPUT ;
  USE SIGNAL ;
  PORT
   LAYER M5 ;
   RECT 242.256000 0.000000 242.280000 0.084000 ;
  END
 END tw_data[794]
 PIN tw_data[795]
  DIRECTION INPUT ;
  USE SIGNAL ;
  PORT
   LAYER M5 ;
   RECT 242.448000 0.000000 242.472000 0.084000 ;
  END
 END tw_data[795]
 PIN tw_data[796]
  DIRECTION INPUT ;
  USE SIGNAL ;
  PORT
   LAYER M5 ;
   RECT 242.640000 0.000000 242.664000 0.084000 ;
  END
 END tw_data[796]
 PIN tw_data[797]
  DIRECTION INPUT ;
  USE SIGNAL ;
  PORT
   LAYER M5 ;
   RECT 242.832000 0.000000 242.856000 0.084000 ;
  END
 END tw_data[797]
 PIN tw_data[798]
  DIRECTION INPUT ;
  USE SIGNAL ;
  PORT
   LAYER M5 ;
   RECT 243.024000 0.000000 243.048000 0.084000 ;
  END
 END tw_data[798]
 PIN tw_data[799]
  DIRECTION INPUT ;
  USE SIGNAL ;
  PORT
   LAYER M5 ;
   RECT 243.216000 0.000000 243.240000 0.084000 ;
  END
 END tw_data[799]
 PIN tw_data[800]
  DIRECTION INPUT ;
  USE SIGNAL ;
  PORT
   LAYER M5 ;
   RECT 243.408000 0.000000 243.432000 0.084000 ;
  END
 END tw_data[800]
 PIN tw_data[801]
  DIRECTION INPUT ;
  USE SIGNAL ;
  PORT
   LAYER M5 ;
   RECT 243.600000 0.000000 243.624000 0.084000 ;
  END
 END tw_data[801]
 PIN tw_data[802]
  DIRECTION INPUT ;
  USE SIGNAL ;
  PORT
   LAYER M5 ;
   RECT 243.792000 0.000000 243.816000 0.084000 ;
  END
 END tw_data[802]
 PIN tw_data[803]
  DIRECTION INPUT ;
  USE SIGNAL ;
  PORT
   LAYER M5 ;
   RECT 244.272000 0.000000 244.296000 0.084000 ;
  END
 END tw_data[803]
 PIN tw_data[804]
  DIRECTION INPUT ;
  USE SIGNAL ;
  PORT
   LAYER M5 ;
   RECT 244.464000 0.000000 244.488000 0.084000 ;
  END
 END tw_data[804]
 PIN tw_data[805]
  DIRECTION INPUT ;
  USE SIGNAL ;
  PORT
   LAYER M5 ;
   RECT 244.656000 0.000000 244.680000 0.084000 ;
  END
 END tw_data[805]
 PIN tw_data[806]
  DIRECTION INPUT ;
  USE SIGNAL ;
  PORT
   LAYER M5 ;
   RECT 244.848000 0.000000 244.872000 0.084000 ;
  END
 END tw_data[806]
 PIN tw_data[807]
  DIRECTION INPUT ;
  USE SIGNAL ;
  PORT
   LAYER M5 ;
   RECT 245.040000 0.000000 245.064000 0.084000 ;
  END
 END tw_data[807]
 PIN tw_data[808]
  DIRECTION INPUT ;
  USE SIGNAL ;
  PORT
   LAYER M5 ;
   RECT 245.232000 0.000000 245.256000 0.084000 ;
  END
 END tw_data[808]
 PIN tw_data[809]
  DIRECTION INPUT ;
  USE SIGNAL ;
  PORT
   LAYER M5 ;
   RECT 245.424000 0.000000 245.448000 0.084000 ;
  END
 END tw_data[809]
 PIN tw_data[810]
  DIRECTION INPUT ;
  USE SIGNAL ;
  PORT
   LAYER M5 ;
   RECT 245.616000 0.000000 245.640000 0.084000 ;
  END
 END tw_data[810]
 PIN tw_data[811]
  DIRECTION INPUT ;
  USE SIGNAL ;
  PORT
   LAYER M5 ;
   RECT 245.808000 0.000000 245.832000 0.084000 ;
  END
 END tw_data[811]
 PIN tw_data[812]
  DIRECTION INPUT ;
  USE SIGNAL ;
  PORT
   LAYER M5 ;
   RECT 246.000000 0.000000 246.024000 0.084000 ;
  END
 END tw_data[812]
 PIN tw_data[813]
  DIRECTION INPUT ;
  USE SIGNAL ;
  PORT
   LAYER M5 ;
   RECT 246.192000 0.000000 246.216000 0.084000 ;
  END
 END tw_data[813]
 PIN tw_data[814]
  DIRECTION INPUT ;
  USE SIGNAL ;
  PORT
   LAYER M5 ;
   RECT 246.384000 0.000000 246.408000 0.084000 ;
  END
 END tw_data[814]
 PIN tw_data[815]
  DIRECTION INPUT ;
  USE SIGNAL ;
  PORT
   LAYER M5 ;
   RECT 246.576000 0.000000 246.600000 0.084000 ;
  END
 END tw_data[815]
 PIN tw_data[816]
  DIRECTION INPUT ;
  USE SIGNAL ;
  PORT
   LAYER M5 ;
   RECT 246.768000 0.000000 246.792000 0.084000 ;
  END
 END tw_data[816]
 PIN tw_data[817]
  DIRECTION INPUT ;
  USE SIGNAL ;
  PORT
   LAYER M5 ;
   RECT 246.960000 0.000000 246.984000 0.084000 ;
  END
 END tw_data[817]
 PIN tw_data[818]
  DIRECTION INPUT ;
  USE SIGNAL ;
  PORT
   LAYER M5 ;
   RECT 247.152000 0.000000 247.176000 0.084000 ;
  END
 END tw_data[818]
 PIN tw_data[819]
  DIRECTION INPUT ;
  USE SIGNAL ;
  PORT
   LAYER M5 ;
   RECT 247.344000 0.000000 247.368000 0.084000 ;
  END
 END tw_data[819]
 PIN tw_data[820]
  DIRECTION INPUT ;
  USE SIGNAL ;
  PORT
   LAYER M5 ;
   RECT 247.536000 0.000000 247.560000 0.084000 ;
  END
 END tw_data[820]
 PIN tw_data[821]
  DIRECTION INPUT ;
  USE SIGNAL ;
  PORT
   LAYER M5 ;
   RECT 247.728000 0.000000 247.752000 0.084000 ;
  END
 END tw_data[821]
 PIN tw_data[822]
  DIRECTION INPUT ;
  USE SIGNAL ;
  PORT
   LAYER M5 ;
   RECT 247.920000 0.000000 247.944000 0.084000 ;
  END
 END tw_data[822]
 PIN tw_data[823]
  DIRECTION INPUT ;
  USE SIGNAL ;
  PORT
   LAYER M5 ;
   RECT 248.112000 0.000000 248.136000 0.084000 ;
  END
 END tw_data[823]
 PIN tw_data[824]
  DIRECTION INPUT ;
  USE SIGNAL ;
  PORT
   LAYER M5 ;
   RECT 248.592000 0.000000 248.616000 0.084000 ;
  END
 END tw_data[824]
 PIN tw_data[825]
  DIRECTION INPUT ;
  USE SIGNAL ;
  PORT
   LAYER M5 ;
   RECT 248.784000 0.000000 248.808000 0.084000 ;
  END
 END tw_data[825]
 PIN tw_data[826]
  DIRECTION INPUT ;
  USE SIGNAL ;
  PORT
   LAYER M5 ;
   RECT 248.976000 0.000000 249.000000 0.084000 ;
  END
 END tw_data[826]
 PIN tw_data[827]
  DIRECTION INPUT ;
  USE SIGNAL ;
  PORT
   LAYER M5 ;
   RECT 249.168000 0.000000 249.192000 0.084000 ;
  END
 END tw_data[827]
 PIN tw_data[828]
  DIRECTION INPUT ;
  USE SIGNAL ;
  PORT
   LAYER M5 ;
   RECT 249.360000 0.000000 249.384000 0.084000 ;
  END
 END tw_data[828]
 PIN tw_data[829]
  DIRECTION INPUT ;
  USE SIGNAL ;
  PORT
   LAYER M5 ;
   RECT 249.552000 0.000000 249.576000 0.084000 ;
  END
 END tw_data[829]
 PIN tw_data[830]
  DIRECTION INPUT ;
  USE SIGNAL ;
  PORT
   LAYER M5 ;
   RECT 249.744000 0.000000 249.768000 0.084000 ;
  END
 END tw_data[830]
 PIN tw_data[831]
  DIRECTION INPUT ;
  USE SIGNAL ;
  PORT
   LAYER M5 ;
   RECT 249.936000 0.000000 249.960000 0.084000 ;
  END
 END tw_data[831]
 PIN tw_data[832]
  DIRECTION INPUT ;
  USE SIGNAL ;
  PORT
   LAYER M5 ;
   RECT 250.128000 0.000000 250.152000 0.084000 ;
  END
 END tw_data[832]
 PIN tw_data[833]
  DIRECTION INPUT ;
  USE SIGNAL ;
  PORT
   LAYER M5 ;
   RECT 250.320000 0.000000 250.344000 0.084000 ;
  END
 END tw_data[833]
 PIN tw_data[834]
  DIRECTION INPUT ;
  USE SIGNAL ;
  PORT
   LAYER M5 ;
   RECT 250.512000 0.000000 250.536000 0.084000 ;
  END
 END tw_data[834]
 PIN tw_data[835]
  DIRECTION INPUT ;
  USE SIGNAL ;
  PORT
   LAYER M5 ;
   RECT 250.704000 0.000000 250.728000 0.084000 ;
  END
 END tw_data[835]
 PIN tw_data[836]
  DIRECTION INPUT ;
  USE SIGNAL ;
  PORT
   LAYER M5 ;
   RECT 250.896000 0.000000 250.920000 0.084000 ;
  END
 END tw_data[836]
 PIN tw_data[837]
  DIRECTION INPUT ;
  USE SIGNAL ;
  PORT
   LAYER M5 ;
   RECT 251.088000 0.000000 251.112000 0.084000 ;
  END
 END tw_data[837]
 PIN tw_data[838]
  DIRECTION INPUT ;
  USE SIGNAL ;
  PORT
   LAYER M5 ;
   RECT 251.280000 0.000000 251.304000 0.084000 ;
  END
 END tw_data[838]
 PIN tw_data[839]
  DIRECTION INPUT ;
  USE SIGNAL ;
  PORT
   LAYER M5 ;
   RECT 251.472000 0.000000 251.496000 0.084000 ;
  END
 END tw_data[839]
 PIN tw_data[840]
  DIRECTION INPUT ;
  USE SIGNAL ;
  PORT
   LAYER M5 ;
   RECT 251.664000 0.000000 251.688000 0.084000 ;
  END
 END tw_data[840]
 PIN tw_data[841]
  DIRECTION INPUT ;
  USE SIGNAL ;
  PORT
   LAYER M5 ;
   RECT 251.856000 0.000000 251.880000 0.084000 ;
  END
 END tw_data[841]
 PIN tw_data[842]
  DIRECTION INPUT ;
  USE SIGNAL ;
  PORT
   LAYER M5 ;
   RECT 252.048000 0.000000 252.072000 0.084000 ;
  END
 END tw_data[842]
 PIN tw_data[843]
  DIRECTION INPUT ;
  USE SIGNAL ;
  PORT
   LAYER M5 ;
   RECT 252.240000 0.000000 252.264000 0.084000 ;
  END
 END tw_data[843]
 PIN tw_data[844]
  DIRECTION INPUT ;
  USE SIGNAL ;
  PORT
   LAYER M5 ;
   RECT 252.432000 0.000000 252.456000 0.084000 ;
  END
 END tw_data[844]
 PIN tw_data[845]
  DIRECTION INPUT ;
  USE SIGNAL ;
  PORT
   LAYER M5 ;
   RECT 252.912000 0.000000 252.936000 0.084000 ;
  END
 END tw_data[845]
 PIN tw_data[846]
  DIRECTION INPUT ;
  USE SIGNAL ;
  PORT
   LAYER M5 ;
   RECT 253.104000 0.000000 253.128000 0.084000 ;
  END
 END tw_data[846]
 PIN tw_data[847]
  DIRECTION INPUT ;
  USE SIGNAL ;
  PORT
   LAYER M5 ;
   RECT 253.296000 0.000000 253.320000 0.084000 ;
  END
 END tw_data[847]
 PIN tw_data[848]
  DIRECTION INPUT ;
  USE SIGNAL ;
  PORT
   LAYER M5 ;
   RECT 253.488000 0.000000 253.512000 0.084000 ;
  END
 END tw_data[848]
 PIN tw_data[849]
  DIRECTION INPUT ;
  USE SIGNAL ;
  PORT
   LAYER M5 ;
   RECT 253.680000 0.000000 253.704000 0.084000 ;
  END
 END tw_data[849]
 PIN tw_data[850]
  DIRECTION INPUT ;
  USE SIGNAL ;
  PORT
   LAYER M5 ;
   RECT 253.872000 0.000000 253.896000 0.084000 ;
  END
 END tw_data[850]
 PIN tw_data[851]
  DIRECTION INPUT ;
  USE SIGNAL ;
  PORT
   LAYER M5 ;
   RECT 254.064000 0.000000 254.088000 0.084000 ;
  END
 END tw_data[851]
 PIN tw_data[852]
  DIRECTION INPUT ;
  USE SIGNAL ;
  PORT
   LAYER M5 ;
   RECT 254.256000 0.000000 254.280000 0.084000 ;
  END
 END tw_data[852]
 PIN tw_data[853]
  DIRECTION INPUT ;
  USE SIGNAL ;
  PORT
   LAYER M5 ;
   RECT 254.448000 0.000000 254.472000 0.084000 ;
  END
 END tw_data[853]
 PIN tw_data[854]
  DIRECTION INPUT ;
  USE SIGNAL ;
  PORT
   LAYER M5 ;
   RECT 254.640000 0.000000 254.664000 0.084000 ;
  END
 END tw_data[854]
 PIN tw_data[855]
  DIRECTION INPUT ;
  USE SIGNAL ;
  PORT
   LAYER M5 ;
   RECT 254.832000 0.000000 254.856000 0.084000 ;
  END
 END tw_data[855]
 PIN tw_data[856]
  DIRECTION INPUT ;
  USE SIGNAL ;
  PORT
   LAYER M5 ;
   RECT 255.024000 0.000000 255.048000 0.084000 ;
  END
 END tw_data[856]
 PIN tw_data[857]
  DIRECTION INPUT ;
  USE SIGNAL ;
  PORT
   LAYER M5 ;
   RECT 255.216000 0.000000 255.240000 0.084000 ;
  END
 END tw_data[857]
 PIN tw_data[858]
  DIRECTION INPUT ;
  USE SIGNAL ;
  PORT
   LAYER M5 ;
   RECT 255.408000 0.000000 255.432000 0.084000 ;
  END
 END tw_data[858]
 PIN tw_data[859]
  DIRECTION INPUT ;
  USE SIGNAL ;
  PORT
   LAYER M5 ;
   RECT 255.600000 0.000000 255.624000 0.084000 ;
  END
 END tw_data[859]
 PIN tw_data[860]
  DIRECTION INPUT ;
  USE SIGNAL ;
  PORT
   LAYER M5 ;
   RECT 255.792000 0.000000 255.816000 0.084000 ;
  END
 END tw_data[860]
 PIN tw_data[861]
  DIRECTION INPUT ;
  USE SIGNAL ;
  PORT
   LAYER M5 ;
   RECT 255.984000 0.000000 256.008000 0.084000 ;
  END
 END tw_data[861]
 PIN tw_data[862]
  DIRECTION INPUT ;
  USE SIGNAL ;
  PORT
   LAYER M5 ;
   RECT 256.176000 0.000000 256.200000 0.084000 ;
  END
 END tw_data[862]
 PIN tw_data[863]
  DIRECTION INPUT ;
  USE SIGNAL ;
  PORT
   LAYER M5 ;
   RECT 256.368000 0.000000 256.392000 0.084000 ;
  END
 END tw_data[863]
 PIN tw_data[864]
  DIRECTION INPUT ;
  USE SIGNAL ;
  PORT
   LAYER M5 ;
   RECT 256.560000 0.000000 256.584000 0.084000 ;
  END
 END tw_data[864]
 PIN tw_data[865]
  DIRECTION INPUT ;
  USE SIGNAL ;
  PORT
   LAYER M5 ;
   RECT 256.752000 0.000000 256.776000 0.084000 ;
  END
 END tw_data[865]
 PIN tw_data[866]
  DIRECTION INPUT ;
  USE SIGNAL ;
  PORT
   LAYER M5 ;
   RECT 257.232000 0.000000 257.256000 0.084000 ;
  END
 END tw_data[866]
 PIN tw_data[867]
  DIRECTION INPUT ;
  USE SIGNAL ;
  PORT
   LAYER M5 ;
   RECT 257.424000 0.000000 257.448000 0.084000 ;
  END
 END tw_data[867]
 PIN tw_data[868]
  DIRECTION INPUT ;
  USE SIGNAL ;
  PORT
   LAYER M5 ;
   RECT 257.616000 0.000000 257.640000 0.084000 ;
  END
 END tw_data[868]
 PIN tw_data[869]
  DIRECTION INPUT ;
  USE SIGNAL ;
  PORT
   LAYER M5 ;
   RECT 257.808000 0.000000 257.832000 0.084000 ;
  END
 END tw_data[869]
 PIN tw_data[870]
  DIRECTION INPUT ;
  USE SIGNAL ;
  PORT
   LAYER M5 ;
   RECT 258.000000 0.000000 258.024000 0.084000 ;
  END
 END tw_data[870]
 PIN tw_data[871]
  DIRECTION INPUT ;
  USE SIGNAL ;
  PORT
   LAYER M5 ;
   RECT 258.192000 0.000000 258.216000 0.084000 ;
  END
 END tw_data[871]
 PIN tw_data[872]
  DIRECTION INPUT ;
  USE SIGNAL ;
  PORT
   LAYER M5 ;
   RECT 258.384000 0.000000 258.408000 0.084000 ;
  END
 END tw_data[872]
 PIN tw_data[873]
  DIRECTION INPUT ;
  USE SIGNAL ;
  PORT
   LAYER M5 ;
   RECT 258.576000 0.000000 258.600000 0.084000 ;
  END
 END tw_data[873]
 PIN tw_data[874]
  DIRECTION INPUT ;
  USE SIGNAL ;
  PORT
   LAYER M5 ;
   RECT 258.768000 0.000000 258.792000 0.084000 ;
  END
 END tw_data[874]
 PIN tw_data[875]
  DIRECTION INPUT ;
  USE SIGNAL ;
  PORT
   LAYER M5 ;
   RECT 258.960000 0.000000 258.984000 0.084000 ;
  END
 END tw_data[875]
 PIN tw_data[876]
  DIRECTION INPUT ;
  USE SIGNAL ;
  PORT
   LAYER M5 ;
   RECT 259.152000 0.000000 259.176000 0.084000 ;
  END
 END tw_data[876]
 PIN tw_data[877]
  DIRECTION INPUT ;
  USE SIGNAL ;
  PORT
   LAYER M5 ;
   RECT 259.344000 0.000000 259.368000 0.084000 ;
  END
 END tw_data[877]
 PIN tw_data[878]
  DIRECTION INPUT ;
  USE SIGNAL ;
  PORT
   LAYER M5 ;
   RECT 259.536000 0.000000 259.560000 0.084000 ;
  END
 END tw_data[878]
 PIN tw_data[879]
  DIRECTION INPUT ;
  USE SIGNAL ;
  PORT
   LAYER M5 ;
   RECT 259.728000 0.000000 259.752000 0.084000 ;
  END
 END tw_data[879]
 PIN tw_data[880]
  DIRECTION INPUT ;
  USE SIGNAL ;
  PORT
   LAYER M5 ;
   RECT 259.920000 0.000000 259.944000 0.084000 ;
  END
 END tw_data[880]
 PIN tw_data[881]
  DIRECTION INPUT ;
  USE SIGNAL ;
  PORT
   LAYER M5 ;
   RECT 260.112000 0.000000 260.136000 0.084000 ;
  END
 END tw_data[881]
 PIN tw_data[882]
  DIRECTION INPUT ;
  USE SIGNAL ;
  PORT
   LAYER M5 ;
   RECT 260.304000 0.000000 260.328000 0.084000 ;
  END
 END tw_data[882]
 PIN tw_data[883]
  DIRECTION INPUT ;
  USE SIGNAL ;
  PORT
   LAYER M5 ;
   RECT 260.496000 0.000000 260.520000 0.084000 ;
  END
 END tw_data[883]
 PIN tw_data[884]
  DIRECTION INPUT ;
  USE SIGNAL ;
  PORT
   LAYER M5 ;
   RECT 260.688000 0.000000 260.712000 0.084000 ;
  END
 END tw_data[884]
 PIN tw_data[885]
  DIRECTION INPUT ;
  USE SIGNAL ;
  PORT
   LAYER M5 ;
   RECT 260.880000 0.000000 260.904000 0.084000 ;
  END
 END tw_data[885]
 PIN tw_data[886]
  DIRECTION INPUT ;
  USE SIGNAL ;
  PORT
   LAYER M5 ;
   RECT 261.072000 0.000000 261.096000 0.084000 ;
  END
 END tw_data[886]
 PIN tw_data[887]
  DIRECTION INPUT ;
  USE SIGNAL ;
  PORT
   LAYER M5 ;
   RECT 261.552000 0.000000 261.576000 0.084000 ;
  END
 END tw_data[887]
 PIN tw_data[888]
  DIRECTION INPUT ;
  USE SIGNAL ;
  PORT
   LAYER M5 ;
   RECT 261.744000 0.000000 261.768000 0.084000 ;
  END
 END tw_data[888]
 PIN tw_data[889]
  DIRECTION INPUT ;
  USE SIGNAL ;
  PORT
   LAYER M5 ;
   RECT 261.936000 0.000000 261.960000 0.084000 ;
  END
 END tw_data[889]
 PIN tw_data[890]
  DIRECTION INPUT ;
  USE SIGNAL ;
  PORT
   LAYER M5 ;
   RECT 262.128000 0.000000 262.152000 0.084000 ;
  END
 END tw_data[890]
 PIN tw_data[891]
  DIRECTION INPUT ;
  USE SIGNAL ;
  PORT
   LAYER M5 ;
   RECT 262.320000 0.000000 262.344000 0.084000 ;
  END
 END tw_data[891]
 PIN tw_data[892]
  DIRECTION INPUT ;
  USE SIGNAL ;
  PORT
   LAYER M5 ;
   RECT 262.512000 0.000000 262.536000 0.084000 ;
  END
 END tw_data[892]
 PIN tw_data[893]
  DIRECTION INPUT ;
  USE SIGNAL ;
  PORT
   LAYER M5 ;
   RECT 262.704000 0.000000 262.728000 0.084000 ;
  END
 END tw_data[893]
 PIN tw_data[894]
  DIRECTION INPUT ;
  USE SIGNAL ;
  PORT
   LAYER M5 ;
   RECT 262.896000 0.000000 262.920000 0.084000 ;
  END
 END tw_data[894]
 PIN tw_data[895]
  DIRECTION INPUT ;
  USE SIGNAL ;
  PORT
   LAYER M5 ;
   RECT 263.088000 0.000000 263.112000 0.084000 ;
  END
 END tw_data[895]
 PIN tw_data[896]
  DIRECTION INPUT ;
  USE SIGNAL ;
  PORT
   LAYER M5 ;
   RECT 263.280000 0.000000 263.304000 0.084000 ;
  END
 END tw_data[896]
 PIN tw_data[897]
  DIRECTION INPUT ;
  USE SIGNAL ;
  PORT
   LAYER M5 ;
   RECT 263.472000 0.000000 263.496000 0.084000 ;
  END
 END tw_data[897]
 PIN tw_data[898]
  DIRECTION INPUT ;
  USE SIGNAL ;
  PORT
   LAYER M5 ;
   RECT 263.664000 0.000000 263.688000 0.084000 ;
  END
 END tw_data[898]
 PIN tw_data[899]
  DIRECTION INPUT ;
  USE SIGNAL ;
  PORT
   LAYER M5 ;
   RECT 263.856000 0.000000 263.880000 0.084000 ;
  END
 END tw_data[899]
 PIN tw_data[900]
  DIRECTION INPUT ;
  USE SIGNAL ;
  PORT
   LAYER M5 ;
   RECT 264.048000 0.000000 264.072000 0.084000 ;
  END
 END tw_data[900]
 PIN tw_data[901]
  DIRECTION INPUT ;
  USE SIGNAL ;
  PORT
   LAYER M5 ;
   RECT 264.240000 0.000000 264.264000 0.084000 ;
  END
 END tw_data[901]
 PIN tw_data[902]
  DIRECTION INPUT ;
  USE SIGNAL ;
  PORT
   LAYER M5 ;
   RECT 264.432000 0.000000 264.456000 0.084000 ;
  END
 END tw_data[902]
 PIN tw_data[903]
  DIRECTION INPUT ;
  USE SIGNAL ;
  PORT
   LAYER M5 ;
   RECT 264.624000 0.000000 264.648000 0.084000 ;
  END
 END tw_data[903]
 PIN tw_data[904]
  DIRECTION INPUT ;
  USE SIGNAL ;
  PORT
   LAYER M5 ;
   RECT 264.816000 0.000000 264.840000 0.084000 ;
  END
 END tw_data[904]
 PIN tw_data[905]
  DIRECTION INPUT ;
  USE SIGNAL ;
  PORT
   LAYER M5 ;
   RECT 265.008000 0.000000 265.032000 0.084000 ;
  END
 END tw_data[905]
 PIN tw_data[906]
  DIRECTION INPUT ;
  USE SIGNAL ;
  PORT
   LAYER M5 ;
   RECT 265.200000 0.000000 265.224000 0.084000 ;
  END
 END tw_data[906]
 PIN tw_data[907]
  DIRECTION INPUT ;
  USE SIGNAL ;
  PORT
   LAYER M5 ;
   RECT 265.392000 0.000000 265.416000 0.084000 ;
  END
 END tw_data[907]
 PIN tw_data[908]
  DIRECTION INPUT ;
  USE SIGNAL ;
  PORT
   LAYER M5 ;
   RECT 265.872000 0.000000 265.896000 0.084000 ;
  END
 END tw_data[908]
 PIN tw_data[909]
  DIRECTION INPUT ;
  USE SIGNAL ;
  PORT
   LAYER M5 ;
   RECT 266.064000 0.000000 266.088000 0.084000 ;
  END
 END tw_data[909]
 PIN tw_data[910]
  DIRECTION INPUT ;
  USE SIGNAL ;
  PORT
   LAYER M5 ;
   RECT 266.256000 0.000000 266.280000 0.084000 ;
  END
 END tw_data[910]
 PIN tw_data[911]
  DIRECTION INPUT ;
  USE SIGNAL ;
  PORT
   LAYER M5 ;
   RECT 266.448000 0.000000 266.472000 0.084000 ;
  END
 END tw_data[911]
 PIN tw_data[912]
  DIRECTION INPUT ;
  USE SIGNAL ;
  PORT
   LAYER M5 ;
   RECT 266.640000 0.000000 266.664000 0.084000 ;
  END
 END tw_data[912]
 PIN tw_data[913]
  DIRECTION INPUT ;
  USE SIGNAL ;
  PORT
   LAYER M5 ;
   RECT 266.832000 0.000000 266.856000 0.084000 ;
  END
 END tw_data[913]
 PIN tw_data[914]
  DIRECTION INPUT ;
  USE SIGNAL ;
  PORT
   LAYER M5 ;
   RECT 267.024000 0.000000 267.048000 0.084000 ;
  END
 END tw_data[914]
 PIN tw_data[915]
  DIRECTION INPUT ;
  USE SIGNAL ;
  PORT
   LAYER M5 ;
   RECT 267.216000 0.000000 267.240000 0.084000 ;
  END
 END tw_data[915]
 PIN tw_data[916]
  DIRECTION INPUT ;
  USE SIGNAL ;
  PORT
   LAYER M5 ;
   RECT 267.408000 0.000000 267.432000 0.084000 ;
  END
 END tw_data[916]
 PIN tw_data[917]
  DIRECTION INPUT ;
  USE SIGNAL ;
  PORT
   LAYER M5 ;
   RECT 267.600000 0.000000 267.624000 0.084000 ;
  END
 END tw_data[917]
 PIN tw_data[918]
  DIRECTION INPUT ;
  USE SIGNAL ;
  PORT
   LAYER M5 ;
   RECT 267.792000 0.000000 267.816000 0.084000 ;
  END
 END tw_data[918]
 PIN tw_data[919]
  DIRECTION INPUT ;
  USE SIGNAL ;
  PORT
   LAYER M5 ;
   RECT 267.984000 0.000000 268.008000 0.084000 ;
  END
 END tw_data[919]
 PIN tw_data[920]
  DIRECTION INPUT ;
  USE SIGNAL ;
  PORT
   LAYER M5 ;
   RECT 268.176000 0.000000 268.200000 0.084000 ;
  END
 END tw_data[920]
 PIN tw_data[921]
  DIRECTION INPUT ;
  USE SIGNAL ;
  PORT
   LAYER M5 ;
   RECT 268.368000 0.000000 268.392000 0.084000 ;
  END
 END tw_data[921]
 PIN tw_data[922]
  DIRECTION INPUT ;
  USE SIGNAL ;
  PORT
   LAYER M5 ;
   RECT 268.560000 0.000000 268.584000 0.084000 ;
  END
 END tw_data[922]
 PIN tw_data[923]
  DIRECTION INPUT ;
  USE SIGNAL ;
  PORT
   LAYER M5 ;
   RECT 268.752000 0.000000 268.776000 0.084000 ;
  END
 END tw_data[923]
 PIN tw_data[924]
  DIRECTION INPUT ;
  USE SIGNAL ;
  PORT
   LAYER M5 ;
   RECT 268.944000 0.000000 268.968000 0.084000 ;
  END
 END tw_data[924]
 PIN tw_data[925]
  DIRECTION INPUT ;
  USE SIGNAL ;
  PORT
   LAYER M5 ;
   RECT 269.136000 0.000000 269.160000 0.084000 ;
  END
 END tw_data[925]
 PIN tw_data[926]
  DIRECTION INPUT ;
  USE SIGNAL ;
  PORT
   LAYER M5 ;
   RECT 269.328000 0.000000 269.352000 0.084000 ;
  END
 END tw_data[926]
 PIN tw_data[927]
  DIRECTION INPUT ;
  USE SIGNAL ;
  PORT
   LAYER M5 ;
   RECT 269.520000 0.000000 269.544000 0.084000 ;
  END
 END tw_data[927]
 PIN tw_data[928]
  DIRECTION INPUT ;
  USE SIGNAL ;
  PORT
   LAYER M5 ;
   RECT 269.712000 0.000000 269.736000 0.084000 ;
  END
 END tw_data[928]
 PIN tw_data[929]
  DIRECTION INPUT ;
  USE SIGNAL ;
  PORT
   LAYER M5 ;
   RECT 270.192000 0.000000 270.216000 0.084000 ;
  END
 END tw_data[929]
 PIN tw_data[930]
  DIRECTION INPUT ;
  USE SIGNAL ;
  PORT
   LAYER M5 ;
   RECT 270.384000 0.000000 270.408000 0.084000 ;
  END
 END tw_data[930]
 PIN tw_data[931]
  DIRECTION INPUT ;
  USE SIGNAL ;
  PORT
   LAYER M5 ;
   RECT 270.576000 0.000000 270.600000 0.084000 ;
  END
 END tw_data[931]
 PIN tw_data[932]
  DIRECTION INPUT ;
  USE SIGNAL ;
  PORT
   LAYER M5 ;
   RECT 270.768000 0.000000 270.792000 0.084000 ;
  END
 END tw_data[932]
 PIN tw_data[933]
  DIRECTION INPUT ;
  USE SIGNAL ;
  PORT
   LAYER M5 ;
   RECT 270.960000 0.000000 270.984000 0.084000 ;
  END
 END tw_data[933]
 PIN tw_data[934]
  DIRECTION INPUT ;
  USE SIGNAL ;
  PORT
   LAYER M5 ;
   RECT 271.152000 0.000000 271.176000 0.084000 ;
  END
 END tw_data[934]
 PIN tw_data[935]
  DIRECTION INPUT ;
  USE SIGNAL ;
  PORT
   LAYER M5 ;
   RECT 271.344000 0.000000 271.368000 0.084000 ;
  END
 END tw_data[935]
 PIN tw_data[936]
  DIRECTION INPUT ;
  USE SIGNAL ;
  PORT
   LAYER M5 ;
   RECT 271.536000 0.000000 271.560000 0.084000 ;
  END
 END tw_data[936]
 PIN tw_data[937]
  DIRECTION INPUT ;
  USE SIGNAL ;
  PORT
   LAYER M5 ;
   RECT 271.728000 0.000000 271.752000 0.084000 ;
  END
 END tw_data[937]
 PIN tw_data[938]
  DIRECTION INPUT ;
  USE SIGNAL ;
  PORT
   LAYER M5 ;
   RECT 271.920000 0.000000 271.944000 0.084000 ;
  END
 END tw_data[938]
 PIN tw_data[939]
  DIRECTION INPUT ;
  USE SIGNAL ;
  PORT
   LAYER M5 ;
   RECT 272.112000 0.000000 272.136000 0.084000 ;
  END
 END tw_data[939]
 PIN tw_data[940]
  DIRECTION INPUT ;
  USE SIGNAL ;
  PORT
   LAYER M5 ;
   RECT 272.304000 0.000000 272.328000 0.084000 ;
  END
 END tw_data[940]
 PIN tw_data[941]
  DIRECTION INPUT ;
  USE SIGNAL ;
  PORT
   LAYER M5 ;
   RECT 272.496000 0.000000 272.520000 0.084000 ;
  END
 END tw_data[941]
 PIN tw_data[942]
  DIRECTION INPUT ;
  USE SIGNAL ;
  PORT
   LAYER M5 ;
   RECT 272.688000 0.000000 272.712000 0.084000 ;
  END
 END tw_data[942]
 PIN tw_data[943]
  DIRECTION INPUT ;
  USE SIGNAL ;
  PORT
   LAYER M5 ;
   RECT 272.880000 0.000000 272.904000 0.084000 ;
  END
 END tw_data[943]
 PIN tw_data[944]
  DIRECTION INPUT ;
  USE SIGNAL ;
  PORT
   LAYER M5 ;
   RECT 273.072000 0.000000 273.096000 0.084000 ;
  END
 END tw_data[944]
 PIN tw_data[945]
  DIRECTION INPUT ;
  USE SIGNAL ;
  PORT
   LAYER M5 ;
   RECT 273.264000 0.000000 273.288000 0.084000 ;
  END
 END tw_data[945]
 PIN tw_data[946]
  DIRECTION INPUT ;
  USE SIGNAL ;
  PORT
   LAYER M5 ;
   RECT 273.456000 0.000000 273.480000 0.084000 ;
  END
 END tw_data[946]
 PIN tw_data[947]
  DIRECTION INPUT ;
  USE SIGNAL ;
  PORT
   LAYER M5 ;
   RECT 273.648000 0.000000 273.672000 0.084000 ;
  END
 END tw_data[947]
 PIN tw_data[948]
  DIRECTION INPUT ;
  USE SIGNAL ;
  PORT
   LAYER M5 ;
   RECT 273.840000 0.000000 273.864000 0.084000 ;
  END
 END tw_data[948]
 PIN tw_data[949]
  DIRECTION INPUT ;
  USE SIGNAL ;
  PORT
   LAYER M5 ;
   RECT 274.032000 0.000000 274.056000 0.084000 ;
  END
 END tw_data[949]
 PIN tw_data[950]
  DIRECTION INPUT ;
  USE SIGNAL ;
  PORT
   LAYER M5 ;
   RECT 274.512000 0.000000 274.536000 0.084000 ;
  END
 END tw_data[950]
 PIN tw_data[951]
  DIRECTION INPUT ;
  USE SIGNAL ;
  PORT
   LAYER M5 ;
   RECT 274.704000 0.000000 274.728000 0.084000 ;
  END
 END tw_data[951]
 PIN tw_data[952]
  DIRECTION INPUT ;
  USE SIGNAL ;
  PORT
   LAYER M5 ;
   RECT 274.896000 0.000000 274.920000 0.084000 ;
  END
 END tw_data[952]
 PIN tw_data[953]
  DIRECTION INPUT ;
  USE SIGNAL ;
  PORT
   LAYER M5 ;
   RECT 275.088000 0.000000 275.112000 0.084000 ;
  END
 END tw_data[953]
 PIN tw_data[954]
  DIRECTION INPUT ;
  USE SIGNAL ;
  PORT
   LAYER M5 ;
   RECT 275.280000 0.000000 275.304000 0.084000 ;
  END
 END tw_data[954]
 PIN tw_data[955]
  DIRECTION INPUT ;
  USE SIGNAL ;
  PORT
   LAYER M5 ;
   RECT 275.472000 0.000000 275.496000 0.084000 ;
  END
 END tw_data[955]
 PIN tw_data[956]
  DIRECTION INPUT ;
  USE SIGNAL ;
  PORT
   LAYER M5 ;
   RECT 275.664000 0.000000 275.688000 0.084000 ;
  END
 END tw_data[956]
 PIN tw_data[957]
  DIRECTION INPUT ;
  USE SIGNAL ;
  PORT
   LAYER M5 ;
   RECT 275.856000 0.000000 275.880000 0.084000 ;
  END
 END tw_data[957]
 PIN tw_data[958]
  DIRECTION INPUT ;
  USE SIGNAL ;
  PORT
   LAYER M5 ;
   RECT 276.048000 0.000000 276.072000 0.084000 ;
  END
 END tw_data[958]
 PIN tw_data[959]
  DIRECTION INPUT ;
  USE SIGNAL ;
  PORT
   LAYER M5 ;
   RECT 276.240000 0.000000 276.264000 0.084000 ;
  END
 END tw_data[959]
 PIN tw_data[960]
  DIRECTION INPUT ;
  USE SIGNAL ;
  PORT
   LAYER M5 ;
   RECT 276.432000 0.000000 276.456000 0.084000 ;
  END
 END tw_data[960]
 PIN tw_data[961]
  DIRECTION INPUT ;
  USE SIGNAL ;
  PORT
   LAYER M5 ;
   RECT 276.624000 0.000000 276.648000 0.084000 ;
  END
 END tw_data[961]
 PIN tw_data[962]
  DIRECTION INPUT ;
  USE SIGNAL ;
  PORT
   LAYER M5 ;
   RECT 276.816000 0.000000 276.840000 0.084000 ;
  END
 END tw_data[962]
 PIN tw_data[963]
  DIRECTION INPUT ;
  USE SIGNAL ;
  PORT
   LAYER M5 ;
   RECT 277.008000 0.000000 277.032000 0.084000 ;
  END
 END tw_data[963]
 PIN tw_data[964]
  DIRECTION INPUT ;
  USE SIGNAL ;
  PORT
   LAYER M5 ;
   RECT 277.200000 0.000000 277.224000 0.084000 ;
  END
 END tw_data[964]
 PIN tw_data[965]
  DIRECTION INPUT ;
  USE SIGNAL ;
  PORT
   LAYER M5 ;
   RECT 277.392000 0.000000 277.416000 0.084000 ;
  END
 END tw_data[965]
 PIN tw_data[966]
  DIRECTION INPUT ;
  USE SIGNAL ;
  PORT
   LAYER M5 ;
   RECT 277.584000 0.000000 277.608000 0.084000 ;
  END
 END tw_data[966]
 PIN tw_data[967]
  DIRECTION INPUT ;
  USE SIGNAL ;
  PORT
   LAYER M5 ;
   RECT 277.776000 0.000000 277.800000 0.084000 ;
  END
 END tw_data[967]
 PIN tw_data[968]
  DIRECTION INPUT ;
  USE SIGNAL ;
  PORT
   LAYER M5 ;
   RECT 277.968000 0.000000 277.992000 0.084000 ;
  END
 END tw_data[968]
 PIN tw_data[969]
  DIRECTION INPUT ;
  USE SIGNAL ;
  PORT
   LAYER M5 ;
   RECT 278.160000 0.000000 278.184000 0.084000 ;
  END
 END tw_data[969]
 PIN tw_data[970]
  DIRECTION INPUT ;
  USE SIGNAL ;
  PORT
   LAYER M5 ;
   RECT 278.352000 0.000000 278.376000 0.084000 ;
  END
 END tw_data[970]
 PIN tw_data[971]
  DIRECTION INPUT ;
  USE SIGNAL ;
  PORT
   LAYER M5 ;
   RECT 278.832000 0.000000 278.856000 0.084000 ;
  END
 END tw_data[971]
 PIN tw_data[972]
  DIRECTION INPUT ;
  USE SIGNAL ;
  PORT
   LAYER M5 ;
   RECT 279.024000 0.000000 279.048000 0.084000 ;
  END
 END tw_data[972]
 PIN tw_data[973]
  DIRECTION INPUT ;
  USE SIGNAL ;
  PORT
   LAYER M5 ;
   RECT 279.216000 0.000000 279.240000 0.084000 ;
  END
 END tw_data[973]
 PIN tw_data[974]
  DIRECTION INPUT ;
  USE SIGNAL ;
  PORT
   LAYER M5 ;
   RECT 279.408000 0.000000 279.432000 0.084000 ;
  END
 END tw_data[974]
 PIN tw_data[975]
  DIRECTION INPUT ;
  USE SIGNAL ;
  PORT
   LAYER M5 ;
   RECT 279.600000 0.000000 279.624000 0.084000 ;
  END
 END tw_data[975]
 PIN tw_data[976]
  DIRECTION INPUT ;
  USE SIGNAL ;
  PORT
   LAYER M5 ;
   RECT 279.792000 0.000000 279.816000 0.084000 ;
  END
 END tw_data[976]
 PIN tw_data[977]
  DIRECTION INPUT ;
  USE SIGNAL ;
  PORT
   LAYER M5 ;
   RECT 279.984000 0.000000 280.008000 0.084000 ;
  END
 END tw_data[977]
 PIN tw_data[978]
  DIRECTION INPUT ;
  USE SIGNAL ;
  PORT
   LAYER M5 ;
   RECT 280.176000 0.000000 280.200000 0.084000 ;
  END
 END tw_data[978]
 PIN tw_data[979]
  DIRECTION INPUT ;
  USE SIGNAL ;
  PORT
   LAYER M5 ;
   RECT 280.368000 0.000000 280.392000 0.084000 ;
  END
 END tw_data[979]
 PIN tw_data[980]
  DIRECTION INPUT ;
  USE SIGNAL ;
  PORT
   LAYER M5 ;
   RECT 280.560000 0.000000 280.584000 0.084000 ;
  END
 END tw_data[980]
 PIN tw_data[981]
  DIRECTION INPUT ;
  USE SIGNAL ;
  PORT
   LAYER M5 ;
   RECT 280.752000 0.000000 280.776000 0.084000 ;
  END
 END tw_data[981]
 PIN tw_data[982]
  DIRECTION INPUT ;
  USE SIGNAL ;
  PORT
   LAYER M5 ;
   RECT 280.944000 0.000000 280.968000 0.084000 ;
  END
 END tw_data[982]
 PIN tw_data[983]
  DIRECTION INPUT ;
  USE SIGNAL ;
  PORT
   LAYER M5 ;
   RECT 281.136000 0.000000 281.160000 0.084000 ;
  END
 END tw_data[983]
 PIN tw_data[984]
  DIRECTION INPUT ;
  USE SIGNAL ;
  PORT
   LAYER M5 ;
   RECT 281.328000 0.000000 281.352000 0.084000 ;
  END
 END tw_data[984]
 PIN tw_data[985]
  DIRECTION INPUT ;
  USE SIGNAL ;
  PORT
   LAYER M5 ;
   RECT 281.520000 0.000000 281.544000 0.084000 ;
  END
 END tw_data[985]
 PIN tw_data[986]
  DIRECTION INPUT ;
  USE SIGNAL ;
  PORT
   LAYER M5 ;
   RECT 281.712000 0.000000 281.736000 0.084000 ;
  END
 END tw_data[986]
 PIN tw_data[987]
  DIRECTION INPUT ;
  USE SIGNAL ;
  PORT
   LAYER M5 ;
   RECT 281.904000 0.000000 281.928000 0.084000 ;
  END
 END tw_data[987]
 PIN tw_data[988]
  DIRECTION INPUT ;
  USE SIGNAL ;
  PORT
   LAYER M5 ;
   RECT 282.096000 0.000000 282.120000 0.084000 ;
  END
 END tw_data[988]
 PIN tw_data[989]
  DIRECTION INPUT ;
  USE SIGNAL ;
  PORT
   LAYER M5 ;
   RECT 282.288000 0.000000 282.312000 0.084000 ;
  END
 END tw_data[989]
 PIN tw_data[990]
  DIRECTION INPUT ;
  USE SIGNAL ;
  PORT
   LAYER M5 ;
   RECT 282.480000 0.000000 282.504000 0.084000 ;
  END
 END tw_data[990]
 PIN tw_data[991]
  DIRECTION INPUT ;
  USE SIGNAL ;
  PORT
   LAYER M5 ;
   RECT 282.672000 0.000000 282.696000 0.084000 ;
  END
 END tw_data[991]
 PIN tw_data[992]
  DIRECTION INPUT ;
  USE SIGNAL ;
  PORT
   LAYER M5 ;
   RECT 283.152000 0.000000 283.176000 0.084000 ;
  END
 END tw_data[992]
 PIN tw_data[993]
  DIRECTION INPUT ;
  USE SIGNAL ;
  PORT
   LAYER M5 ;
   RECT 283.344000 0.000000 283.368000 0.084000 ;
  END
 END tw_data[993]
 PIN tw_data[994]
  DIRECTION INPUT ;
  USE SIGNAL ;
  PORT
   LAYER M5 ;
   RECT 283.536000 0.000000 283.560000 0.084000 ;
  END
 END tw_data[994]
 PIN tw_data[995]
  DIRECTION INPUT ;
  USE SIGNAL ;
  PORT
   LAYER M5 ;
   RECT 283.728000 0.000000 283.752000 0.084000 ;
  END
 END tw_data[995]
 PIN tw_data[996]
  DIRECTION INPUT ;
  USE SIGNAL ;
  PORT
   LAYER M5 ;
   RECT 283.920000 0.000000 283.944000 0.084000 ;
  END
 END tw_data[996]
 PIN tw_data[997]
  DIRECTION INPUT ;
  USE SIGNAL ;
  PORT
   LAYER M5 ;
   RECT 284.112000 0.000000 284.136000 0.084000 ;
  END
 END tw_data[997]
 PIN tw_data[998]
  DIRECTION INPUT ;
  USE SIGNAL ;
  PORT
   LAYER M5 ;
   RECT 284.304000 0.000000 284.328000 0.084000 ;
  END
 END tw_data[998]
 PIN tw_data[999]
  DIRECTION INPUT ;
  USE SIGNAL ;
  PORT
   LAYER M5 ;
   RECT 284.496000 0.000000 284.520000 0.084000 ;
  END
 END tw_data[999]
 PIN tw_data[1000]
  DIRECTION INPUT ;
  USE SIGNAL ;
  PORT
   LAYER M5 ;
   RECT 284.688000 0.000000 284.712000 0.084000 ;
  END
 END tw_data[1000]
 PIN tw_data[1001]
  DIRECTION INPUT ;
  USE SIGNAL ;
  PORT
   LAYER M5 ;
   RECT 284.880000 0.000000 284.904000 0.084000 ;
  END
 END tw_data[1001]
 PIN tw_data[1002]
  DIRECTION INPUT ;
  USE SIGNAL ;
  PORT
   LAYER M5 ;
   RECT 285.072000 0.000000 285.096000 0.084000 ;
  END
 END tw_data[1002]
 PIN tw_data[1003]
  DIRECTION INPUT ;
  USE SIGNAL ;
  PORT
   LAYER M5 ;
   RECT 285.264000 0.000000 285.288000 0.084000 ;
  END
 END tw_data[1003]
 PIN tw_data[1004]
  DIRECTION INPUT ;
  USE SIGNAL ;
  PORT
   LAYER M5 ;
   RECT 285.456000 0.000000 285.480000 0.084000 ;
  END
 END tw_data[1004]
 PIN tw_data[1005]
  DIRECTION INPUT ;
  USE SIGNAL ;
  PORT
   LAYER M5 ;
   RECT 285.648000 0.000000 285.672000 0.084000 ;
  END
 END tw_data[1005]
 PIN tw_data[1006]
  DIRECTION INPUT ;
  USE SIGNAL ;
  PORT
   LAYER M5 ;
   RECT 285.840000 0.000000 285.864000 0.084000 ;
  END
 END tw_data[1006]
 PIN tw_data[1007]
  DIRECTION INPUT ;
  USE SIGNAL ;
  PORT
   LAYER M5 ;
   RECT 286.032000 0.000000 286.056000 0.084000 ;
  END
 END tw_data[1007]
 PIN tw_data[1008]
  DIRECTION INPUT ;
  USE SIGNAL ;
  PORT
   LAYER M5 ;
   RECT 286.224000 0.000000 286.248000 0.084000 ;
  END
 END tw_data[1008]
 PIN tw_data[1009]
  DIRECTION INPUT ;
  USE SIGNAL ;
  PORT
   LAYER M5 ;
   RECT 286.416000 0.000000 286.440000 0.084000 ;
  END
 END tw_data[1009]
 PIN tw_data[1010]
  DIRECTION INPUT ;
  USE SIGNAL ;
  PORT
   LAYER M5 ;
   RECT 286.608000 0.000000 286.632000 0.084000 ;
  END
 END tw_data[1010]
 PIN tw_data[1011]
  DIRECTION INPUT ;
  USE SIGNAL ;
  PORT
   LAYER M5 ;
   RECT 286.800000 0.000000 286.824000 0.084000 ;
  END
 END tw_data[1011]
 PIN tw_data[1012]
  DIRECTION INPUT ;
  USE SIGNAL ;
  PORT
   LAYER M5 ;
   RECT 286.992000 0.000000 287.016000 0.084000 ;
  END
 END tw_data[1012]
 PIN tw_data[1013]
  DIRECTION INPUT ;
  USE SIGNAL ;
  PORT
   LAYER M5 ;
   RECT 287.472000 0.000000 287.496000 0.084000 ;
  END
 END tw_data[1013]
 PIN tw_data[1014]
  DIRECTION INPUT ;
  USE SIGNAL ;
  PORT
   LAYER M5 ;
   RECT 287.664000 0.000000 287.688000 0.084000 ;
  END
 END tw_data[1014]
 PIN tw_data[1015]
  DIRECTION INPUT ;
  USE SIGNAL ;
  PORT
   LAYER M5 ;
   RECT 287.856000 0.000000 287.880000 0.084000 ;
  END
 END tw_data[1015]
 PIN tw_data[1016]
  DIRECTION INPUT ;
  USE SIGNAL ;
  PORT
   LAYER M5 ;
   RECT 288.048000 0.000000 288.072000 0.084000 ;
  END
 END tw_data[1016]
 PIN tw_data[1017]
  DIRECTION INPUT ;
  USE SIGNAL ;
  PORT
   LAYER M5 ;
   RECT 288.240000 0.000000 288.264000 0.084000 ;
  END
 END tw_data[1017]
 PIN tw_data[1018]
  DIRECTION INPUT ;
  USE SIGNAL ;
  PORT
   LAYER M5 ;
   RECT 288.432000 0.000000 288.456000 0.084000 ;
  END
 END tw_data[1018]
 PIN tw_data[1019]
  DIRECTION INPUT ;
  USE SIGNAL ;
  PORT
   LAYER M5 ;
   RECT 288.624000 0.000000 288.648000 0.084000 ;
  END
 END tw_data[1019]
 PIN tw_data[1020]
  DIRECTION INPUT ;
  USE SIGNAL ;
  PORT
   LAYER M5 ;
   RECT 288.816000 0.000000 288.840000 0.084000 ;
  END
 END tw_data[1020]
 PIN tw_data[1021]
  DIRECTION INPUT ;
  USE SIGNAL ;
  PORT
   LAYER M5 ;
   RECT 289.008000 0.000000 289.032000 0.084000 ;
  END
 END tw_data[1021]
 PIN tw_data[1022]
  DIRECTION INPUT ;
  USE SIGNAL ;
  PORT
   LAYER M5 ;
   RECT 289.200000 0.000000 289.224000 0.084000 ;
  END
 END tw_data[1022]
 PIN tw_data[1023]
  DIRECTION INPUT ;
  USE SIGNAL ;
  PORT
   LAYER M5 ;
   RECT 289.392000 0.000000 289.416000 0.084000 ;
  END
 END tw_data[1023]
 PIN bs_addr[0]
  DIRECTION INPUT ;
  USE SIGNAL ;
  PORT
   LAYER M4 ;
   RECT 354.156000 96.000000 354.240000 96.024000 ;
  END
 END bs_addr[0]
 PIN bs_addr[1]
  DIRECTION INPUT ;
  USE SIGNAL ;
  PORT
   LAYER M4 ;
   RECT 354.156000 96.192000 354.240000 96.216000 ;
  END
 END bs_addr[1]
 PIN bs_addr[2]
  DIRECTION INPUT ;
  USE SIGNAL ;
  PORT
   LAYER M4 ;
   RECT 354.156000 96.384000 354.240000 96.408000 ;
  END
 END bs_addr[2]
 PIN bs_addr[3]
  DIRECTION INPUT ;
  USE SIGNAL ;
  PORT
   LAYER M4 ;
   RECT 354.156000 96.576000 354.240000 96.600000 ;
  END
 END bs_addr[3]
 PIN bs_addr[4]
  DIRECTION INPUT ;
  USE SIGNAL ;
  PORT
   LAYER M4 ;
   RECT 354.156000 96.768000 354.240000 96.792000 ;
  END
 END bs_addr[4]
 PIN bs_addr[5]
  DIRECTION INPUT ;
  USE SIGNAL ;
  PORT
   LAYER M4 ;
   RECT 354.156000 96.960000 354.240000 96.984000 ;
  END
 END bs_addr[5]
 PIN bs_addr[6]
  DIRECTION INPUT ;
  USE SIGNAL ;
  PORT
   LAYER M4 ;
   RECT 354.156000 97.152000 354.240000 97.176000 ;
  END
 END bs_addr[6]
 PIN bs_addr[7]
  DIRECTION INPUT ;
  USE SIGNAL ;
  PORT
   LAYER M4 ;
   RECT 354.156000 97.344000 354.240000 97.368000 ;
  END
 END bs_addr[7]
 PIN bs_addr[8]
  DIRECTION INPUT ;
  USE SIGNAL ;
  PORT
   LAYER M4 ;
   RECT 354.156000 97.536000 354.240000 97.560000 ;
  END
 END bs_addr[8]
 PIN bs_addr[9]
  DIRECTION INPUT ;
  USE SIGNAL ;
  PORT
   LAYER M4 ;
   RECT 354.156000 97.728000 354.240000 97.752000 ;
  END
 END bs_addr[9]
 PIN bs_addr[10]
  DIRECTION INPUT ;
  USE SIGNAL ;
  PORT
   LAYER M4 ;
   RECT 354.156000 97.920000 354.240000 97.944000 ;
  END
 END bs_addr[10]
 PIN bs_addr[11]
  DIRECTION INPUT ;
  USE SIGNAL ;
  PORT
   LAYER M4 ;
   RECT 354.156000 98.112000 354.240000 98.136000 ;
  END
 END bs_addr[11]
 PIN bs_addr[12]
  DIRECTION INPUT ;
  USE SIGNAL ;
  PORT
   LAYER M4 ;
   RECT 354.156000 98.304000 354.240000 98.328000 ;
  END
 END bs_addr[12]
 PIN bs_addr[13]
  DIRECTION INPUT ;
  USE SIGNAL ;
  PORT
   LAYER M4 ;
   RECT 354.156000 98.496000 354.240000 98.520000 ;
  END
 END bs_addr[13]
 PIN bs_addr[14]
  DIRECTION INPUT ;
  USE SIGNAL ;
  PORT
   LAYER M4 ;
   RECT 354.156000 98.688000 354.240000 98.712000 ;
  END
 END bs_addr[14]
 PIN bs_addr[15]
  DIRECTION INPUT ;
  USE SIGNAL ;
  PORT
   LAYER M4 ;
   RECT 354.156000 98.880000 354.240000 98.904000 ;
  END
 END bs_addr[15]
 PIN bs_addr[16]
  DIRECTION INPUT ;
  USE SIGNAL ;
  PORT
   LAYER M4 ;
   RECT 354.156000 99.072000 354.240000 99.096000 ;
  END
 END bs_addr[16]
 PIN bs_addr[17]
  DIRECTION INPUT ;
  USE SIGNAL ;
  PORT
   LAYER M4 ;
   RECT 354.156000 99.264000 354.240000 99.288000 ;
  END
 END bs_addr[17]
 PIN bs_addr[18]
  DIRECTION INPUT ;
  USE SIGNAL ;
  PORT
   LAYER M4 ;
   RECT 354.156000 99.456000 354.240000 99.480000 ;
  END
 END bs_addr[18]
 PIN bs_addr[19]
  DIRECTION INPUT ;
  USE SIGNAL ;
  PORT
   LAYER M4 ;
   RECT 354.156000 99.648000 354.240000 99.672000 ;
  END
 END bs_addr[19]
 PIN bs_addr[20]
  DIRECTION INPUT ;
  USE SIGNAL ;
  PORT
   LAYER M4 ;
   RECT 354.156000 99.840000 354.240000 99.864000 ;
  END
 END bs_addr[20]
 PIN bs_addr[21]
  DIRECTION INPUT ;
  USE SIGNAL ;
  PORT
   LAYER M4 ;
   RECT 354.156000 100.032000 354.240000 100.056000 ;
  END
 END bs_addr[21]
 PIN bs_addr[22]
  DIRECTION INPUT ;
  USE SIGNAL ;
  PORT
   LAYER M4 ;
   RECT 354.156000 100.224000 354.240000 100.248000 ;
  END
 END bs_addr[22]
 PIN bs_addr[23]
  DIRECTION INPUT ;
  USE SIGNAL ;
  PORT
   LAYER M4 ;
   RECT 354.156000 100.416000 354.240000 100.440000 ;
  END
 END bs_addr[23]
 PIN bs_re
  DIRECTION INPUT ;
  USE SIGNAL ;
  PORT
   LAYER M4 ;
   RECT 354.156000 101.184000 354.240000 101.208000 ;
  END
 END bs_re
 PIN bs_q[0]
  DIRECTION OUTPUT ;
  USE SIGNAL ;
  PORT
   LAYER M4 ;
   RECT 354.156000 104.640000 354.240000 104.664000 ;
  END
 END bs_q[0]
 PIN bs_q[1]
  DIRECTION OUTPUT ;
  USE SIGNAL ;
  PORT
   LAYER M4 ;
   RECT 354.156000 104.832000 354.240000 104.856000 ;
  END
 END bs_q[1]
 PIN bs_q[2]
  DIRECTION OUTPUT ;
  USE SIGNAL ;
  PORT
   LAYER M4 ;
   RECT 354.156000 105.024000 354.240000 105.048000 ;
  END
 END bs_q[2]
 PIN bs_q[3]
  DIRECTION OUTPUT ;
  USE SIGNAL ;
  PORT
   LAYER M4 ;
   RECT 354.156000 105.216000 354.240000 105.240000 ;
  END
 END bs_q[3]
 PIN bs_q[4]
  DIRECTION OUTPUT ;
  USE SIGNAL ;
  PORT
   LAYER M4 ;
   RECT 354.156000 105.408000 354.240000 105.432000 ;
  END
 END bs_q[4]
 PIN bs_q[5]
  DIRECTION OUTPUT ;
  USE SIGNAL ;
  PORT
   LAYER M4 ;
   RECT 354.156000 105.600000 354.240000 105.624000 ;
  END
 END bs_q[5]
 PIN bs_q[6]
  DIRECTION OUTPUT ;
  USE SIGNAL ;
  PORT
   LAYER M4 ;
   RECT 354.156000 105.792000 354.240000 105.816000 ;
  END
 END bs_q[6]
 PIN bs_q[7]
  DIRECTION OUTPUT ;
  USE SIGNAL ;
  PORT
   LAYER M4 ;
   RECT 354.156000 105.984000 354.240000 106.008000 ;
  END
 END bs_q[7]
 PIN bs_q[8]
  DIRECTION OUTPUT ;
  USE SIGNAL ;
  PORT
   LAYER M4 ;
   RECT 354.156000 106.176000 354.240000 106.200000 ;
  END
 END bs_q[8]
 PIN bs_q[9]
  DIRECTION OUTPUT ;
  USE SIGNAL ;
  PORT
   LAYER M4 ;
   RECT 354.156000 106.368000 354.240000 106.392000 ;
  END
 END bs_q[9]
 PIN bs_q[10]
  DIRECTION OUTPUT ;
  USE SIGNAL ;
  PORT
   LAYER M4 ;
   RECT 354.156000 106.560000 354.240000 106.584000 ;
  END
 END bs_q[10]
 PIN bs_q[11]
  DIRECTION OUTPUT ;
  USE SIGNAL ;
  PORT
   LAYER M4 ;
   RECT 354.156000 106.752000 354.240000 106.776000 ;
  END
 END bs_q[11]
 PIN bs_q[12]
  DIRECTION OUTPUT ;
  USE SIGNAL ;
  PORT
   LAYER M4 ;
   RECT 354.156000 106.944000 354.240000 106.968000 ;
  END
 END bs_q[12]
 PIN bs_q[13]
  DIRECTION OUTPUT ;
  USE SIGNAL ;
  PORT
   LAYER M4 ;
   RECT 354.156000 107.136000 354.240000 107.160000 ;
  END
 END bs_q[13]
 PIN bs_q[14]
  DIRECTION OUTPUT ;
  USE SIGNAL ;
  PORT
   LAYER M4 ;
   RECT 354.156000 107.328000 354.240000 107.352000 ;
  END
 END bs_q[14]
 PIN bs_q[15]
  DIRECTION OUTPUT ;
  USE SIGNAL ;
  PORT
   LAYER M4 ;
   RECT 354.156000 107.520000 354.240000 107.544000 ;
  END
 END bs_q[15]
 PIN bs_q[16]
  DIRECTION OUTPUT ;
  USE SIGNAL ;
  PORT
   LAYER M4 ;
   RECT 354.156000 107.712000 354.240000 107.736000 ;
  END
 END bs_q[16]
 PIN bs_q[17]
  DIRECTION OUTPUT ;
  USE SIGNAL ;
  PORT
   LAYER M4 ;
   RECT 354.156000 107.904000 354.240000 107.928000 ;
  END
 END bs_q[17]
 PIN bs_q[18]
  DIRECTION OUTPUT ;
  USE SIGNAL ;
  PORT
   LAYER M4 ;
   RECT 354.156000 108.096000 354.240000 108.120000 ;
  END
 END bs_q[18]
 PIN bs_q[19]
  DIRECTION OUTPUT ;
  USE SIGNAL ;
  PORT
   LAYER M4 ;
   RECT 354.156000 108.288000 354.240000 108.312000 ;
  END
 END bs_q[19]
 PIN bs_q[20]
  DIRECTION OUTPUT ;
  USE SIGNAL ;
  PORT
   LAYER M4 ;
   RECT 354.156000 108.480000 354.240000 108.504000 ;
  END
 END bs_q[20]
 PIN bs_q[21]
  DIRECTION OUTPUT ;
  USE SIGNAL ;
  PORT
   LAYER M4 ;
   RECT 354.156000 108.672000 354.240000 108.696000 ;
  END
 END bs_q[21]
 PIN bs_q[22]
  DIRECTION OUTPUT ;
  USE SIGNAL ;
  PORT
   LAYER M4 ;
   RECT 354.156000 108.864000 354.240000 108.888000 ;
  END
 END bs_q[22]
 PIN bs_q[23]
  DIRECTION OUTPUT ;
  USE SIGNAL ;
  PORT
   LAYER M4 ;
   RECT 354.156000 109.056000 354.240000 109.080000 ;
  END
 END bs_q[23]
 PIN bs_q[24]
  DIRECTION OUTPUT ;
  USE SIGNAL ;
  PORT
   LAYER M4 ;
   RECT 354.156000 109.248000 354.240000 109.272000 ;
  END
 END bs_q[24]
 PIN bs_q[25]
  DIRECTION OUTPUT ;
  USE SIGNAL ;
  PORT
   LAYER M4 ;
   RECT 354.156000 109.440000 354.240000 109.464000 ;
  END
 END bs_q[25]
 PIN bs_q[26]
  DIRECTION OUTPUT ;
  USE SIGNAL ;
  PORT
   LAYER M4 ;
   RECT 354.156000 109.632000 354.240000 109.656000 ;
  END
 END bs_q[26]
 PIN bs_q[27]
  DIRECTION OUTPUT ;
  USE SIGNAL ;
  PORT
   LAYER M4 ;
   RECT 354.156000 109.824000 354.240000 109.848000 ;
  END
 END bs_q[27]
 PIN bs_q[28]
  DIRECTION OUTPUT ;
  USE SIGNAL ;
  PORT
   LAYER M4 ;
   RECT 354.156000 110.016000 354.240000 110.040000 ;
  END
 END bs_q[28]
 PIN bs_q[29]
  DIRECTION OUTPUT ;
  USE SIGNAL ;
  PORT
   LAYER M4 ;
   RECT 354.156000 110.208000 354.240000 110.232000 ;
  END
 END bs_q[29]
 PIN bs_q[30]
  DIRECTION OUTPUT ;
  USE SIGNAL ;
  PORT
   LAYER M4 ;
   RECT 354.156000 110.400000 354.240000 110.424000 ;
  END
 END bs_q[30]
 PIN bs_q[31]
  DIRECTION OUTPUT ;
  USE SIGNAL ;
  PORT
   LAYER M4 ;
   RECT 354.156000 110.592000 354.240000 110.616000 ;
  END
 END bs_q[31]
 PIN bs_q[32]
  DIRECTION OUTPUT ;
  USE SIGNAL ;
  PORT
   LAYER M4 ;
   RECT 354.156000 110.784000 354.240000 110.808000 ;
  END
 END bs_q[32]
 PIN bs_q[33]
  DIRECTION OUTPUT ;
  USE SIGNAL ;
  PORT
   LAYER M4 ;
   RECT 354.156000 110.976000 354.240000 111.000000 ;
  END
 END bs_q[33]
 PIN bs_q[34]
  DIRECTION OUTPUT ;
  USE SIGNAL ;
  PORT
   LAYER M4 ;
   RECT 354.156000 111.168000 354.240000 111.192000 ;
  END
 END bs_q[34]
 PIN bs_q[35]
  DIRECTION OUTPUT ;
  USE SIGNAL ;
  PORT
   LAYER M4 ;
   RECT 354.156000 111.360000 354.240000 111.384000 ;
  END
 END bs_q[35]
 PIN bs_q[36]
  DIRECTION OUTPUT ;
  USE SIGNAL ;
  PORT
   LAYER M4 ;
   RECT 354.156000 111.552000 354.240000 111.576000 ;
  END
 END bs_q[36]
 PIN bs_q[37]
  DIRECTION OUTPUT ;
  USE SIGNAL ;
  PORT
   LAYER M4 ;
   RECT 354.156000 111.744000 354.240000 111.768000 ;
  END
 END bs_q[37]
 PIN bs_q[38]
  DIRECTION OUTPUT ;
  USE SIGNAL ;
  PORT
   LAYER M4 ;
   RECT 354.156000 111.936000 354.240000 111.960000 ;
  END
 END bs_q[38]
 PIN bs_q[39]
  DIRECTION OUTPUT ;
  USE SIGNAL ;
  PORT
   LAYER M4 ;
   RECT 354.156000 112.128000 354.240000 112.152000 ;
  END
 END bs_q[39]
 PIN bs_q[40]
  DIRECTION OUTPUT ;
  USE SIGNAL ;
  PORT
   LAYER M4 ;
   RECT 354.156000 112.320000 354.240000 112.344000 ;
  END
 END bs_q[40]
 PIN bs_q[41]
  DIRECTION OUTPUT ;
  USE SIGNAL ;
  PORT
   LAYER M4 ;
   RECT 354.156000 112.512000 354.240000 112.536000 ;
  END
 END bs_q[41]
 PIN bs_q[42]
  DIRECTION OUTPUT ;
  USE SIGNAL ;
  PORT
   LAYER M4 ;
   RECT 354.156000 112.704000 354.240000 112.728000 ;
  END
 END bs_q[42]
 PIN bs_q[43]
  DIRECTION OUTPUT ;
  USE SIGNAL ;
  PORT
   LAYER M4 ;
   RECT 354.156000 112.896000 354.240000 112.920000 ;
  END
 END bs_q[43]
 PIN bs_q[44]
  DIRECTION OUTPUT ;
  USE SIGNAL ;
  PORT
   LAYER M4 ;
   RECT 354.156000 113.088000 354.240000 113.112000 ;
  END
 END bs_q[44]
 PIN bs_q[45]
  DIRECTION OUTPUT ;
  USE SIGNAL ;
  PORT
   LAYER M4 ;
   RECT 354.156000 113.280000 354.240000 113.304000 ;
  END
 END bs_q[45]
 PIN bs_q[46]
  DIRECTION OUTPUT ;
  USE SIGNAL ;
  PORT
   LAYER M4 ;
   RECT 354.156000 113.472000 354.240000 113.496000 ;
  END
 END bs_q[46]
 PIN bs_q[47]
  DIRECTION OUTPUT ;
  USE SIGNAL ;
  PORT
   LAYER M4 ;
   RECT 354.156000 113.664000 354.240000 113.688000 ;
  END
 END bs_q[47]
 PIN bs_q[48]
  DIRECTION OUTPUT ;
  USE SIGNAL ;
  PORT
   LAYER M4 ;
   RECT 354.156000 113.856000 354.240000 113.880000 ;
  END
 END bs_q[48]
 PIN bs_q[49]
  DIRECTION OUTPUT ;
  USE SIGNAL ;
  PORT
   LAYER M4 ;
   RECT 354.156000 114.048000 354.240000 114.072000 ;
  END
 END bs_q[49]
 PIN bs_q[50]
  DIRECTION OUTPUT ;
  USE SIGNAL ;
  PORT
   LAYER M4 ;
   RECT 354.156000 114.240000 354.240000 114.264000 ;
  END
 END bs_q[50]
 PIN bs_q[51]
  DIRECTION OUTPUT ;
  USE SIGNAL ;
  PORT
   LAYER M4 ;
   RECT 354.156000 114.432000 354.240000 114.456000 ;
  END
 END bs_q[51]
 PIN bs_q[52]
  DIRECTION OUTPUT ;
  USE SIGNAL ;
  PORT
   LAYER M4 ;
   RECT 354.156000 114.624000 354.240000 114.648000 ;
  END
 END bs_q[52]
 PIN bs_q[53]
  DIRECTION OUTPUT ;
  USE SIGNAL ;
  PORT
   LAYER M4 ;
   RECT 354.156000 114.816000 354.240000 114.840000 ;
  END
 END bs_q[53]
 PIN bs_q[54]
  DIRECTION OUTPUT ;
  USE SIGNAL ;
  PORT
   LAYER M4 ;
   RECT 354.156000 115.008000 354.240000 115.032000 ;
  END
 END bs_q[54]
 PIN bs_q[55]
  DIRECTION OUTPUT ;
  USE SIGNAL ;
  PORT
   LAYER M4 ;
   RECT 354.156000 115.200000 354.240000 115.224000 ;
  END
 END bs_q[55]
 PIN bs_q[56]
  DIRECTION OUTPUT ;
  USE SIGNAL ;
  PORT
   LAYER M4 ;
   RECT 354.156000 115.392000 354.240000 115.416000 ;
  END
 END bs_q[56]
 PIN bs_q[57]
  DIRECTION OUTPUT ;
  USE SIGNAL ;
  PORT
   LAYER M4 ;
   RECT 354.156000 115.584000 354.240000 115.608000 ;
  END
 END bs_q[57]
 PIN bs_q[58]
  DIRECTION OUTPUT ;
  USE SIGNAL ;
  PORT
   LAYER M4 ;
   RECT 354.156000 115.776000 354.240000 115.800000 ;
  END
 END bs_q[58]
 PIN bs_q[59]
  DIRECTION OUTPUT ;
  USE SIGNAL ;
  PORT
   LAYER M4 ;
   RECT 354.156000 115.968000 354.240000 115.992000 ;
  END
 END bs_q[59]
 PIN bs_q[60]
  DIRECTION OUTPUT ;
  USE SIGNAL ;
  PORT
   LAYER M4 ;
   RECT 354.156000 116.160000 354.240000 116.184000 ;
  END
 END bs_q[60]
 PIN bs_q[61]
  DIRECTION OUTPUT ;
  USE SIGNAL ;
  PORT
   LAYER M4 ;
   RECT 354.156000 116.352000 354.240000 116.376000 ;
  END
 END bs_q[61]
 PIN bs_q[62]
  DIRECTION OUTPUT ;
  USE SIGNAL ;
  PORT
   LAYER M4 ;
   RECT 354.156000 116.544000 354.240000 116.568000 ;
  END
 END bs_q[62]
 PIN bs_q[63]
  DIRECTION OUTPUT ;
  USE SIGNAL ;
  PORT
   LAYER M4 ;
   RECT 354.156000 116.736000 354.240000 116.760000 ;
  END
 END bs_q[63]
 PIN bs_q[64]
  DIRECTION OUTPUT ;
  USE SIGNAL ;
  PORT
   LAYER M4 ;
   RECT 354.156000 116.928000 354.240000 116.952000 ;
  END
 END bs_q[64]
 PIN bs_q[65]
  DIRECTION OUTPUT ;
  USE SIGNAL ;
  PORT
   LAYER M4 ;
   RECT 354.156000 117.120000 354.240000 117.144000 ;
  END
 END bs_q[65]
 PIN bs_q[66]
  DIRECTION OUTPUT ;
  USE SIGNAL ;
  PORT
   LAYER M4 ;
   RECT 354.156000 117.312000 354.240000 117.336000 ;
  END
 END bs_q[66]
 PIN bs_q[67]
  DIRECTION OUTPUT ;
  USE SIGNAL ;
  PORT
   LAYER M4 ;
   RECT 354.156000 117.504000 354.240000 117.528000 ;
  END
 END bs_q[67]
 PIN bs_q[68]
  DIRECTION OUTPUT ;
  USE SIGNAL ;
  PORT
   LAYER M4 ;
   RECT 354.156000 117.696000 354.240000 117.720000 ;
  END
 END bs_q[68]
 PIN bs_q[69]
  DIRECTION OUTPUT ;
  USE SIGNAL ;
  PORT
   LAYER M4 ;
   RECT 354.156000 117.888000 354.240000 117.912000 ;
  END
 END bs_q[69]
 PIN bs_q[70]
  DIRECTION OUTPUT ;
  USE SIGNAL ;
  PORT
   LAYER M4 ;
   RECT 354.156000 118.080000 354.240000 118.104000 ;
  END
 END bs_q[70]
 PIN bs_q[71]
  DIRECTION OUTPUT ;
  USE SIGNAL ;
  PORT
   LAYER M4 ;
   RECT 354.156000 118.272000 354.240000 118.296000 ;
  END
 END bs_q[71]
 PIN bs_q[72]
  DIRECTION OUTPUT ;
  USE SIGNAL ;
  PORT
   LAYER M4 ;
   RECT 354.156000 118.464000 354.240000 118.488000 ;
  END
 END bs_q[72]
 PIN bs_q[73]
  DIRECTION OUTPUT ;
  USE SIGNAL ;
  PORT
   LAYER M4 ;
   RECT 354.156000 118.656000 354.240000 118.680000 ;
  END
 END bs_q[73]
 PIN bs_q[74]
  DIRECTION OUTPUT ;
  USE SIGNAL ;
  PORT
   LAYER M4 ;
   RECT 354.156000 118.848000 354.240000 118.872000 ;
  END
 END bs_q[74]
 PIN bs_q[75]
  DIRECTION OUTPUT ;
  USE SIGNAL ;
  PORT
   LAYER M4 ;
   RECT 354.156000 119.040000 354.240000 119.064000 ;
  END
 END bs_q[75]
 PIN bs_q[76]
  DIRECTION OUTPUT ;
  USE SIGNAL ;
  PORT
   LAYER M4 ;
   RECT 354.156000 119.232000 354.240000 119.256000 ;
  END
 END bs_q[76]
 PIN bs_q[77]
  DIRECTION OUTPUT ;
  USE SIGNAL ;
  PORT
   LAYER M4 ;
   RECT 354.156000 119.424000 354.240000 119.448000 ;
  END
 END bs_q[77]
 PIN bs_q[78]
  DIRECTION OUTPUT ;
  USE SIGNAL ;
  PORT
   LAYER M4 ;
   RECT 354.156000 119.616000 354.240000 119.640000 ;
  END
 END bs_q[78]
 PIN bs_q[79]
  DIRECTION OUTPUT ;
  USE SIGNAL ;
  PORT
   LAYER M4 ;
   RECT 354.156000 119.808000 354.240000 119.832000 ;
  END
 END bs_q[79]
 PIN bs_q[80]
  DIRECTION OUTPUT ;
  USE SIGNAL ;
  PORT
   LAYER M4 ;
   RECT 354.156000 120.000000 354.240000 120.024000 ;
  END
 END bs_q[80]
 PIN bs_q[81]
  DIRECTION OUTPUT ;
  USE SIGNAL ;
  PORT
   LAYER M4 ;
   RECT 354.156000 120.192000 354.240000 120.216000 ;
  END
 END bs_q[81]
 PIN bs_q[82]
  DIRECTION OUTPUT ;
  USE SIGNAL ;
  PORT
   LAYER M4 ;
   RECT 354.156000 120.384000 354.240000 120.408000 ;
  END
 END bs_q[82]
 PIN bs_q[83]
  DIRECTION OUTPUT ;
  USE SIGNAL ;
  PORT
   LAYER M4 ;
   RECT 354.156000 120.576000 354.240000 120.600000 ;
  END
 END bs_q[83]
 PIN bs_q[84]
  DIRECTION OUTPUT ;
  USE SIGNAL ;
  PORT
   LAYER M4 ;
   RECT 354.156000 120.768000 354.240000 120.792000 ;
  END
 END bs_q[84]
 PIN bs_q[85]
  DIRECTION OUTPUT ;
  USE SIGNAL ;
  PORT
   LAYER M4 ;
   RECT 354.156000 120.960000 354.240000 120.984000 ;
  END
 END bs_q[85]
 PIN bs_q[86]
  DIRECTION OUTPUT ;
  USE SIGNAL ;
  PORT
   LAYER M4 ;
   RECT 354.156000 121.152000 354.240000 121.176000 ;
  END
 END bs_q[86]
 PIN bs_q[87]
  DIRECTION OUTPUT ;
  USE SIGNAL ;
  PORT
   LAYER M4 ;
   RECT 354.156000 121.344000 354.240000 121.368000 ;
  END
 END bs_q[87]
 PIN bs_q[88]
  DIRECTION OUTPUT ;
  USE SIGNAL ;
  PORT
   LAYER M4 ;
   RECT 354.156000 121.536000 354.240000 121.560000 ;
  END
 END bs_q[88]
 PIN bs_q[89]
  DIRECTION OUTPUT ;
  USE SIGNAL ;
  PORT
   LAYER M4 ;
   RECT 354.156000 121.728000 354.240000 121.752000 ;
  END
 END bs_q[89]
 PIN bs_q[90]
  DIRECTION OUTPUT ;
  USE SIGNAL ;
  PORT
   LAYER M4 ;
   RECT 354.156000 121.920000 354.240000 121.944000 ;
  END
 END bs_q[90]
 PIN bs_q[91]
  DIRECTION OUTPUT ;
  USE SIGNAL ;
  PORT
   LAYER M4 ;
   RECT 354.156000 122.112000 354.240000 122.136000 ;
  END
 END bs_q[91]
 PIN bs_q[92]
  DIRECTION OUTPUT ;
  USE SIGNAL ;
  PORT
   LAYER M4 ;
   RECT 354.156000 122.304000 354.240000 122.328000 ;
  END
 END bs_q[92]
 PIN bs_q[93]
  DIRECTION OUTPUT ;
  USE SIGNAL ;
  PORT
   LAYER M4 ;
   RECT 354.156000 122.496000 354.240000 122.520000 ;
  END
 END bs_q[93]
 PIN bs_q[94]
  DIRECTION OUTPUT ;
  USE SIGNAL ;
  PORT
   LAYER M4 ;
   RECT 354.156000 122.688000 354.240000 122.712000 ;
  END
 END bs_q[94]
 PIN bs_q[95]
  DIRECTION OUTPUT ;
  USE SIGNAL ;
  PORT
   LAYER M4 ;
   RECT 354.156000 122.880000 354.240000 122.904000 ;
  END
 END bs_q[95]
 PIN bs_q[96]
  DIRECTION OUTPUT ;
  USE SIGNAL ;
  PORT
   LAYER M4 ;
   RECT 354.156000 123.072000 354.240000 123.096000 ;
  END
 END bs_q[96]
 PIN bs_q[97]
  DIRECTION OUTPUT ;
  USE SIGNAL ;
  PORT
   LAYER M4 ;
   RECT 354.156000 123.264000 354.240000 123.288000 ;
  END
 END bs_q[97]
 PIN bs_q[98]
  DIRECTION OUTPUT ;
  USE SIGNAL ;
  PORT
   LAYER M4 ;
   RECT 354.156000 123.456000 354.240000 123.480000 ;
  END
 END bs_q[98]
 PIN bs_q[99]
  DIRECTION OUTPUT ;
  USE SIGNAL ;
  PORT
   LAYER M4 ;
   RECT 354.156000 123.648000 354.240000 123.672000 ;
  END
 END bs_q[99]
 PIN bs_q[100]
  DIRECTION OUTPUT ;
  USE SIGNAL ;
  PORT
   LAYER M4 ;
   RECT 354.156000 123.840000 354.240000 123.864000 ;
  END
 END bs_q[100]
 PIN bs_q[101]
  DIRECTION OUTPUT ;
  USE SIGNAL ;
  PORT
   LAYER M4 ;
   RECT 354.156000 124.032000 354.240000 124.056000 ;
  END
 END bs_q[101]
 PIN bs_q[102]
  DIRECTION OUTPUT ;
  USE SIGNAL ;
  PORT
   LAYER M4 ;
   RECT 354.156000 124.224000 354.240000 124.248000 ;
  END
 END bs_q[102]
 PIN bs_q[103]
  DIRECTION OUTPUT ;
  USE SIGNAL ;
  PORT
   LAYER M4 ;
   RECT 354.156000 124.416000 354.240000 124.440000 ;
  END
 END bs_q[103]
 PIN bs_q[104]
  DIRECTION OUTPUT ;
  USE SIGNAL ;
  PORT
   LAYER M4 ;
   RECT 354.156000 124.608000 354.240000 124.632000 ;
  END
 END bs_q[104]
 PIN bs_q[105]
  DIRECTION OUTPUT ;
  USE SIGNAL ;
  PORT
   LAYER M4 ;
   RECT 354.156000 124.800000 354.240000 124.824000 ;
  END
 END bs_q[105]
 PIN bs_q[106]
  DIRECTION OUTPUT ;
  USE SIGNAL ;
  PORT
   LAYER M4 ;
   RECT 354.156000 124.992000 354.240000 125.016000 ;
  END
 END bs_q[106]
 PIN bs_q[107]
  DIRECTION OUTPUT ;
  USE SIGNAL ;
  PORT
   LAYER M4 ;
   RECT 354.156000 125.184000 354.240000 125.208000 ;
  END
 END bs_q[107]
 PIN bs_q[108]
  DIRECTION OUTPUT ;
  USE SIGNAL ;
  PORT
   LAYER M4 ;
   RECT 354.156000 125.376000 354.240000 125.400000 ;
  END
 END bs_q[108]
 PIN bs_q[109]
  DIRECTION OUTPUT ;
  USE SIGNAL ;
  PORT
   LAYER M4 ;
   RECT 354.156000 125.568000 354.240000 125.592000 ;
  END
 END bs_q[109]
 PIN bs_q[110]
  DIRECTION OUTPUT ;
  USE SIGNAL ;
  PORT
   LAYER M4 ;
   RECT 354.156000 125.760000 354.240000 125.784000 ;
  END
 END bs_q[110]
 PIN bs_q[111]
  DIRECTION OUTPUT ;
  USE SIGNAL ;
  PORT
   LAYER M4 ;
   RECT 354.156000 125.952000 354.240000 125.976000 ;
  END
 END bs_q[111]
 PIN bs_q[112]
  DIRECTION OUTPUT ;
  USE SIGNAL ;
  PORT
   LAYER M4 ;
   RECT 354.156000 126.144000 354.240000 126.168000 ;
  END
 END bs_q[112]
 PIN bs_q[113]
  DIRECTION OUTPUT ;
  USE SIGNAL ;
  PORT
   LAYER M4 ;
   RECT 354.156000 126.336000 354.240000 126.360000 ;
  END
 END bs_q[113]
 PIN bs_q[114]
  DIRECTION OUTPUT ;
  USE SIGNAL ;
  PORT
   LAYER M4 ;
   RECT 354.156000 126.528000 354.240000 126.552000 ;
  END
 END bs_q[114]
 PIN bs_q[115]
  DIRECTION OUTPUT ;
  USE SIGNAL ;
  PORT
   LAYER M4 ;
   RECT 354.156000 126.720000 354.240000 126.744000 ;
  END
 END bs_q[115]
 PIN bs_q[116]
  DIRECTION OUTPUT ;
  USE SIGNAL ;
  PORT
   LAYER M4 ;
   RECT 354.156000 126.912000 354.240000 126.936000 ;
  END
 END bs_q[116]
 PIN bs_q[117]
  DIRECTION OUTPUT ;
  USE SIGNAL ;
  PORT
   LAYER M4 ;
   RECT 354.156000 127.104000 354.240000 127.128000 ;
  END
 END bs_q[117]
 PIN bs_q[118]
  DIRECTION OUTPUT ;
  USE SIGNAL ;
  PORT
   LAYER M4 ;
   RECT 354.156000 127.296000 354.240000 127.320000 ;
  END
 END bs_q[118]
 PIN bs_q[119]
  DIRECTION OUTPUT ;
  USE SIGNAL ;
  PORT
   LAYER M4 ;
   RECT 354.156000 127.488000 354.240000 127.512000 ;
  END
 END bs_q[119]
 PIN bs_q[120]
  DIRECTION OUTPUT ;
  USE SIGNAL ;
  PORT
   LAYER M4 ;
   RECT 354.156000 127.680000 354.240000 127.704000 ;
  END
 END bs_q[120]
 PIN bs_q[121]
  DIRECTION OUTPUT ;
  USE SIGNAL ;
  PORT
   LAYER M4 ;
   RECT 354.156000 127.872000 354.240000 127.896000 ;
  END
 END bs_q[121]
 PIN bs_q[122]
  DIRECTION OUTPUT ;
  USE SIGNAL ;
  PORT
   LAYER M4 ;
   RECT 354.156000 128.064000 354.240000 128.088000 ;
  END
 END bs_q[122]
 PIN bs_q[123]
  DIRECTION OUTPUT ;
  USE SIGNAL ;
  PORT
   LAYER M4 ;
   RECT 354.156000 128.256000 354.240000 128.280000 ;
  END
 END bs_q[123]
 PIN bs_q[124]
  DIRECTION OUTPUT ;
  USE SIGNAL ;
  PORT
   LAYER M4 ;
   RECT 354.156000 128.448000 354.240000 128.472000 ;
  END
 END bs_q[124]
 PIN bs_q[125]
  DIRECTION OUTPUT ;
  USE SIGNAL ;
  PORT
   LAYER M4 ;
   RECT 354.156000 128.640000 354.240000 128.664000 ;
  END
 END bs_q[125]
 PIN bs_q[126]
  DIRECTION OUTPUT ;
  USE SIGNAL ;
  PORT
   LAYER M4 ;
   RECT 354.156000 128.832000 354.240000 128.856000 ;
  END
 END bs_q[126]
 PIN bs_q[127]
  DIRECTION OUTPUT ;
  USE SIGNAL ;
  PORT
   LAYER M4 ;
   RECT 354.156000 129.024000 354.240000 129.048000 ;
  END
 END bs_q[127]
 PIN bs_q[128]
  DIRECTION OUTPUT ;
  USE SIGNAL ;
  PORT
   LAYER M4 ;
   RECT 354.156000 129.216000 354.240000 129.240000 ;
  END
 END bs_q[128]
 PIN bs_q[129]
  DIRECTION OUTPUT ;
  USE SIGNAL ;
  PORT
   LAYER M4 ;
   RECT 354.156000 129.408000 354.240000 129.432000 ;
  END
 END bs_q[129]
 PIN bs_q[130]
  DIRECTION OUTPUT ;
  USE SIGNAL ;
  PORT
   LAYER M4 ;
   RECT 354.156000 129.600000 354.240000 129.624000 ;
  END
 END bs_q[130]
 PIN bs_q[131]
  DIRECTION OUTPUT ;
  USE SIGNAL ;
  PORT
   LAYER M4 ;
   RECT 354.156000 129.792000 354.240000 129.816000 ;
  END
 END bs_q[131]
 PIN bs_q[132]
  DIRECTION OUTPUT ;
  USE SIGNAL ;
  PORT
   LAYER M4 ;
   RECT 354.156000 129.984000 354.240000 130.008000 ;
  END
 END bs_q[132]
 PIN bs_q[133]
  DIRECTION OUTPUT ;
  USE SIGNAL ;
  PORT
   LAYER M4 ;
   RECT 354.156000 130.176000 354.240000 130.200000 ;
  END
 END bs_q[133]
 PIN bs_q[134]
  DIRECTION OUTPUT ;
  USE SIGNAL ;
  PORT
   LAYER M4 ;
   RECT 354.156000 130.368000 354.240000 130.392000 ;
  END
 END bs_q[134]
 PIN bs_q[135]
  DIRECTION OUTPUT ;
  USE SIGNAL ;
  PORT
   LAYER M4 ;
   RECT 354.156000 130.560000 354.240000 130.584000 ;
  END
 END bs_q[135]
 PIN bs_q[136]
  DIRECTION OUTPUT ;
  USE SIGNAL ;
  PORT
   LAYER M4 ;
   RECT 354.156000 130.752000 354.240000 130.776000 ;
  END
 END bs_q[136]
 PIN bs_q[137]
  DIRECTION OUTPUT ;
  USE SIGNAL ;
  PORT
   LAYER M4 ;
   RECT 354.156000 130.944000 354.240000 130.968000 ;
  END
 END bs_q[137]
 PIN bs_q[138]
  DIRECTION OUTPUT ;
  USE SIGNAL ;
  PORT
   LAYER M4 ;
   RECT 354.156000 131.136000 354.240000 131.160000 ;
  END
 END bs_q[138]
 PIN bs_q[139]
  DIRECTION OUTPUT ;
  USE SIGNAL ;
  PORT
   LAYER M4 ;
   RECT 354.156000 131.328000 354.240000 131.352000 ;
  END
 END bs_q[139]
 PIN bs_q[140]
  DIRECTION OUTPUT ;
  USE SIGNAL ;
  PORT
   LAYER M4 ;
   RECT 354.156000 131.520000 354.240000 131.544000 ;
  END
 END bs_q[140]
 PIN bs_q[141]
  DIRECTION OUTPUT ;
  USE SIGNAL ;
  PORT
   LAYER M4 ;
   RECT 354.156000 131.712000 354.240000 131.736000 ;
  END
 END bs_q[141]
 PIN bs_q[142]
  DIRECTION OUTPUT ;
  USE SIGNAL ;
  PORT
   LAYER M4 ;
   RECT 354.156000 131.904000 354.240000 131.928000 ;
  END
 END bs_q[142]
 PIN bs_q[143]
  DIRECTION OUTPUT ;
  USE SIGNAL ;
  PORT
   LAYER M4 ;
   RECT 354.156000 132.096000 354.240000 132.120000 ;
  END
 END bs_q[143]
 PIN bs_q[144]
  DIRECTION OUTPUT ;
  USE SIGNAL ;
  PORT
   LAYER M4 ;
   RECT 354.156000 132.288000 354.240000 132.312000 ;
  END
 END bs_q[144]
 PIN bs_q[145]
  DIRECTION OUTPUT ;
  USE SIGNAL ;
  PORT
   LAYER M4 ;
   RECT 354.156000 132.480000 354.240000 132.504000 ;
  END
 END bs_q[145]
 PIN bs_q[146]
  DIRECTION OUTPUT ;
  USE SIGNAL ;
  PORT
   LAYER M4 ;
   RECT 354.156000 132.672000 354.240000 132.696000 ;
  END
 END bs_q[146]
 PIN bs_q[147]
  DIRECTION OUTPUT ;
  USE SIGNAL ;
  PORT
   LAYER M4 ;
   RECT 354.156000 132.864000 354.240000 132.888000 ;
  END
 END bs_q[147]
 PIN bs_q[148]
  DIRECTION OUTPUT ;
  USE SIGNAL ;
  PORT
   LAYER M4 ;
   RECT 354.156000 133.056000 354.240000 133.080000 ;
  END
 END bs_q[148]
 PIN bs_q[149]
  DIRECTION OUTPUT ;
  USE SIGNAL ;
  PORT
   LAYER M4 ;
   RECT 354.156000 133.248000 354.240000 133.272000 ;
  END
 END bs_q[149]
 PIN bs_q[150]
  DIRECTION OUTPUT ;
  USE SIGNAL ;
  PORT
   LAYER M4 ;
   RECT 354.156000 133.440000 354.240000 133.464000 ;
  END
 END bs_q[150]
 PIN bs_q[151]
  DIRECTION OUTPUT ;
  USE SIGNAL ;
  PORT
   LAYER M4 ;
   RECT 354.156000 133.632000 354.240000 133.656000 ;
  END
 END bs_q[151]
 PIN bs_q[152]
  DIRECTION OUTPUT ;
  USE SIGNAL ;
  PORT
   LAYER M4 ;
   RECT 354.156000 133.824000 354.240000 133.848000 ;
  END
 END bs_q[152]
 PIN bs_q[153]
  DIRECTION OUTPUT ;
  USE SIGNAL ;
  PORT
   LAYER M4 ;
   RECT 354.156000 134.016000 354.240000 134.040000 ;
  END
 END bs_q[153]
 PIN bs_q[154]
  DIRECTION OUTPUT ;
  USE SIGNAL ;
  PORT
   LAYER M4 ;
   RECT 354.156000 134.208000 354.240000 134.232000 ;
  END
 END bs_q[154]
 PIN bs_q[155]
  DIRECTION OUTPUT ;
  USE SIGNAL ;
  PORT
   LAYER M4 ;
   RECT 354.156000 134.400000 354.240000 134.424000 ;
  END
 END bs_q[155]
 PIN bs_q[156]
  DIRECTION OUTPUT ;
  USE SIGNAL ;
  PORT
   LAYER M4 ;
   RECT 354.156000 134.592000 354.240000 134.616000 ;
  END
 END bs_q[156]
 PIN bs_q[157]
  DIRECTION OUTPUT ;
  USE SIGNAL ;
  PORT
   LAYER M4 ;
   RECT 354.156000 134.784000 354.240000 134.808000 ;
  END
 END bs_q[157]
 PIN bs_q[158]
  DIRECTION OUTPUT ;
  USE SIGNAL ;
  PORT
   LAYER M4 ;
   RECT 354.156000 134.976000 354.240000 135.000000 ;
  END
 END bs_q[158]
 PIN bs_q[159]
  DIRECTION OUTPUT ;
  USE SIGNAL ;
  PORT
   LAYER M4 ;
   RECT 354.156000 135.168000 354.240000 135.192000 ;
  END
 END bs_q[159]
 PIN bs_q[160]
  DIRECTION OUTPUT ;
  USE SIGNAL ;
  PORT
   LAYER M4 ;
   RECT 354.156000 135.360000 354.240000 135.384000 ;
  END
 END bs_q[160]
 PIN bs_q[161]
  DIRECTION OUTPUT ;
  USE SIGNAL ;
  PORT
   LAYER M4 ;
   RECT 354.156000 135.552000 354.240000 135.576000 ;
  END
 END bs_q[161]
 PIN bs_q[162]
  DIRECTION OUTPUT ;
  USE SIGNAL ;
  PORT
   LAYER M4 ;
   RECT 354.156000 135.744000 354.240000 135.768000 ;
  END
 END bs_q[162]
 PIN bs_q[163]
  DIRECTION OUTPUT ;
  USE SIGNAL ;
  PORT
   LAYER M4 ;
   RECT 354.156000 135.936000 354.240000 135.960000 ;
  END
 END bs_q[163]
 PIN bs_q[164]
  DIRECTION OUTPUT ;
  USE SIGNAL ;
  PORT
   LAYER M4 ;
   RECT 354.156000 136.128000 354.240000 136.152000 ;
  END
 END bs_q[164]
 PIN bs_q[165]
  DIRECTION OUTPUT ;
  USE SIGNAL ;
  PORT
   LAYER M4 ;
   RECT 354.156000 136.320000 354.240000 136.344000 ;
  END
 END bs_q[165]
 PIN bs_q[166]
  DIRECTION OUTPUT ;
  USE SIGNAL ;
  PORT
   LAYER M4 ;
   RECT 354.156000 136.512000 354.240000 136.536000 ;
  END
 END bs_q[166]
 PIN bs_q[167]
  DIRECTION OUTPUT ;
  USE SIGNAL ;
  PORT
   LAYER M4 ;
   RECT 354.156000 136.704000 354.240000 136.728000 ;
  END
 END bs_q[167]
 PIN bs_q[168]
  DIRECTION OUTPUT ;
  USE SIGNAL ;
  PORT
   LAYER M4 ;
   RECT 354.156000 136.896000 354.240000 136.920000 ;
  END
 END bs_q[168]
 PIN bs_q[169]
  DIRECTION OUTPUT ;
  USE SIGNAL ;
  PORT
   LAYER M4 ;
   RECT 354.156000 137.088000 354.240000 137.112000 ;
  END
 END bs_q[169]
 PIN bs_q[170]
  DIRECTION OUTPUT ;
  USE SIGNAL ;
  PORT
   LAYER M4 ;
   RECT 354.156000 137.280000 354.240000 137.304000 ;
  END
 END bs_q[170]
 PIN bs_q[171]
  DIRECTION OUTPUT ;
  USE SIGNAL ;
  PORT
   LAYER M4 ;
   RECT 354.156000 137.472000 354.240000 137.496000 ;
  END
 END bs_q[171]
 PIN bs_q[172]
  DIRECTION OUTPUT ;
  USE SIGNAL ;
  PORT
   LAYER M4 ;
   RECT 354.156000 137.664000 354.240000 137.688000 ;
  END
 END bs_q[172]
 PIN bs_q[173]
  DIRECTION OUTPUT ;
  USE SIGNAL ;
  PORT
   LAYER M4 ;
   RECT 354.156000 137.856000 354.240000 137.880000 ;
  END
 END bs_q[173]
 PIN bs_q[174]
  DIRECTION OUTPUT ;
  USE SIGNAL ;
  PORT
   LAYER M4 ;
   RECT 354.156000 138.048000 354.240000 138.072000 ;
  END
 END bs_q[174]
 PIN bs_q[175]
  DIRECTION OUTPUT ;
  USE SIGNAL ;
  PORT
   LAYER M4 ;
   RECT 354.156000 138.240000 354.240000 138.264000 ;
  END
 END bs_q[175]
 PIN bs_q[176]
  DIRECTION OUTPUT ;
  USE SIGNAL ;
  PORT
   LAYER M4 ;
   RECT 354.156000 138.432000 354.240000 138.456000 ;
  END
 END bs_q[176]
 PIN bs_q[177]
  DIRECTION OUTPUT ;
  USE SIGNAL ;
  PORT
   LAYER M4 ;
   RECT 354.156000 138.624000 354.240000 138.648000 ;
  END
 END bs_q[177]
 PIN bs_q[178]
  DIRECTION OUTPUT ;
  USE SIGNAL ;
  PORT
   LAYER M4 ;
   RECT 354.156000 138.816000 354.240000 138.840000 ;
  END
 END bs_q[178]
 PIN bs_q[179]
  DIRECTION OUTPUT ;
  USE SIGNAL ;
  PORT
   LAYER M4 ;
   RECT 354.156000 139.008000 354.240000 139.032000 ;
  END
 END bs_q[179]
 PIN bs_q[180]
  DIRECTION OUTPUT ;
  USE SIGNAL ;
  PORT
   LAYER M4 ;
   RECT 354.156000 139.200000 354.240000 139.224000 ;
  END
 END bs_q[180]
 PIN bs_q[181]
  DIRECTION OUTPUT ;
  USE SIGNAL ;
  PORT
   LAYER M4 ;
   RECT 354.156000 139.392000 354.240000 139.416000 ;
  END
 END bs_q[181]
 PIN bs_q[182]
  DIRECTION OUTPUT ;
  USE SIGNAL ;
  PORT
   LAYER M4 ;
   RECT 354.156000 139.584000 354.240000 139.608000 ;
  END
 END bs_q[182]
 PIN bs_q[183]
  DIRECTION OUTPUT ;
  USE SIGNAL ;
  PORT
   LAYER M4 ;
   RECT 354.156000 139.776000 354.240000 139.800000 ;
  END
 END bs_q[183]
 PIN bs_q[184]
  DIRECTION OUTPUT ;
  USE SIGNAL ;
  PORT
   LAYER M4 ;
   RECT 354.156000 139.968000 354.240000 139.992000 ;
  END
 END bs_q[184]
 PIN bs_q[185]
  DIRECTION OUTPUT ;
  USE SIGNAL ;
  PORT
   LAYER M4 ;
   RECT 354.156000 140.160000 354.240000 140.184000 ;
  END
 END bs_q[185]
 PIN bs_q[186]
  DIRECTION OUTPUT ;
  USE SIGNAL ;
  PORT
   LAYER M4 ;
   RECT 354.156000 140.352000 354.240000 140.376000 ;
  END
 END bs_q[186]
 PIN bs_q[187]
  DIRECTION OUTPUT ;
  USE SIGNAL ;
  PORT
   LAYER M4 ;
   RECT 354.156000 140.544000 354.240000 140.568000 ;
  END
 END bs_q[187]
 PIN bs_q[188]
  DIRECTION OUTPUT ;
  USE SIGNAL ;
  PORT
   LAYER M4 ;
   RECT 354.156000 140.736000 354.240000 140.760000 ;
  END
 END bs_q[188]
 PIN bs_q[189]
  DIRECTION OUTPUT ;
  USE SIGNAL ;
  PORT
   LAYER M4 ;
   RECT 354.156000 140.928000 354.240000 140.952000 ;
  END
 END bs_q[189]
 PIN bs_q[190]
  DIRECTION OUTPUT ;
  USE SIGNAL ;
  PORT
   LAYER M4 ;
   RECT 354.156000 141.120000 354.240000 141.144000 ;
  END
 END bs_q[190]
 PIN bs_q[191]
  DIRECTION OUTPUT ;
  USE SIGNAL ;
  PORT
   LAYER M4 ;
   RECT 354.156000 141.312000 354.240000 141.336000 ;
  END
 END bs_q[191]
 PIN bs_q[192]
  DIRECTION OUTPUT ;
  USE SIGNAL ;
  PORT
   LAYER M4 ;
   RECT 354.156000 141.504000 354.240000 141.528000 ;
  END
 END bs_q[192]
 PIN bs_q[193]
  DIRECTION OUTPUT ;
  USE SIGNAL ;
  PORT
   LAYER M4 ;
   RECT 354.156000 141.696000 354.240000 141.720000 ;
  END
 END bs_q[193]
 PIN bs_q[194]
  DIRECTION OUTPUT ;
  USE SIGNAL ;
  PORT
   LAYER M4 ;
   RECT 354.156000 141.888000 354.240000 141.912000 ;
  END
 END bs_q[194]
 PIN bs_q[195]
  DIRECTION OUTPUT ;
  USE SIGNAL ;
  PORT
   LAYER M4 ;
   RECT 354.156000 142.080000 354.240000 142.104000 ;
  END
 END bs_q[195]
 PIN bs_q[196]
  DIRECTION OUTPUT ;
  USE SIGNAL ;
  PORT
   LAYER M4 ;
   RECT 354.156000 142.272000 354.240000 142.296000 ;
  END
 END bs_q[196]
 PIN bs_q[197]
  DIRECTION OUTPUT ;
  USE SIGNAL ;
  PORT
   LAYER M4 ;
   RECT 354.156000 142.464000 354.240000 142.488000 ;
  END
 END bs_q[197]
 PIN bs_q[198]
  DIRECTION OUTPUT ;
  USE SIGNAL ;
  PORT
   LAYER M4 ;
   RECT 354.156000 142.656000 354.240000 142.680000 ;
  END
 END bs_q[198]
 PIN bs_q[199]
  DIRECTION OUTPUT ;
  USE SIGNAL ;
  PORT
   LAYER M4 ;
   RECT 354.156000 142.848000 354.240000 142.872000 ;
  END
 END bs_q[199]
 PIN bs_q[200]
  DIRECTION OUTPUT ;
  USE SIGNAL ;
  PORT
   LAYER M4 ;
   RECT 354.156000 143.040000 354.240000 143.064000 ;
  END
 END bs_q[200]
 PIN bs_q[201]
  DIRECTION OUTPUT ;
  USE SIGNAL ;
  PORT
   LAYER M4 ;
   RECT 354.156000 143.232000 354.240000 143.256000 ;
  END
 END bs_q[201]
 PIN bs_q[202]
  DIRECTION OUTPUT ;
  USE SIGNAL ;
  PORT
   LAYER M4 ;
   RECT 354.156000 143.424000 354.240000 143.448000 ;
  END
 END bs_q[202]
 PIN bs_q[203]
  DIRECTION OUTPUT ;
  USE SIGNAL ;
  PORT
   LAYER M4 ;
   RECT 354.156000 143.616000 354.240000 143.640000 ;
  END
 END bs_q[203]
 PIN bs_q[204]
  DIRECTION OUTPUT ;
  USE SIGNAL ;
  PORT
   LAYER M4 ;
   RECT 354.156000 143.808000 354.240000 143.832000 ;
  END
 END bs_q[204]
 PIN bs_q[205]
  DIRECTION OUTPUT ;
  USE SIGNAL ;
  PORT
   LAYER M4 ;
   RECT 354.156000 144.000000 354.240000 144.024000 ;
  END
 END bs_q[205]
 PIN bs_q[206]
  DIRECTION OUTPUT ;
  USE SIGNAL ;
  PORT
   LAYER M4 ;
   RECT 354.156000 144.192000 354.240000 144.216000 ;
  END
 END bs_q[206]
 PIN bs_q[207]
  DIRECTION OUTPUT ;
  USE SIGNAL ;
  PORT
   LAYER M4 ;
   RECT 354.156000 144.384000 354.240000 144.408000 ;
  END
 END bs_q[207]
 PIN bs_q[208]
  DIRECTION OUTPUT ;
  USE SIGNAL ;
  PORT
   LAYER M4 ;
   RECT 354.156000 144.576000 354.240000 144.600000 ;
  END
 END bs_q[208]
 PIN bs_q[209]
  DIRECTION OUTPUT ;
  USE SIGNAL ;
  PORT
   LAYER M4 ;
   RECT 354.156000 144.768000 354.240000 144.792000 ;
  END
 END bs_q[209]
 PIN bs_q[210]
  DIRECTION OUTPUT ;
  USE SIGNAL ;
  PORT
   LAYER M4 ;
   RECT 354.156000 144.960000 354.240000 144.984000 ;
  END
 END bs_q[210]
 PIN bs_q[211]
  DIRECTION OUTPUT ;
  USE SIGNAL ;
  PORT
   LAYER M4 ;
   RECT 354.156000 145.152000 354.240000 145.176000 ;
  END
 END bs_q[211]
 PIN bs_q[212]
  DIRECTION OUTPUT ;
  USE SIGNAL ;
  PORT
   LAYER M4 ;
   RECT 354.156000 145.344000 354.240000 145.368000 ;
  END
 END bs_q[212]
 PIN bs_q[213]
  DIRECTION OUTPUT ;
  USE SIGNAL ;
  PORT
   LAYER M4 ;
   RECT 354.156000 145.536000 354.240000 145.560000 ;
  END
 END bs_q[213]
 PIN bs_q[214]
  DIRECTION OUTPUT ;
  USE SIGNAL ;
  PORT
   LAYER M4 ;
   RECT 354.156000 145.728000 354.240000 145.752000 ;
  END
 END bs_q[214]
 PIN bs_q[215]
  DIRECTION OUTPUT ;
  USE SIGNAL ;
  PORT
   LAYER M4 ;
   RECT 354.156000 145.920000 354.240000 145.944000 ;
  END
 END bs_q[215]
 PIN bs_q[216]
  DIRECTION OUTPUT ;
  USE SIGNAL ;
  PORT
   LAYER M4 ;
   RECT 354.156000 146.112000 354.240000 146.136000 ;
  END
 END bs_q[216]
 PIN bs_q[217]
  DIRECTION OUTPUT ;
  USE SIGNAL ;
  PORT
   LAYER M4 ;
   RECT 354.156000 146.304000 354.240000 146.328000 ;
  END
 END bs_q[217]
 PIN bs_q[218]
  DIRECTION OUTPUT ;
  USE SIGNAL ;
  PORT
   LAYER M4 ;
   RECT 354.156000 146.496000 354.240000 146.520000 ;
  END
 END bs_q[218]
 PIN bs_q[219]
  DIRECTION OUTPUT ;
  USE SIGNAL ;
  PORT
   LAYER M4 ;
   RECT 354.156000 146.688000 354.240000 146.712000 ;
  END
 END bs_q[219]
 PIN bs_q[220]
  DIRECTION OUTPUT ;
  USE SIGNAL ;
  PORT
   LAYER M4 ;
   RECT 354.156000 146.880000 354.240000 146.904000 ;
  END
 END bs_q[220]
 PIN bs_q[221]
  DIRECTION OUTPUT ;
  USE SIGNAL ;
  PORT
   LAYER M4 ;
   RECT 354.156000 147.072000 354.240000 147.096000 ;
  END
 END bs_q[221]
 PIN bs_q[222]
  DIRECTION OUTPUT ;
  USE SIGNAL ;
  PORT
   LAYER M4 ;
   RECT 354.156000 147.264000 354.240000 147.288000 ;
  END
 END bs_q[222]
 PIN bs_q[223]
  DIRECTION OUTPUT ;
  USE SIGNAL ;
  PORT
   LAYER M4 ;
   RECT 354.156000 147.456000 354.240000 147.480000 ;
  END
 END bs_q[223]
 PIN bs_q[224]
  DIRECTION OUTPUT ;
  USE SIGNAL ;
  PORT
   LAYER M4 ;
   RECT 354.156000 147.648000 354.240000 147.672000 ;
  END
 END bs_q[224]
 PIN bs_q[225]
  DIRECTION OUTPUT ;
  USE SIGNAL ;
  PORT
   LAYER M4 ;
   RECT 354.156000 147.840000 354.240000 147.864000 ;
  END
 END bs_q[225]
 PIN bs_q[226]
  DIRECTION OUTPUT ;
  USE SIGNAL ;
  PORT
   LAYER M4 ;
   RECT 354.156000 148.032000 354.240000 148.056000 ;
  END
 END bs_q[226]
 PIN bs_q[227]
  DIRECTION OUTPUT ;
  USE SIGNAL ;
  PORT
   LAYER M4 ;
   RECT 354.156000 148.224000 354.240000 148.248000 ;
  END
 END bs_q[227]
 PIN bs_q[228]
  DIRECTION OUTPUT ;
  USE SIGNAL ;
  PORT
   LAYER M4 ;
   RECT 354.156000 148.416000 354.240000 148.440000 ;
  END
 END bs_q[228]
 PIN bs_q[229]
  DIRECTION OUTPUT ;
  USE SIGNAL ;
  PORT
   LAYER M4 ;
   RECT 354.156000 148.608000 354.240000 148.632000 ;
  END
 END bs_q[229]
 PIN bs_q[230]
  DIRECTION OUTPUT ;
  USE SIGNAL ;
  PORT
   LAYER M4 ;
   RECT 354.156000 148.800000 354.240000 148.824000 ;
  END
 END bs_q[230]
 PIN bs_q[231]
  DIRECTION OUTPUT ;
  USE SIGNAL ;
  PORT
   LAYER M4 ;
   RECT 354.156000 148.992000 354.240000 149.016000 ;
  END
 END bs_q[231]
 PIN bs_q[232]
  DIRECTION OUTPUT ;
  USE SIGNAL ;
  PORT
   LAYER M4 ;
   RECT 354.156000 149.184000 354.240000 149.208000 ;
  END
 END bs_q[232]
 PIN bs_q[233]
  DIRECTION OUTPUT ;
  USE SIGNAL ;
  PORT
   LAYER M4 ;
   RECT 354.156000 149.376000 354.240000 149.400000 ;
  END
 END bs_q[233]
 PIN bs_q[234]
  DIRECTION OUTPUT ;
  USE SIGNAL ;
  PORT
   LAYER M4 ;
   RECT 354.156000 149.568000 354.240000 149.592000 ;
  END
 END bs_q[234]
 PIN bs_q[235]
  DIRECTION OUTPUT ;
  USE SIGNAL ;
  PORT
   LAYER M4 ;
   RECT 354.156000 149.760000 354.240000 149.784000 ;
  END
 END bs_q[235]
 PIN bs_q[236]
  DIRECTION OUTPUT ;
  USE SIGNAL ;
  PORT
   LAYER M4 ;
   RECT 354.156000 149.952000 354.240000 149.976000 ;
  END
 END bs_q[236]
 PIN bs_q[237]
  DIRECTION OUTPUT ;
  USE SIGNAL ;
  PORT
   LAYER M4 ;
   RECT 354.156000 150.144000 354.240000 150.168000 ;
  END
 END bs_q[237]
 PIN bs_q[238]
  DIRECTION OUTPUT ;
  USE SIGNAL ;
  PORT
   LAYER M4 ;
   RECT 354.156000 150.336000 354.240000 150.360000 ;
  END
 END bs_q[238]
 PIN bs_q[239]
  DIRECTION OUTPUT ;
  USE SIGNAL ;
  PORT
   LAYER M4 ;
   RECT 354.156000 150.528000 354.240000 150.552000 ;
  END
 END bs_q[239]
 PIN bs_q[240]
  DIRECTION OUTPUT ;
  USE SIGNAL ;
  PORT
   LAYER M4 ;
   RECT 354.156000 150.720000 354.240000 150.744000 ;
  END
 END bs_q[240]
 PIN bs_q[241]
  DIRECTION OUTPUT ;
  USE SIGNAL ;
  PORT
   LAYER M4 ;
   RECT 354.156000 150.912000 354.240000 150.936000 ;
  END
 END bs_q[241]
 PIN bs_q[242]
  DIRECTION OUTPUT ;
  USE SIGNAL ;
  PORT
   LAYER M4 ;
   RECT 354.156000 151.104000 354.240000 151.128000 ;
  END
 END bs_q[242]
 PIN bs_q[243]
  DIRECTION OUTPUT ;
  USE SIGNAL ;
  PORT
   LAYER M4 ;
   RECT 354.156000 151.296000 354.240000 151.320000 ;
  END
 END bs_q[243]
 PIN bs_q[244]
  DIRECTION OUTPUT ;
  USE SIGNAL ;
  PORT
   LAYER M4 ;
   RECT 354.156000 151.488000 354.240000 151.512000 ;
  END
 END bs_q[244]
 PIN bs_q[245]
  DIRECTION OUTPUT ;
  USE SIGNAL ;
  PORT
   LAYER M4 ;
   RECT 354.156000 151.680000 354.240000 151.704000 ;
  END
 END bs_q[245]
 PIN bs_q[246]
  DIRECTION OUTPUT ;
  USE SIGNAL ;
  PORT
   LAYER M4 ;
   RECT 354.156000 151.872000 354.240000 151.896000 ;
  END
 END bs_q[246]
 PIN bs_q[247]
  DIRECTION OUTPUT ;
  USE SIGNAL ;
  PORT
   LAYER M4 ;
   RECT 354.156000 152.064000 354.240000 152.088000 ;
  END
 END bs_q[247]
 PIN bs_q[248]
  DIRECTION OUTPUT ;
  USE SIGNAL ;
  PORT
   LAYER M4 ;
   RECT 354.156000 152.256000 354.240000 152.280000 ;
  END
 END bs_q[248]
 PIN bs_q[249]
  DIRECTION OUTPUT ;
  USE SIGNAL ;
  PORT
   LAYER M4 ;
   RECT 354.156000 152.448000 354.240000 152.472000 ;
  END
 END bs_q[249]
 PIN bs_q[250]
  DIRECTION OUTPUT ;
  USE SIGNAL ;
  PORT
   LAYER M4 ;
   RECT 354.156000 152.640000 354.240000 152.664000 ;
  END
 END bs_q[250]
 PIN bs_q[251]
  DIRECTION OUTPUT ;
  USE SIGNAL ;
  PORT
   LAYER M4 ;
   RECT 354.156000 152.832000 354.240000 152.856000 ;
  END
 END bs_q[251]
 PIN bs_q[252]
  DIRECTION OUTPUT ;
  USE SIGNAL ;
  PORT
   LAYER M4 ;
   RECT 354.156000 153.024000 354.240000 153.048000 ;
  END
 END bs_q[252]
 PIN bs_q[253]
  DIRECTION OUTPUT ;
  USE SIGNAL ;
  PORT
   LAYER M4 ;
   RECT 354.156000 153.216000 354.240000 153.240000 ;
  END
 END bs_q[253]
 PIN bs_q[254]
  DIRECTION OUTPUT ;
  USE SIGNAL ;
  PORT
   LAYER M4 ;
   RECT 354.156000 153.408000 354.240000 153.432000 ;
  END
 END bs_q[254]
 PIN bs_q[255]
  DIRECTION OUTPUT ;
  USE SIGNAL ;
  PORT
   LAYER M4 ;
   RECT 354.156000 153.600000 354.240000 153.624000 ;
  END
 END bs_q[255]
 PIN tw_addr[2]
  DIRECTION INPUT ;
  USE SIGNAL ;
  PORT
   LAYER M5 ;
   RECT 302.400000 0.000000 302.424000 0.084000 ;
  END
 END tw_addr[2]
 PIN tw_addr[3]
  DIRECTION INPUT ;
  USE SIGNAL ;
  PORT
   LAYER M5 ;
   RECT 302.592000 0.000000 302.616000 0.084000 ;
  END
 END tw_addr[3]
 PIN tw_addr[4]
  DIRECTION INPUT ;
  USE SIGNAL ;
  PORT
   LAYER M5 ;
   RECT 302.784000 0.000000 302.808000 0.084000 ;
  END
 END tw_addr[4]
 PIN tw_addr[5]
  DIRECTION INPUT ;
  USE SIGNAL ;
  PORT
   LAYER M5 ;
   RECT 302.976000 0.000000 303.000000 0.084000 ;
  END
 END tw_addr[5]
 PIN tw_addr[6]
  DIRECTION INPUT ;
  USE SIGNAL ;
  PORT
   LAYER M5 ;
   RECT 303.168000 0.000000 303.192000 0.084000 ;
  END
 END tw_addr[6]
 PIN tw_addr[7]
  DIRECTION INPUT ;
  USE SIGNAL ;
  PORT
   LAYER M5 ;
   RECT 303.360000 0.000000 303.384000 0.084000 ;
  END
 END tw_addr[7]
 PIN tw_addr[8]
  DIRECTION INPUT ;
  USE SIGNAL ;
  PORT
   LAYER M5 ;
   RECT 303.552000 0.000000 303.576000 0.084000 ;
  END
 END tw_addr[8]
 PIN tw_kind[0]
  DIRECTION INPUT ;
  USE SIGNAL ;
  PORT
   LAYER M5 ;
   RECT 307.584000 0.000000 307.608000 0.084000 ;
  END
 END tw_kind[0]
 PIN tw_kind[1]
  DIRECTION INPUT ;
  USE SIGNAL ;
  PORT
   LAYER M5 ;
   RECT 307.776000 0.000000 307.800000 0.084000 ;
  END
 END tw_kind[1]
 PIN tw_we
  DIRECTION INPUT ;
  USE SIGNAL ;
  PORT
   LAYER M5 ;
   RECT 310.176000 0.000000 310.200000 0.084000 ;
  END
 END tw_we
 PIN rst_n
  DIRECTION INPUT ;
  USE SIGNAL ;
  PORT
   LAYER M5 ;
   RECT 327.456000 0.000000 327.480000 0.084000 ;
  END
 END rst_n
 PIN fault
  DIRECTION OUTPUT ;
  USE SIGNAL ;
  PORT
   LAYER M5 ;
   RECT 330.048000 0.000000 330.072000 0.084000 ;
  END
 END fault
 PIN ck
  DIRECTION INPUT ;
  USE CLOCK ;
  PORT
   LAYER M5 ;
   RECT 178.128000 0.000000 178.152000 0.084000 ;
  END
 END ck
END qfd_dv_s8x_btab
END LIBRARY
